VERSION 5.8 ;
BUSBITCHARS "[]" ;
DIVIDERCHAR "/" ;
UNITS
    DATABASE MICRONS 1000 ;
END UNITS

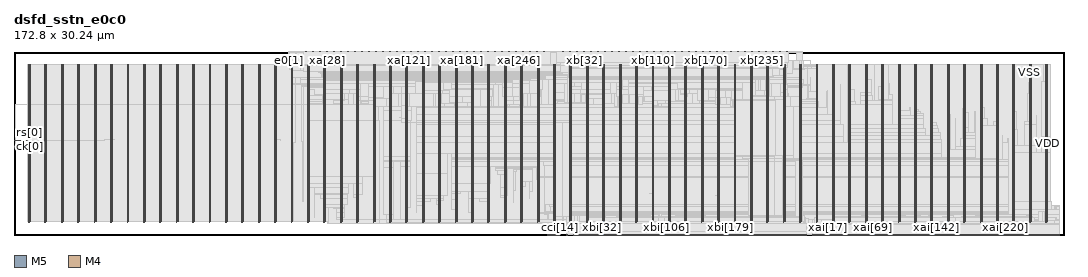
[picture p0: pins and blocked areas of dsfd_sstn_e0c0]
MACRO dsfd_sstn_e0c0
  FOREIGN dsfd_sstn_e0c0 0 0 ;
  CLASS BLOCK ;
  SIZE 172.8 BY 30.24 ;
  PIN c0[0]
    DIRECTION INPUT ;
    USE SIGNAL ;
    PORT
      LAYER M5 ;
        RECT  46.368 30.156 46.392 30.24 ;
    END
  END c0[0]
  PIN c0[1]
    DIRECTION INPUT ;
    USE SIGNAL ;
    PORT
      LAYER M5 ;
        RECT  46.512 30.156 46.536 30.24 ;
    END
  END c0[1]
  PIN cci[0]
    DIRECTION INPUT ;
    USE SIGNAL ;
    PORT
      LAYER M5 ;
        RECT  87.792 0 87.816 0.084 ;
    END
  END cci[0]
  PIN cci[10]
    DIRECTION INPUT ;
    USE SIGNAL ;
    PORT
      LAYER M5 ;
        RECT  89.232 0 89.256 0.084 ;
    END
  END cci[10]
  PIN cci[11]
    DIRECTION INPUT ;
    USE SIGNAL ;
    PORT
      LAYER M5 ;
        RECT  89.376 0 89.4 0.084 ;
    END
  END cci[11]
  PIN cci[12]
    DIRECTION INPUT ;
    USE SIGNAL ;
    PORT
      LAYER M5 ;
        RECT  89.52 0 89.544 0.084 ;
    END
  END cci[12]
  PIN cci[13]
    DIRECTION INPUT ;
    USE SIGNAL ;
    PORT
      LAYER M5 ;
        RECT  89.664 0 89.688 0.084 ;
    END
  END cci[13]
  PIN cci[14]
    DIRECTION INPUT ;
    USE SIGNAL ;
    PORT
      LAYER M5 ;
        RECT  89.808 0 89.832 0.084 ;
    END
  END cci[14]
  PIN cci[1]
    DIRECTION INPUT ;
    USE SIGNAL ;
    PORT
      LAYER M5 ;
        RECT  87.936 0 87.96 0.084 ;
    END
  END cci[1]
  PIN cci[2]
    DIRECTION INPUT ;
    USE SIGNAL ;
    PORT
      LAYER M5 ;
        RECT  88.08 0 88.104 0.084 ;
    END
  END cci[2]
  PIN cci[3]
    DIRECTION INPUT ;
    USE SIGNAL ;
    PORT
      LAYER M5 ;
        RECT  88.224 0 88.248 0.084 ;
    END
  END cci[3]
  PIN cci[4]
    DIRECTION INPUT ;
    USE SIGNAL ;
    PORT
      LAYER M5 ;
        RECT  88.368 0 88.392 0.084 ;
    END
  END cci[4]
  PIN cci[5]
    DIRECTION INPUT ;
    USE SIGNAL ;
    PORT
      LAYER M5 ;
        RECT  88.512 0 88.536 0.084 ;
    END
  END cci[5]
  PIN cci[6]
    DIRECTION INPUT ;
    USE SIGNAL ;
    PORT
      LAYER M5 ;
        RECT  88.656 0 88.68 0.084 ;
    END
  END cci[6]
  PIN cci[7]
    DIRECTION INPUT ;
    USE SIGNAL ;
    PORT
      LAYER M5 ;
        RECT  88.8 0 88.824 0.084 ;
    END
  END cci[7]
  PIN cci[8]
    DIRECTION INPUT ;
    USE SIGNAL ;
    PORT
      LAYER M5 ;
        RECT  88.944 0 88.968 0.084 ;
    END
  END cci[8]
  PIN cci[9]
    DIRECTION INPUT ;
    USE SIGNAL ;
    PORT
      LAYER M5 ;
        RECT  89.088 0 89.112 0.084 ;
    END
  END cci[9]
  PIN ck[0]
    DIRECTION INPUT ;
    USE SIGNAL ;
    PORT
      LAYER M4 ;
        RECT  0 14.592 0.084 14.616 ;
    END
    PORT
      LAYER M4 ;
        RECT  0.06 14.592 0.227 14.616 ;
    END
  END ck[0]
  PIN e0[0]
    DIRECTION INPUT ;
    USE SIGNAL ;
    PORT
      LAYER M5 ;
        RECT  45.12 30.156 45.144 30.24 ;
    END
  END e0[0]
  PIN e0[1]
    DIRECTION INPUT ;
    USE SIGNAL ;
    PORT
      LAYER M5 ;
        RECT  45.264 30.156 45.288 30.24 ;
    END
  END e0[1]
  PIN rs[0]
    DIRECTION INPUT ;
    USE SIGNAL ;
    PORT
      LAYER M4 ;
        RECT  0 15.6 0.084 15.624 ;
    END
    PORT
      LAYER M4 ;
        RECT  0.06 15.6 2.408 15.624 ;
    END
  END rs[0]
  PIN so[0]
    DIRECTION OUTPUT ;
    USE SIGNAL ;
    PORT
      LAYER M5 ;
        RECT  90.912 0 90.936 0.084 ;
    END
  END so[0]
  PIN so[1]
    DIRECTION OUTPUT ;
    USE SIGNAL ;
    PORT
      LAYER M5 ;
        RECT  91.056 0 91.08 0.084 ;
    END
  END so[1]
  PIN xa[0]
    DIRECTION OUTPUT ;
    USE SIGNAL ;
    PORT
      LAYER M5 ;
        RECT  47.616 30.156 47.64 30.24 ;
    END
  END xa[0]
  PIN xa[100]
    DIRECTION OUTPUT ;
    USE SIGNAL ;
    PORT
      LAYER M5 ;
        RECT  62.016 30.156 62.04 30.24 ;
    END
  END xa[100]
  PIN xa[101]
    DIRECTION OUTPUT ;
    USE SIGNAL ;
    PORT
      LAYER M5 ;
        RECT  62.16 30.156 62.184 30.24 ;
    END
  END xa[101]
  PIN xa[102]
    DIRECTION OUTPUT ;
    USE SIGNAL ;
    PORT
      LAYER M5 ;
        RECT  62.304 30.156 62.328 30.24 ;
    END
  END xa[102]
  PIN xa[103]
    DIRECTION OUTPUT ;
    USE SIGNAL ;
    PORT
      LAYER M5 ;
        RECT  62.448 30.156 62.472 30.24 ;
    END
  END xa[103]
  PIN xa[104]
    DIRECTION OUTPUT ;
    USE SIGNAL ;
    PORT
      LAYER M5 ;
        RECT  62.592 30.156 62.616 30.24 ;
    END
  END xa[104]
  PIN xa[105]
    DIRECTION OUTPUT ;
    USE SIGNAL ;
    PORT
      LAYER M5 ;
        RECT  62.736 30.156 62.76 30.24 ;
    END
  END xa[105]
  PIN xa[106]
    DIRECTION OUTPUT ;
    USE SIGNAL ;
    PORT
      LAYER M5 ;
        RECT  62.88 30.156 62.904 30.24 ;
    END
  END xa[106]
  PIN xa[107]
    DIRECTION OUTPUT ;
    USE SIGNAL ;
    PORT
      LAYER M5 ;
        RECT  63.024 30.156 63.048 30.24 ;
    END
  END xa[107]
  PIN xa[108]
    DIRECTION OUTPUT ;
    USE SIGNAL ;
    PORT
      LAYER M5 ;
        RECT  63.168 30.156 63.192 30.24 ;
    END
  END xa[108]
  PIN xa[109]
    DIRECTION OUTPUT ;
    USE SIGNAL ;
    PORT
      LAYER M5 ;
        RECT  63.312 30.156 63.336 30.24 ;
    END
  END xa[109]
  PIN xa[10]
    DIRECTION OUTPUT ;
    USE SIGNAL ;
    PORT
      LAYER M5 ;
        RECT  49.056 30.156 49.08 30.24 ;
    END
  END xa[10]
  PIN xa[110]
    DIRECTION OUTPUT ;
    USE SIGNAL ;
    PORT
      LAYER M5 ;
        RECT  63.456 30.156 63.48 30.24 ;
    END
  END xa[110]
  PIN xa[111]
    DIRECTION OUTPUT ;
    USE SIGNAL ;
    PORT
      LAYER M5 ;
        RECT  63.6 30.156 63.624 30.24 ;
    END
  END xa[111]
  PIN xa[112]
    DIRECTION OUTPUT ;
    USE SIGNAL ;
    PORT
      LAYER M5 ;
        RECT  63.744 30.156 63.768 30.24 ;
    END
  END xa[112]
  PIN xa[113]
    DIRECTION OUTPUT ;
    USE SIGNAL ;
    PORT
      LAYER M5 ;
        RECT  63.888 30.156 63.912 30.24 ;
    END
  END xa[113]
  PIN xa[114]
    DIRECTION OUTPUT ;
    USE SIGNAL ;
    PORT
      LAYER M5 ;
        RECT  64.032 30.156 64.056 30.24 ;
    END
  END xa[114]
  PIN xa[115]
    DIRECTION OUTPUT ;
    USE SIGNAL ;
    PORT
      LAYER M5 ;
        RECT  64.176 30.156 64.2 30.24 ;
    END
  END xa[115]
  PIN xa[116]
    DIRECTION OUTPUT ;
    USE SIGNAL ;
    PORT
      LAYER M5 ;
        RECT  64.32 30.156 64.344 30.24 ;
    END
  END xa[116]
  PIN xa[117]
    DIRECTION OUTPUT ;
    USE SIGNAL ;
    PORT
      LAYER M5 ;
        RECT  64.464 30.156 64.488 30.24 ;
    END
  END xa[117]
  PIN xa[118]
    DIRECTION OUTPUT ;
    USE SIGNAL ;
    PORT
      LAYER M5 ;
        RECT  64.608 30.156 64.632 30.24 ;
    END
  END xa[118]
  PIN xa[119]
    DIRECTION OUTPUT ;
    USE SIGNAL ;
    PORT
      LAYER M5 ;
        RECT  64.752 30.156 64.776 30.24 ;
    END
  END xa[119]
  PIN xa[11]
    DIRECTION OUTPUT ;
    USE SIGNAL ;
    PORT
      LAYER M5 ;
        RECT  49.2 30.156 49.224 30.24 ;
    END
  END xa[11]
  PIN xa[120]
    DIRECTION OUTPUT ;
    USE SIGNAL ;
    PORT
      LAYER M5 ;
        RECT  64.896 30.156 64.92 30.24 ;
    END
  END xa[120]
  PIN xa[121]
    DIRECTION OUTPUT ;
    USE SIGNAL ;
    PORT
      LAYER M5 ;
        RECT  65.04 30.156 65.064 30.24 ;
    END
  END xa[121]
  PIN xa[122]
    DIRECTION OUTPUT ;
    USE SIGNAL ;
    PORT
      LAYER M5 ;
        RECT  65.184 30.156 65.208 30.24 ;
    END
  END xa[122]
  PIN xa[123]
    DIRECTION OUTPUT ;
    USE SIGNAL ;
    PORT
      LAYER M5 ;
        RECT  65.328 30.156 65.352 30.24 ;
    END
  END xa[123]
  PIN xa[124]
    DIRECTION OUTPUT ;
    USE SIGNAL ;
    PORT
      LAYER M5 ;
        RECT  65.472 30.156 65.496 30.24 ;
    END
  END xa[124]
  PIN xa[125]
    DIRECTION OUTPUT ;
    USE SIGNAL ;
    PORT
      LAYER M5 ;
        RECT  65.616 30.156 65.64 30.24 ;
    END
  END xa[125]
  PIN xa[126]
    DIRECTION OUTPUT ;
    USE SIGNAL ;
    PORT
      LAYER M5 ;
        RECT  65.76 30.156 65.784 30.24 ;
    END
  END xa[126]
  PIN xa[127]
    DIRECTION OUTPUT ;
    USE SIGNAL ;
    PORT
      LAYER M5 ;
        RECT  65.904 30.156 65.928 30.24 ;
    END
  END xa[127]
  PIN xa[128]
    DIRECTION OUTPUT ;
    USE SIGNAL ;
    PORT
      LAYER M5 ;
        RECT  66.048 30.156 66.072 30.24 ;
    END
  END xa[128]
  PIN xa[129]
    DIRECTION OUTPUT ;
    USE SIGNAL ;
    PORT
      LAYER M5 ;
        RECT  66.192 30.156 66.216 30.24 ;
    END
  END xa[129]
  PIN xa[12]
    DIRECTION OUTPUT ;
    USE SIGNAL ;
    PORT
      LAYER M5 ;
        RECT  49.344 30.156 49.368 30.24 ;
    END
  END xa[12]
  PIN xa[130]
    DIRECTION OUTPUT ;
    USE SIGNAL ;
    PORT
      LAYER M5 ;
        RECT  66.336 30.156 66.36 30.24 ;
    END
  END xa[130]
  PIN xa[131]
    DIRECTION OUTPUT ;
    USE SIGNAL ;
    PORT
      LAYER M5 ;
        RECT  66.48 30.156 66.504 30.24 ;
    END
  END xa[131]
  PIN xa[132]
    DIRECTION OUTPUT ;
    USE SIGNAL ;
    PORT
      LAYER M5 ;
        RECT  66.624 30.156 66.648 30.24 ;
    END
  END xa[132]
  PIN xa[133]
    DIRECTION OUTPUT ;
    USE SIGNAL ;
    PORT
      LAYER M5 ;
        RECT  66.768 30.156 66.792 30.24 ;
    END
  END xa[133]
  PIN xa[134]
    DIRECTION OUTPUT ;
    USE SIGNAL ;
    PORT
      LAYER M5 ;
        RECT  66.912 30.156 66.936 30.24 ;
    END
  END xa[134]
  PIN xa[135]
    DIRECTION OUTPUT ;
    USE SIGNAL ;
    PORT
      LAYER M5 ;
        RECT  67.056 30.156 67.08 30.24 ;
    END
  END xa[135]
  PIN xa[136]
    DIRECTION OUTPUT ;
    USE SIGNAL ;
    PORT
      LAYER M5 ;
        RECT  67.2 30.156 67.224 30.24 ;
    END
  END xa[136]
  PIN xa[137]
    DIRECTION OUTPUT ;
    USE SIGNAL ;
    PORT
      LAYER M5 ;
        RECT  67.344 30.156 67.368 30.24 ;
    END
  END xa[137]
  PIN xa[138]
    DIRECTION OUTPUT ;
    USE SIGNAL ;
    PORT
      LAYER M5 ;
        RECT  67.488 30.156 67.512 30.24 ;
    END
  END xa[138]
  PIN xa[139]
    DIRECTION OUTPUT ;
    USE SIGNAL ;
    PORT
      LAYER M5 ;
        RECT  67.632 30.156 67.656 30.24 ;
    END
  END xa[139]
  PIN xa[13]
    DIRECTION OUTPUT ;
    USE SIGNAL ;
    PORT
      LAYER M5 ;
        RECT  49.488 30.156 49.512 30.24 ;
    END
  END xa[13]
  PIN xa[140]
    DIRECTION OUTPUT ;
    USE SIGNAL ;
    PORT
      LAYER M5 ;
        RECT  67.776 30.156 67.8 30.24 ;
    END
  END xa[140]
  PIN xa[141]
    DIRECTION OUTPUT ;
    USE SIGNAL ;
    PORT
      LAYER M5 ;
        RECT  67.92 30.156 67.944 30.24 ;
    END
  END xa[141]
  PIN xa[142]
    DIRECTION OUTPUT ;
    USE SIGNAL ;
    PORT
      LAYER M5 ;
        RECT  68.064 30.156 68.088 30.24 ;
    END
  END xa[142]
  PIN xa[143]
    DIRECTION OUTPUT ;
    USE SIGNAL ;
    PORT
      LAYER M5 ;
        RECT  68.208 30.156 68.232 30.24 ;
    END
  END xa[143]
  PIN xa[144]
    DIRECTION OUTPUT ;
    USE SIGNAL ;
    PORT
      LAYER M5 ;
        RECT  68.352 30.156 68.376 30.24 ;
    END
  END xa[144]
  PIN xa[145]
    DIRECTION OUTPUT ;
    USE SIGNAL ;
    PORT
      LAYER M5 ;
        RECT  68.496 30.156 68.52 30.24 ;
    END
  END xa[145]
  PIN xa[146]
    DIRECTION OUTPUT ;
    USE SIGNAL ;
    PORT
      LAYER M5 ;
        RECT  68.64 30.156 68.664 30.24 ;
    END
  END xa[146]
  PIN xa[147]
    DIRECTION OUTPUT ;
    USE SIGNAL ;
    PORT
      LAYER M5 ;
        RECT  68.784 30.156 68.808 30.24 ;
    END
  END xa[147]
  PIN xa[148]
    DIRECTION OUTPUT ;
    USE SIGNAL ;
    PORT
      LAYER M5 ;
        RECT  68.928 30.156 68.952 30.24 ;
    END
  END xa[148]
  PIN xa[149]
    DIRECTION OUTPUT ;
    USE SIGNAL ;
    PORT
      LAYER M5 ;
        RECT  69.072 30.156 69.096 30.24 ;
    END
  END xa[149]
  PIN xa[14]
    DIRECTION OUTPUT ;
    USE SIGNAL ;
    PORT
      LAYER M5 ;
        RECT  49.632 30.156 49.656 30.24 ;
    END
  END xa[14]
  PIN xa[150]
    DIRECTION OUTPUT ;
    USE SIGNAL ;
    PORT
      LAYER M5 ;
        RECT  69.216 30.156 69.24 30.24 ;
    END
  END xa[150]
  PIN xa[151]
    DIRECTION OUTPUT ;
    USE SIGNAL ;
    PORT
      LAYER M5 ;
        RECT  69.36 30.156 69.384 30.24 ;
    END
  END xa[151]
  PIN xa[152]
    DIRECTION OUTPUT ;
    USE SIGNAL ;
    PORT
      LAYER M5 ;
        RECT  69.504 30.156 69.528 30.24 ;
    END
  END xa[152]
  PIN xa[153]
    DIRECTION OUTPUT ;
    USE SIGNAL ;
    PORT
      LAYER M5 ;
        RECT  69.648 30.156 69.672 30.24 ;
    END
  END xa[153]
  PIN xa[154]
    DIRECTION OUTPUT ;
    USE SIGNAL ;
    PORT
      LAYER M5 ;
        RECT  69.792 30.156 69.816 30.24 ;
    END
  END xa[154]
  PIN xa[155]
    DIRECTION OUTPUT ;
    USE SIGNAL ;
    PORT
      LAYER M5 ;
        RECT  69.936 30.156 69.96 30.24 ;
    END
  END xa[155]
  PIN xa[156]
    DIRECTION OUTPUT ;
    USE SIGNAL ;
    PORT
      LAYER M5 ;
        RECT  70.08 30.156 70.104 30.24 ;
    END
  END xa[156]
  PIN xa[157]
    DIRECTION OUTPUT ;
    USE SIGNAL ;
    PORT
      LAYER M5 ;
        RECT  70.224 30.156 70.248 30.24 ;
    END
  END xa[157]
  PIN xa[158]
    DIRECTION OUTPUT ;
    USE SIGNAL ;
    PORT
      LAYER M5 ;
        RECT  70.368 30.156 70.392 30.24 ;
    END
  END xa[158]
  PIN xa[159]
    DIRECTION OUTPUT ;
    USE SIGNAL ;
    PORT
      LAYER M5 ;
        RECT  70.512 30.156 70.536 30.24 ;
    END
  END xa[159]
  PIN xa[15]
    DIRECTION OUTPUT ;
    USE SIGNAL ;
    PORT
      LAYER M5 ;
        RECT  49.776 30.156 49.8 30.24 ;
    END
  END xa[15]
  PIN xa[160]
    DIRECTION OUTPUT ;
    USE SIGNAL ;
    PORT
      LAYER M5 ;
        RECT  70.656 30.156 70.68 30.24 ;
    END
  END xa[160]
  PIN xa[161]
    DIRECTION OUTPUT ;
    USE SIGNAL ;
    PORT
      LAYER M5 ;
        RECT  70.8 30.156 70.824 30.24 ;
    END
  END xa[161]
  PIN xa[162]
    DIRECTION OUTPUT ;
    USE SIGNAL ;
    PORT
      LAYER M5 ;
        RECT  70.944 30.156 70.968 30.24 ;
    END
  END xa[162]
  PIN xa[163]
    DIRECTION OUTPUT ;
    USE SIGNAL ;
    PORT
      LAYER M5 ;
        RECT  71.088 30.156 71.112 30.24 ;
    END
  END xa[163]
  PIN xa[164]
    DIRECTION OUTPUT ;
    USE SIGNAL ;
    PORT
      LAYER M5 ;
        RECT  71.232 30.156 71.256 30.24 ;
    END
  END xa[164]
  PIN xa[165]
    DIRECTION OUTPUT ;
    USE SIGNAL ;
    PORT
      LAYER M5 ;
        RECT  71.376 30.156 71.4 30.24 ;
    END
  END xa[165]
  PIN xa[166]
    DIRECTION OUTPUT ;
    USE SIGNAL ;
    PORT
      LAYER M5 ;
        RECT  71.52 30.156 71.544 30.24 ;
    END
  END xa[166]
  PIN xa[167]
    DIRECTION OUTPUT ;
    USE SIGNAL ;
    PORT
      LAYER M5 ;
        RECT  71.664 30.156 71.688 30.24 ;
    END
  END xa[167]
  PIN xa[168]
    DIRECTION OUTPUT ;
    USE SIGNAL ;
    PORT
      LAYER M5 ;
        RECT  71.808 30.156 71.832 30.24 ;
    END
  END xa[168]
  PIN xa[169]
    DIRECTION OUTPUT ;
    USE SIGNAL ;
    PORT
      LAYER M5 ;
        RECT  71.952 30.156 71.976 30.24 ;
    END
  END xa[169]
  PIN xa[16]
    DIRECTION OUTPUT ;
    USE SIGNAL ;
    PORT
      LAYER M5 ;
        RECT  49.92 30.156 49.944 30.24 ;
    END
  END xa[16]
  PIN xa[170]
    DIRECTION OUTPUT ;
    USE SIGNAL ;
    PORT
      LAYER M5 ;
        RECT  72.096 30.156 72.12 30.24 ;
    END
  END xa[170]
  PIN xa[171]
    DIRECTION OUTPUT ;
    USE SIGNAL ;
    PORT
      LAYER M5 ;
        RECT  72.24 30.156 72.264 30.24 ;
    END
  END xa[171]
  PIN xa[172]
    DIRECTION OUTPUT ;
    USE SIGNAL ;
    PORT
      LAYER M5 ;
        RECT  72.384 30.156 72.408 30.24 ;
    END
  END xa[172]
  PIN xa[173]
    DIRECTION OUTPUT ;
    USE SIGNAL ;
    PORT
      LAYER M5 ;
        RECT  72.528 30.156 72.552 30.24 ;
    END
  END xa[173]
  PIN xa[174]
    DIRECTION OUTPUT ;
    USE SIGNAL ;
    PORT
      LAYER M5 ;
        RECT  72.672 30.156 72.696 30.24 ;
    END
  END xa[174]
  PIN xa[175]
    DIRECTION OUTPUT ;
    USE SIGNAL ;
    PORT
      LAYER M5 ;
        RECT  72.816 30.156 72.84 30.24 ;
    END
  END xa[175]
  PIN xa[176]
    DIRECTION OUTPUT ;
    USE SIGNAL ;
    PORT
      LAYER M5 ;
        RECT  72.96 30.156 72.984 30.24 ;
    END
  END xa[176]
  PIN xa[177]
    DIRECTION OUTPUT ;
    USE SIGNAL ;
    PORT
      LAYER M5 ;
        RECT  73.104 30.156 73.128 30.24 ;
    END
  END xa[177]
  PIN xa[178]
    DIRECTION OUTPUT ;
    USE SIGNAL ;
    PORT
      LAYER M5 ;
        RECT  73.248 30.156 73.272 30.24 ;
    END
  END xa[178]
  PIN xa[179]
    DIRECTION OUTPUT ;
    USE SIGNAL ;
    PORT
      LAYER M5 ;
        RECT  73.392 30.156 73.416 30.24 ;
    END
  END xa[179]
  PIN xa[17]
    DIRECTION OUTPUT ;
    USE SIGNAL ;
    PORT
      LAYER M5 ;
        RECT  50.064 30.156 50.088 30.24 ;
    END
  END xa[17]
  PIN xa[180]
    DIRECTION OUTPUT ;
    USE SIGNAL ;
    PORT
      LAYER M5 ;
        RECT  73.536 30.156 73.56 30.24 ;
    END
  END xa[180]
  PIN xa[181]
    DIRECTION OUTPUT ;
    USE SIGNAL ;
    PORT
      LAYER M5 ;
        RECT  73.68 30.156 73.704 30.24 ;
    END
  END xa[181]
  PIN xa[182]
    DIRECTION OUTPUT ;
    USE SIGNAL ;
    PORT
      LAYER M5 ;
        RECT  73.824 30.156 73.848 30.24 ;
    END
  END xa[182]
  PIN xa[183]
    DIRECTION OUTPUT ;
    USE SIGNAL ;
    PORT
      LAYER M5 ;
        RECT  73.968 30.156 73.992 30.24 ;
    END
  END xa[183]
  PIN xa[184]
    DIRECTION OUTPUT ;
    USE SIGNAL ;
    PORT
      LAYER M5 ;
        RECT  74.112 30.156 74.136 30.24 ;
    END
  END xa[184]
  PIN xa[185]
    DIRECTION OUTPUT ;
    USE SIGNAL ;
    PORT
      LAYER M5 ;
        RECT  74.256 30.156 74.28 30.24 ;
    END
  END xa[185]
  PIN xa[186]
    DIRECTION OUTPUT ;
    USE SIGNAL ;
    PORT
      LAYER M5 ;
        RECT  74.4 30.156 74.424 30.24 ;
    END
  END xa[186]
  PIN xa[187]
    DIRECTION OUTPUT ;
    USE SIGNAL ;
    PORT
      LAYER M5 ;
        RECT  74.544 30.156 74.568 30.24 ;
    END
  END xa[187]
  PIN xa[188]
    DIRECTION OUTPUT ;
    USE SIGNAL ;
    PORT
      LAYER M5 ;
        RECT  74.688 30.156 74.712 30.24 ;
    END
  END xa[188]
  PIN xa[189]
    DIRECTION OUTPUT ;
    USE SIGNAL ;
    PORT
      LAYER M5 ;
        RECT  74.832 30.156 74.856 30.24 ;
    END
  END xa[189]
  PIN xa[18]
    DIRECTION OUTPUT ;
    USE SIGNAL ;
    PORT
      LAYER M5 ;
        RECT  50.208 30.156 50.232 30.24 ;
    END
  END xa[18]
  PIN xa[190]
    DIRECTION OUTPUT ;
    USE SIGNAL ;
    PORT
      LAYER M5 ;
        RECT  74.976 30.156 75 30.24 ;
    END
  END xa[190]
  PIN xa[191]
    DIRECTION OUTPUT ;
    USE SIGNAL ;
    PORT
      LAYER M5 ;
        RECT  75.12 30.156 75.144 30.24 ;
    END
  END xa[191]
  PIN xa[192]
    DIRECTION OUTPUT ;
    USE SIGNAL ;
    PORT
      LAYER M5 ;
        RECT  75.264 30.156 75.288 30.24 ;
    END
  END xa[192]
  PIN xa[193]
    DIRECTION OUTPUT ;
    USE SIGNAL ;
    PORT
      LAYER M5 ;
        RECT  75.408 30.156 75.432 30.24 ;
    END
  END xa[193]
  PIN xa[194]
    DIRECTION OUTPUT ;
    USE SIGNAL ;
    PORT
      LAYER M5 ;
        RECT  75.552 30.156 75.576 30.24 ;
    END
  END xa[194]
  PIN xa[195]
    DIRECTION OUTPUT ;
    USE SIGNAL ;
    PORT
      LAYER M5 ;
        RECT  75.696 30.156 75.72 30.24 ;
    END
  END xa[195]
  PIN xa[196]
    DIRECTION OUTPUT ;
    USE SIGNAL ;
    PORT
      LAYER M5 ;
        RECT  75.84 30.156 75.864 30.24 ;
    END
  END xa[196]
  PIN xa[197]
    DIRECTION OUTPUT ;
    USE SIGNAL ;
    PORT
      LAYER M5 ;
        RECT  75.984 30.156 76.008 30.24 ;
    END
  END xa[197]
  PIN xa[198]
    DIRECTION OUTPUT ;
    USE SIGNAL ;
    PORT
      LAYER M5 ;
        RECT  76.128 30.156 76.152 30.24 ;
    END
  END xa[198]
  PIN xa[199]
    DIRECTION OUTPUT ;
    USE SIGNAL ;
    PORT
      LAYER M5 ;
        RECT  76.272 30.156 76.296 30.24 ;
    END
  END xa[199]
  PIN xa[19]
    DIRECTION OUTPUT ;
    USE SIGNAL ;
    PORT
      LAYER M5 ;
        RECT  50.352 30.156 50.376 30.24 ;
    END
  END xa[19]
  PIN xa[1]
    DIRECTION OUTPUT ;
    USE SIGNAL ;
    PORT
      LAYER M5 ;
        RECT  47.76 30.156 47.784 30.24 ;
    END
  END xa[1]
  PIN xa[200]
    DIRECTION OUTPUT ;
    USE SIGNAL ;
    PORT
      LAYER M5 ;
        RECT  76.416 30.156 76.44 30.24 ;
    END
  END xa[200]
  PIN xa[201]
    DIRECTION OUTPUT ;
    USE SIGNAL ;
    PORT
      LAYER M5 ;
        RECT  76.56 30.156 76.584 30.24 ;
    END
  END xa[201]
  PIN xa[202]
    DIRECTION OUTPUT ;
    USE SIGNAL ;
    PORT
      LAYER M5 ;
        RECT  76.704 30.156 76.728 30.24 ;
    END
  END xa[202]
  PIN xa[203]
    DIRECTION OUTPUT ;
    USE SIGNAL ;
    PORT
      LAYER M5 ;
        RECT  76.848 30.156 76.872 30.24 ;
    END
  END xa[203]
  PIN xa[204]
    DIRECTION OUTPUT ;
    USE SIGNAL ;
    PORT
      LAYER M5 ;
        RECT  76.992 30.156 77.016 30.24 ;
    END
  END xa[204]
  PIN xa[205]
    DIRECTION OUTPUT ;
    USE SIGNAL ;
    PORT
      LAYER M5 ;
        RECT  77.136 30.156 77.16 30.24 ;
    END
  END xa[205]
  PIN xa[206]
    DIRECTION OUTPUT ;
    USE SIGNAL ;
    PORT
      LAYER M5 ;
        RECT  77.28 30.156 77.304 30.24 ;
    END
  END xa[206]
  PIN xa[207]
    DIRECTION OUTPUT ;
    USE SIGNAL ;
    PORT
      LAYER M5 ;
        RECT  77.424 30.156 77.448 30.24 ;
    END
  END xa[207]
  PIN xa[208]
    DIRECTION OUTPUT ;
    USE SIGNAL ;
    PORT
      LAYER M5 ;
        RECT  77.568 30.156 77.592 30.24 ;
    END
  END xa[208]
  PIN xa[209]
    DIRECTION OUTPUT ;
    USE SIGNAL ;
    PORT
      LAYER M5 ;
        RECT  77.712 30.156 77.736 30.24 ;
    END
  END xa[209]
  PIN xa[20]
    DIRECTION OUTPUT ;
    USE SIGNAL ;
    PORT
      LAYER M5 ;
        RECT  50.496 30.156 50.52 30.24 ;
    END
  END xa[20]
  PIN xa[210]
    DIRECTION OUTPUT ;
    USE SIGNAL ;
    PORT
      LAYER M5 ;
        RECT  77.856 30.156 77.88 30.24 ;
    END
  END xa[210]
  PIN xa[211]
    DIRECTION OUTPUT ;
    USE SIGNAL ;
    PORT
      LAYER M5 ;
        RECT  78 30.156 78.024 30.24 ;
    END
  END xa[211]
  PIN xa[212]
    DIRECTION OUTPUT ;
    USE SIGNAL ;
    PORT
      LAYER M5 ;
        RECT  78.144 30.156 78.168 30.24 ;
    END
  END xa[212]
  PIN xa[213]
    DIRECTION OUTPUT ;
    USE SIGNAL ;
    PORT
      LAYER M5 ;
        RECT  78.288 30.156 78.312 30.24 ;
    END
  END xa[213]
  PIN xa[214]
    DIRECTION OUTPUT ;
    USE SIGNAL ;
    PORT
      LAYER M5 ;
        RECT  78.432 30.156 78.456 30.24 ;
    END
  END xa[214]
  PIN xa[215]
    DIRECTION OUTPUT ;
    USE SIGNAL ;
    PORT
      LAYER M5 ;
        RECT  78.576 30.156 78.6 30.24 ;
    END
  END xa[215]
  PIN xa[216]
    DIRECTION OUTPUT ;
    USE SIGNAL ;
    PORT
      LAYER M5 ;
        RECT  78.72 30.156 78.744 30.24 ;
    END
  END xa[216]
  PIN xa[217]
    DIRECTION OUTPUT ;
    USE SIGNAL ;
    PORT
      LAYER M5 ;
        RECT  78.864 30.156 78.888 30.24 ;
    END
  END xa[217]
  PIN xa[218]
    DIRECTION OUTPUT ;
    USE SIGNAL ;
    PORT
      LAYER M5 ;
        RECT  79.008 30.156 79.032 30.24 ;
    END
  END xa[218]
  PIN xa[219]
    DIRECTION OUTPUT ;
    USE SIGNAL ;
    PORT
      LAYER M5 ;
        RECT  79.152 30.156 79.176 30.24 ;
    END
  END xa[219]
  PIN xa[21]
    DIRECTION OUTPUT ;
    USE SIGNAL ;
    PORT
      LAYER M5 ;
        RECT  50.64 30.156 50.664 30.24 ;
    END
  END xa[21]
  PIN xa[220]
    DIRECTION OUTPUT ;
    USE SIGNAL ;
    PORT
      LAYER M5 ;
        RECT  79.296 30.156 79.32 30.24 ;
    END
  END xa[220]
  PIN xa[221]
    DIRECTION OUTPUT ;
    USE SIGNAL ;
    PORT
      LAYER M5 ;
        RECT  79.44 30.156 79.464 30.24 ;
    END
  END xa[221]
  PIN xa[222]
    DIRECTION OUTPUT ;
    USE SIGNAL ;
    PORT
      LAYER M5 ;
        RECT  79.584 30.156 79.608 30.24 ;
    END
  END xa[222]
  PIN xa[223]
    DIRECTION OUTPUT ;
    USE SIGNAL ;
    PORT
      LAYER M5 ;
        RECT  79.728 30.156 79.752 30.24 ;
    END
  END xa[223]
  PIN xa[224]
    DIRECTION OUTPUT ;
    USE SIGNAL ;
    PORT
      LAYER M5 ;
        RECT  79.872 30.156 79.896 30.24 ;
    END
  END xa[224]
  PIN xa[225]
    DIRECTION OUTPUT ;
    USE SIGNAL ;
    PORT
      LAYER M5 ;
        RECT  80.016 30.156 80.04 30.24 ;
    END
  END xa[225]
  PIN xa[226]
    DIRECTION OUTPUT ;
    USE SIGNAL ;
    PORT
      LAYER M5 ;
        RECT  80.16 30.156 80.184 30.24 ;
    END
  END xa[226]
  PIN xa[227]
    DIRECTION OUTPUT ;
    USE SIGNAL ;
    PORT
      LAYER M5 ;
        RECT  80.304 30.156 80.328 30.24 ;
    END
  END xa[227]
  PIN xa[228]
    DIRECTION OUTPUT ;
    USE SIGNAL ;
    PORT
      LAYER M5 ;
        RECT  80.448 30.156 80.472 30.24 ;
    END
  END xa[228]
  PIN xa[229]
    DIRECTION OUTPUT ;
    USE SIGNAL ;
    PORT
      LAYER M5 ;
        RECT  80.592 30.156 80.616 30.24 ;
    END
  END xa[229]
  PIN xa[22]
    DIRECTION OUTPUT ;
    USE SIGNAL ;
    PORT
      LAYER M5 ;
        RECT  50.784 30.156 50.808 30.24 ;
    END
  END xa[22]
  PIN xa[230]
    DIRECTION OUTPUT ;
    USE SIGNAL ;
    PORT
      LAYER M5 ;
        RECT  80.736 30.156 80.76 30.24 ;
    END
  END xa[230]
  PIN xa[231]
    DIRECTION OUTPUT ;
    USE SIGNAL ;
    PORT
      LAYER M5 ;
        RECT  80.88 30.156 80.904 30.24 ;
    END
  END xa[231]
  PIN xa[232]
    DIRECTION OUTPUT ;
    USE SIGNAL ;
    PORT
      LAYER M5 ;
        RECT  81.024 30.156 81.048 30.24 ;
    END
  END xa[232]
  PIN xa[233]
    DIRECTION OUTPUT ;
    USE SIGNAL ;
    PORT
      LAYER M5 ;
        RECT  81.168 30.156 81.192 30.24 ;
    END
  END xa[233]
  PIN xa[234]
    DIRECTION OUTPUT ;
    USE SIGNAL ;
    PORT
      LAYER M5 ;
        RECT  81.312 30.156 81.336 30.24 ;
    END
  END xa[234]
  PIN xa[235]
    DIRECTION OUTPUT ;
    USE SIGNAL ;
    PORT
      LAYER M5 ;
        RECT  81.456 30.156 81.48 30.24 ;
    END
  END xa[235]
  PIN xa[236]
    DIRECTION OUTPUT ;
    USE SIGNAL ;
    PORT
      LAYER M5 ;
        RECT  81.6 30.156 81.624 30.24 ;
    END
  END xa[236]
  PIN xa[237]
    DIRECTION OUTPUT ;
    USE SIGNAL ;
    PORT
      LAYER M5 ;
        RECT  81.744 30.156 81.768 30.24 ;
    END
  END xa[237]
  PIN xa[238]
    DIRECTION OUTPUT ;
    USE SIGNAL ;
    PORT
      LAYER M5 ;
        RECT  81.888 30.156 81.912 30.24 ;
    END
  END xa[238]
  PIN xa[239]
    DIRECTION OUTPUT ;
    USE SIGNAL ;
    PORT
      LAYER M5 ;
        RECT  82.032 30.156 82.056 30.24 ;
    END
  END xa[239]
  PIN xa[23]
    DIRECTION OUTPUT ;
    USE SIGNAL ;
    PORT
      LAYER M5 ;
        RECT  50.928 30.156 50.952 30.24 ;
    END
  END xa[23]
  PIN xa[240]
    DIRECTION OUTPUT ;
    USE SIGNAL ;
    PORT
      LAYER M5 ;
        RECT  82.176 30.156 82.2 30.24 ;
    END
  END xa[240]
  PIN xa[241]
    DIRECTION OUTPUT ;
    USE SIGNAL ;
    PORT
      LAYER M5 ;
        RECT  82.32 30.156 82.344 30.24 ;
    END
  END xa[241]
  PIN xa[242]
    DIRECTION OUTPUT ;
    USE SIGNAL ;
    PORT
      LAYER M5 ;
        RECT  82.464 30.156 82.488 30.24 ;
    END
  END xa[242]
  PIN xa[243]
    DIRECTION OUTPUT ;
    USE SIGNAL ;
    PORT
      LAYER M5 ;
        RECT  82.608 30.156 82.632 30.24 ;
    END
  END xa[243]
  PIN xa[244]
    DIRECTION OUTPUT ;
    USE SIGNAL ;
    PORT
      LAYER M5 ;
        RECT  82.752 30.156 82.776 30.24 ;
    END
  END xa[244]
  PIN xa[245]
    DIRECTION OUTPUT ;
    USE SIGNAL ;
    PORT
      LAYER M5 ;
        RECT  82.896 30.156 82.92 30.24 ;
    END
  END xa[245]
  PIN xa[246]
    DIRECTION OUTPUT ;
    USE SIGNAL ;
    PORT
      LAYER M5 ;
        RECT  83.04 30.156 83.064 30.24 ;
    END
  END xa[246]
  PIN xa[247]
    DIRECTION OUTPUT ;
    USE SIGNAL ;
    PORT
      LAYER M5 ;
        RECT  83.184 30.156 83.208 30.24 ;
    END
  END xa[247]
  PIN xa[248]
    DIRECTION OUTPUT ;
    USE SIGNAL ;
    PORT
      LAYER M5 ;
        RECT  83.328 30.156 83.352 30.24 ;
    END
  END xa[248]
  PIN xa[249]
    DIRECTION OUTPUT ;
    USE SIGNAL ;
    PORT
      LAYER M5 ;
        RECT  83.472 30.156 83.496 30.24 ;
    END
  END xa[249]
  PIN xa[24]
    DIRECTION OUTPUT ;
    USE SIGNAL ;
    PORT
      LAYER M5 ;
        RECT  51.072 30.156 51.096 30.24 ;
    END
  END xa[24]
  PIN xa[250]
    DIRECTION OUTPUT ;
    USE SIGNAL ;
    PORT
      LAYER M5 ;
        RECT  83.616 30.156 83.64 30.24 ;
    END
  END xa[250]
  PIN xa[251]
    DIRECTION OUTPUT ;
    USE SIGNAL ;
    PORT
      LAYER M5 ;
        RECT  83.76 30.156 83.784 30.24 ;
    END
  END xa[251]
  PIN xa[252]
    DIRECTION OUTPUT ;
    USE SIGNAL ;
    PORT
      LAYER M5 ;
        RECT  83.904 30.156 83.928 30.24 ;
    END
  END xa[252]
  PIN xa[253]
    DIRECTION OUTPUT ;
    USE SIGNAL ;
    PORT
      LAYER M5 ;
        RECT  84.048 30.156 84.072 30.24 ;
    END
  END xa[253]
  PIN xa[254]
    DIRECTION OUTPUT ;
    USE SIGNAL ;
    PORT
      LAYER M5 ;
        RECT  84.192 30.156 84.216 30.24 ;
    END
  END xa[254]
  PIN xa[255]
    DIRECTION OUTPUT ;
    USE SIGNAL ;
    PORT
      LAYER M5 ;
        RECT  84.336 30.156 84.36 30.24 ;
    END
  END xa[255]
  PIN xa[256]
    DIRECTION OUTPUT ;
    USE SIGNAL ;
    PORT
      LAYER M5 ;
        RECT  84.48 30.156 84.504 30.24 ;
    END
  END xa[256]
  PIN xa[257]
    DIRECTION OUTPUT ;
    USE SIGNAL ;
    PORT
      LAYER M5 ;
        RECT  84.624 30.156 84.648 30.24 ;
    END
  END xa[257]
  PIN xa[258]
    DIRECTION OUTPUT ;
    USE SIGNAL ;
    PORT
      LAYER M5 ;
        RECT  84.768 30.156 84.792 30.24 ;
    END
  END xa[258]
  PIN xa[259]
    DIRECTION OUTPUT ;
    USE SIGNAL ;
    PORT
      LAYER M5 ;
        RECT  84.912 30.156 84.936 30.24 ;
    END
  END xa[259]
  PIN xa[25]
    DIRECTION OUTPUT ;
    USE SIGNAL ;
    PORT
      LAYER M5 ;
        RECT  51.216 30.156 51.24 30.24 ;
    END
  END xa[25]
  PIN xa[260]
    DIRECTION OUTPUT ;
    USE SIGNAL ;
    PORT
      LAYER M5 ;
        RECT  85.056 30.156 85.08 30.24 ;
    END
  END xa[260]
  PIN xa[261]
    DIRECTION OUTPUT ;
    USE SIGNAL ;
    PORT
      LAYER M5 ;
        RECT  85.2 30.156 85.224 30.24 ;
    END
  END xa[261]
  PIN xa[262]
    DIRECTION OUTPUT ;
    USE SIGNAL ;
    PORT
      LAYER M5 ;
        RECT  85.344 30.156 85.368 30.24 ;
    END
  END xa[262]
  PIN xa[263]
    DIRECTION OUTPUT ;
    USE SIGNAL ;
    PORT
      LAYER M5 ;
        RECT  85.488 30.156 85.512 30.24 ;
    END
  END xa[263]
  PIN xa[264]
    DIRECTION OUTPUT ;
    USE SIGNAL ;
    PORT
      LAYER M5 ;
        RECT  85.632 30.156 85.656 30.24 ;
    END
  END xa[264]
  PIN xa[265]
    DIRECTION OUTPUT ;
    USE SIGNAL ;
    PORT
      LAYER M5 ;
        RECT  85.776 30.156 85.8 30.24 ;
    END
  END xa[265]
  PIN xa[266]
    DIRECTION OUTPUT ;
    USE SIGNAL ;
    PORT
      LAYER M5 ;
        RECT  85.92 30.156 85.944 30.24 ;
    END
  END xa[266]
  PIN xa[267]
    DIRECTION OUTPUT ;
    USE SIGNAL ;
    PORT
      LAYER M5 ;
        RECT  86.064 30.156 86.088 30.24 ;
    END
  END xa[267]
  PIN xa[268]
    DIRECTION OUTPUT ;
    USE SIGNAL ;
    PORT
      LAYER M5 ;
        RECT  86.208 30.156 86.232 30.24 ;
    END
  END xa[268]
  PIN xa[269]
    DIRECTION OUTPUT ;
    USE SIGNAL ;
    PORT
      LAYER M5 ;
        RECT  86.352 30.156 86.376 30.24 ;
    END
  END xa[269]
  PIN xa[26]
    DIRECTION OUTPUT ;
    USE SIGNAL ;
    PORT
      LAYER M5 ;
        RECT  51.36 30.156 51.384 30.24 ;
    END
  END xa[26]
  PIN xa[270]
    DIRECTION OUTPUT ;
    USE SIGNAL ;
    PORT
      LAYER M5 ;
        RECT  86.496 30.156 86.52 30.24 ;
    END
  END xa[270]
  PIN xa[271]
    DIRECTION OUTPUT ;
    USE SIGNAL ;
    PORT
      LAYER M5 ;
        RECT  86.64 30.156 86.664 30.24 ;
    END
  END xa[271]
  PIN xa[272]
    DIRECTION OUTPUT ;
    USE SIGNAL ;
    PORT
      LAYER M5 ;
        RECT  86.784 30.156 86.808 30.24 ;
    END
  END xa[272]
  PIN xa[273]
    DIRECTION OUTPUT ;
    USE SIGNAL ;
    PORT
      LAYER M5 ;
        RECT  86.928 30.156 86.952 30.24 ;
    END
  END xa[273]
  PIN xa[274]
    DIRECTION OUTPUT ;
    USE SIGNAL ;
    PORT
      LAYER M5 ;
        RECT  87.072 30.156 87.096 30.24 ;
    END
  END xa[274]
  PIN xa[275]
    DIRECTION OUTPUT ;
    USE SIGNAL ;
    PORT
      LAYER M5 ;
        RECT  87.216 30.156 87.24 30.24 ;
    END
  END xa[275]
  PIN xa[276]
    DIRECTION OUTPUT ;
    USE SIGNAL ;
    PORT
      LAYER M5 ;
        RECT  87.36 30.156 87.384 30.24 ;
    END
  END xa[276]
  PIN xa[277]
    DIRECTION OUTPUT ;
    USE SIGNAL ;
    PORT
      LAYER M5 ;
        RECT  87.504 30.156 87.528 30.24 ;
    END
  END xa[277]
  PIN xa[278]
    DIRECTION OUTPUT ;
    USE SIGNAL ;
    PORT
      LAYER M5 ;
        RECT  87.648 30.156 87.672 30.24 ;
    END
  END xa[278]
  PIN xa[279]
    DIRECTION OUTPUT ;
    USE SIGNAL ;
    PORT
      LAYER M5 ;
        RECT  87.792 30.156 87.816 30.24 ;
    END
  END xa[279]
  PIN xa[27]
    DIRECTION OUTPUT ;
    USE SIGNAL ;
    PORT
      LAYER M5 ;
        RECT  51.504 30.156 51.528 30.24 ;
    END
  END xa[27]
  PIN xa[280]
    DIRECTION OUTPUT ;
    USE SIGNAL ;
    PORT
      LAYER M5 ;
        RECT  87.936 30.156 87.96 30.24 ;
    END
  END xa[280]
  PIN xa[281]
    DIRECTION OUTPUT ;
    USE SIGNAL ;
    PORT
      LAYER M5 ;
        RECT  88.08 30.156 88.104 30.24 ;
    END
  END xa[281]
  PIN xa[282]
    DIRECTION OUTPUT ;
    USE SIGNAL ;
    PORT
      LAYER M5 ;
        RECT  88.224 30.156 88.248 30.24 ;
    END
  END xa[282]
  PIN xa[28]
    DIRECTION OUTPUT ;
    USE SIGNAL ;
    PORT
      LAYER M5 ;
        RECT  51.648 30.156 51.672 30.24 ;
    END
  END xa[28]
  PIN xa[29]
    DIRECTION OUTPUT ;
    USE SIGNAL ;
    PORT
      LAYER M5 ;
        RECT  51.792 30.156 51.816 30.24 ;
    END
  END xa[29]
  PIN xa[2]
    DIRECTION OUTPUT ;
    USE SIGNAL ;
    PORT
      LAYER M5 ;
        RECT  47.904 30.156 47.928 30.24 ;
    END
  END xa[2]
  PIN xa[30]
    DIRECTION OUTPUT ;
    USE SIGNAL ;
    PORT
      LAYER M5 ;
        RECT  51.936 30.156 51.96 30.24 ;
    END
  END xa[30]
  PIN xa[31]
    DIRECTION OUTPUT ;
    USE SIGNAL ;
    PORT
      LAYER M5 ;
        RECT  52.08 30.156 52.104 30.24 ;
    END
  END xa[31]
  PIN xa[32]
    DIRECTION OUTPUT ;
    USE SIGNAL ;
    PORT
      LAYER M5 ;
        RECT  52.224 30.156 52.248 30.24 ;
    END
  END xa[32]
  PIN xa[33]
    DIRECTION OUTPUT ;
    USE SIGNAL ;
    PORT
      LAYER M5 ;
        RECT  52.368 30.156 52.392 30.24 ;
    END
  END xa[33]
  PIN xa[34]
    DIRECTION OUTPUT ;
    USE SIGNAL ;
    PORT
      LAYER M5 ;
        RECT  52.512 30.156 52.536 30.24 ;
    END
  END xa[34]
  PIN xa[35]
    DIRECTION OUTPUT ;
    USE SIGNAL ;
    PORT
      LAYER M5 ;
        RECT  52.656 30.156 52.68 30.24 ;
    END
  END xa[35]
  PIN xa[36]
    DIRECTION OUTPUT ;
    USE SIGNAL ;
    PORT
      LAYER M5 ;
        RECT  52.8 30.156 52.824 30.24 ;
    END
  END xa[36]
  PIN xa[37]
    DIRECTION OUTPUT ;
    USE SIGNAL ;
    PORT
      LAYER M5 ;
        RECT  52.944 30.156 52.968 30.24 ;
    END
  END xa[37]
  PIN xa[38]
    DIRECTION OUTPUT ;
    USE SIGNAL ;
    PORT
      LAYER M5 ;
        RECT  53.088 30.156 53.112 30.24 ;
    END
  END xa[38]
  PIN xa[39]
    DIRECTION OUTPUT ;
    USE SIGNAL ;
    PORT
      LAYER M5 ;
        RECT  53.232 30.156 53.256 30.24 ;
    END
  END xa[39]
  PIN xa[3]
    DIRECTION OUTPUT ;
    USE SIGNAL ;
    PORT
      LAYER M5 ;
        RECT  48.048 30.156 48.072 30.24 ;
    END
  END xa[3]
  PIN xa[40]
    DIRECTION OUTPUT ;
    USE SIGNAL ;
    PORT
      LAYER M5 ;
        RECT  53.376 30.156 53.4 30.24 ;
    END
  END xa[40]
  PIN xa[41]
    DIRECTION OUTPUT ;
    USE SIGNAL ;
    PORT
      LAYER M5 ;
        RECT  53.52 30.156 53.544 30.24 ;
    END
  END xa[41]
  PIN xa[42]
    DIRECTION OUTPUT ;
    USE SIGNAL ;
    PORT
      LAYER M5 ;
        RECT  53.664 30.156 53.688 30.24 ;
    END
  END xa[42]
  PIN xa[43]
    DIRECTION OUTPUT ;
    USE SIGNAL ;
    PORT
      LAYER M5 ;
        RECT  53.808 30.156 53.832 30.24 ;
    END
  END xa[43]
  PIN xa[44]
    DIRECTION OUTPUT ;
    USE SIGNAL ;
    PORT
      LAYER M5 ;
        RECT  53.952 30.156 53.976 30.24 ;
    END
  END xa[44]
  PIN xa[45]
    DIRECTION OUTPUT ;
    USE SIGNAL ;
    PORT
      LAYER M5 ;
        RECT  54.096 30.156 54.12 30.24 ;
    END
  END xa[45]
  PIN xa[46]
    DIRECTION OUTPUT ;
    USE SIGNAL ;
    PORT
      LAYER M5 ;
        RECT  54.24 30.156 54.264 30.24 ;
    END
  END xa[46]
  PIN xa[47]
    DIRECTION OUTPUT ;
    USE SIGNAL ;
    PORT
      LAYER M5 ;
        RECT  54.384 30.156 54.408 30.24 ;
    END
  END xa[47]
  PIN xa[48]
    DIRECTION OUTPUT ;
    USE SIGNAL ;
    PORT
      LAYER M5 ;
        RECT  54.528 30.156 54.552 30.24 ;
    END
  END xa[48]
  PIN xa[49]
    DIRECTION OUTPUT ;
    USE SIGNAL ;
    PORT
      LAYER M5 ;
        RECT  54.672 30.156 54.696 30.24 ;
    END
  END xa[49]
  PIN xa[4]
    DIRECTION OUTPUT ;
    USE SIGNAL ;
    PORT
      LAYER M5 ;
        RECT  48.192 30.156 48.216 30.24 ;
    END
  END xa[4]
  PIN xa[50]
    DIRECTION OUTPUT ;
    USE SIGNAL ;
    PORT
      LAYER M5 ;
        RECT  54.816 30.156 54.84 30.24 ;
    END
  END xa[50]
  PIN xa[51]
    DIRECTION OUTPUT ;
    USE SIGNAL ;
    PORT
      LAYER M5 ;
        RECT  54.96 30.156 54.984 30.24 ;
    END
  END xa[51]
  PIN xa[52]
    DIRECTION OUTPUT ;
    USE SIGNAL ;
    PORT
      LAYER M5 ;
        RECT  55.104 30.156 55.128 30.24 ;
    END
  END xa[52]
  PIN xa[53]
    DIRECTION OUTPUT ;
    USE SIGNAL ;
    PORT
      LAYER M5 ;
        RECT  55.248 30.156 55.272 30.24 ;
    END
  END xa[53]
  PIN xa[54]
    DIRECTION OUTPUT ;
    USE SIGNAL ;
    PORT
      LAYER M5 ;
        RECT  55.392 30.156 55.416 30.24 ;
    END
  END xa[54]
  PIN xa[55]
    DIRECTION OUTPUT ;
    USE SIGNAL ;
    PORT
      LAYER M5 ;
        RECT  55.536 30.156 55.56 30.24 ;
    END
  END xa[55]
  PIN xa[56]
    DIRECTION OUTPUT ;
    USE SIGNAL ;
    PORT
      LAYER M5 ;
        RECT  55.68 30.156 55.704 30.24 ;
    END
  END xa[56]
  PIN xa[57]
    DIRECTION OUTPUT ;
    USE SIGNAL ;
    PORT
      LAYER M5 ;
        RECT  55.824 30.156 55.848 30.24 ;
    END
  END xa[57]
  PIN xa[58]
    DIRECTION OUTPUT ;
    USE SIGNAL ;
    PORT
      LAYER M5 ;
        RECT  55.968 30.156 55.992 30.24 ;
    END
  END xa[58]
  PIN xa[59]
    DIRECTION OUTPUT ;
    USE SIGNAL ;
    PORT
      LAYER M5 ;
        RECT  56.112 30.156 56.136 30.24 ;
    END
  END xa[59]
  PIN xa[5]
    DIRECTION OUTPUT ;
    USE SIGNAL ;
    PORT
      LAYER M5 ;
        RECT  48.336 30.156 48.36 30.24 ;
    END
  END xa[5]
  PIN xa[60]
    DIRECTION OUTPUT ;
    USE SIGNAL ;
    PORT
      LAYER M5 ;
        RECT  56.256 30.156 56.28 30.24 ;
    END
  END xa[60]
  PIN xa[61]
    DIRECTION OUTPUT ;
    USE SIGNAL ;
    PORT
      LAYER M5 ;
        RECT  56.4 30.156 56.424 30.24 ;
    END
  END xa[61]
  PIN xa[62]
    DIRECTION OUTPUT ;
    USE SIGNAL ;
    PORT
      LAYER M5 ;
        RECT  56.544 30.156 56.568 30.24 ;
    END
  END xa[62]
  PIN xa[63]
    DIRECTION OUTPUT ;
    USE SIGNAL ;
    PORT
      LAYER M5 ;
        RECT  56.688 30.156 56.712 30.24 ;
    END
  END xa[63]
  PIN xa[64]
    DIRECTION OUTPUT ;
    USE SIGNAL ;
    PORT
      LAYER M5 ;
        RECT  56.832 30.156 56.856 30.24 ;
    END
  END xa[64]
  PIN xa[65]
    DIRECTION OUTPUT ;
    USE SIGNAL ;
    PORT
      LAYER M5 ;
        RECT  56.976 30.156 57 30.24 ;
    END
  END xa[65]
  PIN xa[66]
    DIRECTION OUTPUT ;
    USE SIGNAL ;
    PORT
      LAYER M5 ;
        RECT  57.12 30.156 57.144 30.24 ;
    END
  END xa[66]
  PIN xa[67]
    DIRECTION OUTPUT ;
    USE SIGNAL ;
    PORT
      LAYER M5 ;
        RECT  57.264 30.156 57.288 30.24 ;
    END
  END xa[67]
  PIN xa[68]
    DIRECTION OUTPUT ;
    USE SIGNAL ;
    PORT
      LAYER M5 ;
        RECT  57.408 30.156 57.432 30.24 ;
    END
  END xa[68]
  PIN xa[69]
    DIRECTION OUTPUT ;
    USE SIGNAL ;
    PORT
      LAYER M5 ;
        RECT  57.552 30.156 57.576 30.24 ;
    END
  END xa[69]
  PIN xa[6]
    DIRECTION OUTPUT ;
    USE SIGNAL ;
    PORT
      LAYER M5 ;
        RECT  48.48 30.156 48.504 30.24 ;
    END
  END xa[6]
  PIN xa[70]
    DIRECTION OUTPUT ;
    USE SIGNAL ;
    PORT
      LAYER M5 ;
        RECT  57.696 30.156 57.72 30.24 ;
    END
  END xa[70]
  PIN xa[71]
    DIRECTION OUTPUT ;
    USE SIGNAL ;
    PORT
      LAYER M5 ;
        RECT  57.84 30.156 57.864 30.24 ;
    END
  END xa[71]
  PIN xa[72]
    DIRECTION OUTPUT ;
    USE SIGNAL ;
    PORT
      LAYER M5 ;
        RECT  57.984 30.156 58.008 30.24 ;
    END
  END xa[72]
  PIN xa[73]
    DIRECTION OUTPUT ;
    USE SIGNAL ;
    PORT
      LAYER M5 ;
        RECT  58.128 30.156 58.152 30.24 ;
    END
  END xa[73]
  PIN xa[74]
    DIRECTION OUTPUT ;
    USE SIGNAL ;
    PORT
      LAYER M5 ;
        RECT  58.272 30.156 58.296 30.24 ;
    END
  END xa[74]
  PIN xa[75]
    DIRECTION OUTPUT ;
    USE SIGNAL ;
    PORT
      LAYER M5 ;
        RECT  58.416 30.156 58.44 30.24 ;
    END
  END xa[75]
  PIN xa[76]
    DIRECTION OUTPUT ;
    USE SIGNAL ;
    PORT
      LAYER M5 ;
        RECT  58.56 30.156 58.584 30.24 ;
    END
  END xa[76]
  PIN xa[77]
    DIRECTION OUTPUT ;
    USE SIGNAL ;
    PORT
      LAYER M5 ;
        RECT  58.704 30.156 58.728 30.24 ;
    END
  END xa[77]
  PIN xa[78]
    DIRECTION OUTPUT ;
    USE SIGNAL ;
    PORT
      LAYER M5 ;
        RECT  58.848 30.156 58.872 30.24 ;
    END
  END xa[78]
  PIN xa[79]
    DIRECTION OUTPUT ;
    USE SIGNAL ;
    PORT
      LAYER M5 ;
        RECT  58.992 30.156 59.016 30.24 ;
    END
  END xa[79]
  PIN xa[7]
    DIRECTION OUTPUT ;
    USE SIGNAL ;
    PORT
      LAYER M5 ;
        RECT  48.624 30.156 48.648 30.24 ;
    END
  END xa[7]
  PIN xa[80]
    DIRECTION OUTPUT ;
    USE SIGNAL ;
    PORT
      LAYER M5 ;
        RECT  59.136 30.156 59.16 30.24 ;
    END
  END xa[80]
  PIN xa[81]
    DIRECTION OUTPUT ;
    USE SIGNAL ;
    PORT
      LAYER M5 ;
        RECT  59.28 30.156 59.304 30.24 ;
    END
  END xa[81]
  PIN xa[82]
    DIRECTION OUTPUT ;
    USE SIGNAL ;
    PORT
      LAYER M5 ;
        RECT  59.424 30.156 59.448 30.24 ;
    END
  END xa[82]
  PIN xa[83]
    DIRECTION OUTPUT ;
    USE SIGNAL ;
    PORT
      LAYER M5 ;
        RECT  59.568 30.156 59.592 30.24 ;
    END
  END xa[83]
  PIN xa[84]
    DIRECTION OUTPUT ;
    USE SIGNAL ;
    PORT
      LAYER M5 ;
        RECT  59.712 30.156 59.736 30.24 ;
    END
  END xa[84]
  PIN xa[85]
    DIRECTION OUTPUT ;
    USE SIGNAL ;
    PORT
      LAYER M5 ;
        RECT  59.856 30.156 59.88 30.24 ;
    END
  END xa[85]
  PIN xa[86]
    DIRECTION OUTPUT ;
    USE SIGNAL ;
    PORT
      LAYER M5 ;
        RECT  60 30.156 60.024 30.24 ;
    END
  END xa[86]
  PIN xa[87]
    DIRECTION OUTPUT ;
    USE SIGNAL ;
    PORT
      LAYER M5 ;
        RECT  60.144 30.156 60.168 30.24 ;
    END
  END xa[87]
  PIN xa[88]
    DIRECTION OUTPUT ;
    USE SIGNAL ;
    PORT
      LAYER M5 ;
        RECT  60.288 30.156 60.312 30.24 ;
    END
  END xa[88]
  PIN xa[89]
    DIRECTION OUTPUT ;
    USE SIGNAL ;
    PORT
      LAYER M5 ;
        RECT  60.432 30.156 60.456 30.24 ;
    END
  END xa[89]
  PIN xa[8]
    DIRECTION OUTPUT ;
    USE SIGNAL ;
    PORT
      LAYER M5 ;
        RECT  48.768 30.156 48.792 30.24 ;
    END
  END xa[8]
  PIN xa[90]
    DIRECTION OUTPUT ;
    USE SIGNAL ;
    PORT
      LAYER M5 ;
        RECT  60.576 30.156 60.6 30.24 ;
    END
  END xa[90]
  PIN xa[91]
    DIRECTION OUTPUT ;
    USE SIGNAL ;
    PORT
      LAYER M5 ;
        RECT  60.72 30.156 60.744 30.24 ;
    END
  END xa[91]
  PIN xa[92]
    DIRECTION OUTPUT ;
    USE SIGNAL ;
    PORT
      LAYER M5 ;
        RECT  60.864 30.156 60.888 30.24 ;
    END
  END xa[92]
  PIN xa[93]
    DIRECTION OUTPUT ;
    USE SIGNAL ;
    PORT
      LAYER M5 ;
        RECT  61.008 30.156 61.032 30.24 ;
    END
  END xa[93]
  PIN xa[94]
    DIRECTION OUTPUT ;
    USE SIGNAL ;
    PORT
      LAYER M5 ;
        RECT  61.152 30.156 61.176 30.24 ;
    END
  END xa[94]
  PIN xa[95]
    DIRECTION OUTPUT ;
    USE SIGNAL ;
    PORT
      LAYER M5 ;
        RECT  61.296 30.156 61.32 30.24 ;
    END
  END xa[95]
  PIN xa[96]
    DIRECTION OUTPUT ;
    USE SIGNAL ;
    PORT
      LAYER M5 ;
        RECT  61.44 30.156 61.464 30.24 ;
    END
  END xa[96]
  PIN xa[97]
    DIRECTION OUTPUT ;
    USE SIGNAL ;
    PORT
      LAYER M5 ;
        RECT  61.584 30.156 61.608 30.24 ;
    END
  END xa[97]
  PIN xa[98]
    DIRECTION OUTPUT ;
    USE SIGNAL ;
    PORT
      LAYER M5 ;
        RECT  61.728 30.156 61.752 30.24 ;
    END
  END xa[98]
  PIN xa[99]
    DIRECTION OUTPUT ;
    USE SIGNAL ;
    PORT
      LAYER M5 ;
        RECT  61.872 30.156 61.896 30.24 ;
    END
  END xa[99]
  PIN xa[9]
    DIRECTION OUTPUT ;
    USE SIGNAL ;
    PORT
      LAYER M5 ;
        RECT  48.912 30.156 48.936 30.24 ;
    END
  END xa[9]
  PIN xai[0]
    DIRECTION INPUT ;
    USE SIGNAL ;
    PORT
      LAYER M5 ;
        RECT  131.424 0 131.448 0.084 ;
    END
  END xai[0]
  PIN xai[100]
    DIRECTION INPUT ;
    USE SIGNAL ;
    PORT
      LAYER M5 ;
        RECT  145.824 0 145.848 0.084 ;
    END
  END xai[100]
  PIN xai[101]
    DIRECTION INPUT ;
    USE SIGNAL ;
    PORT
      LAYER M5 ;
        RECT  145.968 0 145.992 0.084 ;
    END
  END xai[101]
  PIN xai[102]
    DIRECTION INPUT ;
    USE SIGNAL ;
    PORT
      LAYER M5 ;
        RECT  146.112 0 146.136 0.084 ;
    END
  END xai[102]
  PIN xai[103]
    DIRECTION INPUT ;
    USE SIGNAL ;
    PORT
      LAYER M5 ;
        RECT  146.256 0 146.28 0.084 ;
    END
  END xai[103]
  PIN xai[104]
    DIRECTION INPUT ;
    USE SIGNAL ;
    PORT
      LAYER M5 ;
        RECT  146.4 0 146.424 0.084 ;
    END
  END xai[104]
  PIN xai[105]
    DIRECTION INPUT ;
    USE SIGNAL ;
    PORT
      LAYER M5 ;
        RECT  146.544 0 146.568 0.084 ;
    END
  END xai[105]
  PIN xai[106]
    DIRECTION INPUT ;
    USE SIGNAL ;
    PORT
      LAYER M5 ;
        RECT  146.688 0 146.712 0.084 ;
    END
  END xai[106]
  PIN xai[107]
    DIRECTION INPUT ;
    USE SIGNAL ;
    PORT
      LAYER M5 ;
        RECT  146.832 0 146.856 0.084 ;
    END
  END xai[107]
  PIN xai[108]
    DIRECTION INPUT ;
    USE SIGNAL ;
    PORT
      LAYER M5 ;
        RECT  146.976 0 147 0.084 ;
    END
  END xai[108]
  PIN xai[109]
    DIRECTION INPUT ;
    USE SIGNAL ;
    PORT
      LAYER M5 ;
        RECT  147.12 0 147.144 0.084 ;
    END
  END xai[109]
  PIN xai[10]
    DIRECTION INPUT ;
    USE SIGNAL ;
    PORT
      LAYER M5 ;
        RECT  132.864 0 132.888 0.084 ;
    END
  END xai[10]
  PIN xai[110]
    DIRECTION INPUT ;
    USE SIGNAL ;
    PORT
      LAYER M5 ;
        RECT  147.264 0 147.288 0.084 ;
    END
  END xai[110]
  PIN xai[111]
    DIRECTION INPUT ;
    USE SIGNAL ;
    PORT
      LAYER M5 ;
        RECT  147.408 0 147.432 0.084 ;
    END
  END xai[111]
  PIN xai[112]
    DIRECTION INPUT ;
    USE SIGNAL ;
    PORT
      LAYER M5 ;
        RECT  147.552 0 147.576 0.084 ;
    END
  END xai[112]
  PIN xai[113]
    DIRECTION INPUT ;
    USE SIGNAL ;
    PORT
      LAYER M5 ;
        RECT  147.696 0 147.72 0.084 ;
    END
  END xai[113]
  PIN xai[114]
    DIRECTION INPUT ;
    USE SIGNAL ;
    PORT
      LAYER M5 ;
        RECT  147.84 0 147.864 0.084 ;
    END
  END xai[114]
  PIN xai[115]
    DIRECTION INPUT ;
    USE SIGNAL ;
    PORT
      LAYER M5 ;
        RECT  147.984 0 148.008 0.084 ;
    END
  END xai[115]
  PIN xai[116]
    DIRECTION INPUT ;
    USE SIGNAL ;
    PORT
      LAYER M5 ;
        RECT  148.128 0 148.152 0.084 ;
    END
  END xai[116]
  PIN xai[117]
    DIRECTION INPUT ;
    USE SIGNAL ;
    PORT
      LAYER M5 ;
        RECT  148.272 0 148.296 0.084 ;
    END
  END xai[117]
  PIN xai[118]
    DIRECTION INPUT ;
    USE SIGNAL ;
    PORT
      LAYER M5 ;
        RECT  148.416 0 148.44 0.084 ;
    END
  END xai[118]
  PIN xai[119]
    DIRECTION INPUT ;
    USE SIGNAL ;
    PORT
      LAYER M5 ;
        RECT  148.56 0 148.584 0.084 ;
    END
  END xai[119]
  PIN xai[11]
    DIRECTION INPUT ;
    USE SIGNAL ;
    PORT
      LAYER M5 ;
        RECT  133.008 0 133.032 0.084 ;
    END
  END xai[11]
  PIN xai[120]
    DIRECTION INPUT ;
    USE SIGNAL ;
    PORT
      LAYER M5 ;
        RECT  148.704 0 148.728 0.084 ;
    END
  END xai[120]
  PIN xai[121]
    DIRECTION INPUT ;
    USE SIGNAL ;
    PORT
      LAYER M5 ;
        RECT  148.848 0 148.872 0.084 ;
    END
  END xai[121]
  PIN xai[122]
    DIRECTION INPUT ;
    USE SIGNAL ;
    PORT
      LAYER M5 ;
        RECT  148.992 0 149.016 0.084 ;
    END
  END xai[122]
  PIN xai[123]
    DIRECTION INPUT ;
    USE SIGNAL ;
    PORT
      LAYER M5 ;
        RECT  149.136 0 149.16 0.084 ;
    END
  END xai[123]
  PIN xai[124]
    DIRECTION INPUT ;
    USE SIGNAL ;
    PORT
      LAYER M5 ;
        RECT  149.28 0 149.304 0.084 ;
    END
  END xai[124]
  PIN xai[125]
    DIRECTION INPUT ;
    USE SIGNAL ;
    PORT
      LAYER M5 ;
        RECT  149.424 0 149.448 0.084 ;
    END
  END xai[125]
  PIN xai[126]
    DIRECTION INPUT ;
    USE SIGNAL ;
    PORT
      LAYER M5 ;
        RECT  149.568 0 149.592 0.084 ;
    END
  END xai[126]
  PIN xai[127]
    DIRECTION INPUT ;
    USE SIGNAL ;
    PORT
      LAYER M5 ;
        RECT  149.712 0 149.736 0.084 ;
    END
  END xai[127]
  PIN xai[128]
    DIRECTION INPUT ;
    USE SIGNAL ;
    PORT
      LAYER M5 ;
        RECT  149.856 0 149.88 0.084 ;
    END
  END xai[128]
  PIN xai[129]
    DIRECTION INPUT ;
    USE SIGNAL ;
    PORT
      LAYER M5 ;
        RECT  150 0 150.024 0.084 ;
    END
  END xai[129]
  PIN xai[12]
    DIRECTION INPUT ;
    USE SIGNAL ;
    PORT
      LAYER M5 ;
        RECT  133.152 0 133.176 0.084 ;
    END
  END xai[12]
  PIN xai[130]
    DIRECTION INPUT ;
    USE SIGNAL ;
    PORT
      LAYER M5 ;
        RECT  150.144 0 150.168 0.084 ;
    END
  END xai[130]
  PIN xai[131]
    DIRECTION INPUT ;
    USE SIGNAL ;
    PORT
      LAYER M5 ;
        RECT  150.288 0 150.312 0.084 ;
    END
  END xai[131]
  PIN xai[132]
    DIRECTION INPUT ;
    USE SIGNAL ;
    PORT
      LAYER M5 ;
        RECT  150.432 0 150.456 0.084 ;
    END
  END xai[132]
  PIN xai[133]
    DIRECTION INPUT ;
    USE SIGNAL ;
    PORT
      LAYER M5 ;
        RECT  150.576 0 150.6 0.084 ;
    END
  END xai[133]
  PIN xai[134]
    DIRECTION INPUT ;
    USE SIGNAL ;
    PORT
      LAYER M5 ;
        RECT  150.72 0 150.744 0.084 ;
    END
  END xai[134]
  PIN xai[135]
    DIRECTION INPUT ;
    USE SIGNAL ;
    PORT
      LAYER M5 ;
        RECT  150.864 0 150.888 0.084 ;
    END
  END xai[135]
  PIN xai[136]
    DIRECTION INPUT ;
    USE SIGNAL ;
    PORT
      LAYER M5 ;
        RECT  151.008 0 151.032 0.084 ;
    END
  END xai[136]
  PIN xai[137]
    DIRECTION INPUT ;
    USE SIGNAL ;
    PORT
      LAYER M5 ;
        RECT  151.152 0 151.176 0.084 ;
    END
  END xai[137]
  PIN xai[138]
    DIRECTION INPUT ;
    USE SIGNAL ;
    PORT
      LAYER M5 ;
        RECT  151.296 0 151.32 0.084 ;
    END
  END xai[138]
  PIN xai[139]
    DIRECTION INPUT ;
    USE SIGNAL ;
    PORT
      LAYER M5 ;
        RECT  151.44 0 151.464 0.084 ;
    END
  END xai[139]
  PIN xai[13]
    DIRECTION INPUT ;
    USE SIGNAL ;
    PORT
      LAYER M5 ;
        RECT  133.296 0 133.32 0.084 ;
    END
  END xai[13]
  PIN xai[140]
    DIRECTION INPUT ;
    USE SIGNAL ;
    PORT
      LAYER M5 ;
        RECT  151.584 0 151.608 0.084 ;
    END
  END xai[140]
  PIN xai[141]
    DIRECTION INPUT ;
    USE SIGNAL ;
    PORT
      LAYER M5 ;
        RECT  151.728 0 151.752 0.084 ;
    END
  END xai[141]
  PIN xai[142]
    DIRECTION INPUT ;
    USE SIGNAL ;
    PORT
      LAYER M5 ;
        RECT  151.872 0 151.896 0.084 ;
    END
  END xai[142]
  PIN xai[143]
    DIRECTION INPUT ;
    USE SIGNAL ;
    PORT
      LAYER M5 ;
        RECT  152.016 0 152.04 0.084 ;
    END
  END xai[143]
  PIN xai[144]
    DIRECTION INPUT ;
    USE SIGNAL ;
    PORT
      LAYER M5 ;
        RECT  152.16 0 152.184 0.084 ;
    END
  END xai[144]
  PIN xai[145]
    DIRECTION INPUT ;
    USE SIGNAL ;
    PORT
      LAYER M5 ;
        RECT  152.304 0 152.328 0.084 ;
    END
  END xai[145]
  PIN xai[146]
    DIRECTION INPUT ;
    USE SIGNAL ;
    PORT
      LAYER M5 ;
        RECT  152.448 0 152.472 0.084 ;
    END
  END xai[146]
  PIN xai[147]
    DIRECTION INPUT ;
    USE SIGNAL ;
    PORT
      LAYER M5 ;
        RECT  152.592 0 152.616 0.084 ;
    END
  END xai[147]
  PIN xai[148]
    DIRECTION INPUT ;
    USE SIGNAL ;
    PORT
      LAYER M5 ;
        RECT  152.736 0 152.76 0.084 ;
    END
  END xai[148]
  PIN xai[149]
    DIRECTION INPUT ;
    USE SIGNAL ;
    PORT
      LAYER M5 ;
        RECT  152.88 0 152.904 0.084 ;
    END
  END xai[149]
  PIN xai[14]
    DIRECTION INPUT ;
    USE SIGNAL ;
    PORT
      LAYER M5 ;
        RECT  133.44 0 133.464 0.084 ;
    END
  END xai[14]
  PIN xai[150]
    DIRECTION INPUT ;
    USE SIGNAL ;
    PORT
      LAYER M5 ;
        RECT  153.024 0 153.048 0.084 ;
    END
  END xai[150]
  PIN xai[151]
    DIRECTION INPUT ;
    USE SIGNAL ;
    PORT
      LAYER M5 ;
        RECT  153.168 0 153.192 0.084 ;
    END
  END xai[151]
  PIN xai[152]
    DIRECTION INPUT ;
    USE SIGNAL ;
    PORT
      LAYER M5 ;
        RECT  153.312 0 153.336 0.084 ;
    END
  END xai[152]
  PIN xai[153]
    DIRECTION INPUT ;
    USE SIGNAL ;
    PORT
      LAYER M5 ;
        RECT  153.456 0 153.48 0.084 ;
    END
  END xai[153]
  PIN xai[154]
    DIRECTION INPUT ;
    USE SIGNAL ;
    PORT
      LAYER M5 ;
        RECT  153.6 0 153.624 0.084 ;
    END
  END xai[154]
  PIN xai[155]
    DIRECTION INPUT ;
    USE SIGNAL ;
    PORT
      LAYER M5 ;
        RECT  153.744 0 153.768 0.084 ;
    END
  END xai[155]
  PIN xai[156]
    DIRECTION INPUT ;
    USE SIGNAL ;
    PORT
      LAYER M5 ;
        RECT  153.888 0 153.912 0.084 ;
    END
  END xai[156]
  PIN xai[157]
    DIRECTION INPUT ;
    USE SIGNAL ;
    PORT
      LAYER M5 ;
        RECT  154.032 0 154.056 0.084 ;
    END
  END xai[157]
  PIN xai[158]
    DIRECTION INPUT ;
    USE SIGNAL ;
    PORT
      LAYER M5 ;
        RECT  154.176 0 154.2 0.084 ;
    END
  END xai[158]
  PIN xai[159]
    DIRECTION INPUT ;
    USE SIGNAL ;
    PORT
      LAYER M5 ;
        RECT  154.32 0 154.344 0.084 ;
    END
  END xai[159]
  PIN xai[15]
    DIRECTION INPUT ;
    USE SIGNAL ;
    PORT
      LAYER M5 ;
        RECT  133.584 0 133.608 0.084 ;
    END
  END xai[15]
  PIN xai[160]
    DIRECTION INPUT ;
    USE SIGNAL ;
    PORT
      LAYER M5 ;
        RECT  154.464 0 154.488 0.084 ;
    END
  END xai[160]
  PIN xai[161]
    DIRECTION INPUT ;
    USE SIGNAL ;
    PORT
      LAYER M5 ;
        RECT  154.608 0 154.632 0.084 ;
    END
  END xai[161]
  PIN xai[162]
    DIRECTION INPUT ;
    USE SIGNAL ;
    PORT
      LAYER M5 ;
        RECT  154.752 0 154.776 0.084 ;
    END
  END xai[162]
  PIN xai[163]
    DIRECTION INPUT ;
    USE SIGNAL ;
    PORT
      LAYER M5 ;
        RECT  154.896 0 154.92 0.084 ;
    END
  END xai[163]
  PIN xai[164]
    DIRECTION INPUT ;
    USE SIGNAL ;
    PORT
      LAYER M5 ;
        RECT  155.04 0 155.064 0.084 ;
    END
  END xai[164]
  PIN xai[165]
    DIRECTION INPUT ;
    USE SIGNAL ;
    PORT
      LAYER M5 ;
        RECT  155.184 0 155.208 0.084 ;
    END
  END xai[165]
  PIN xai[166]
    DIRECTION INPUT ;
    USE SIGNAL ;
    PORT
      LAYER M5 ;
        RECT  155.328 0 155.352 0.084 ;
    END
  END xai[166]
  PIN xai[167]
    DIRECTION INPUT ;
    USE SIGNAL ;
    PORT
      LAYER M5 ;
        RECT  155.472 0 155.496 0.084 ;
    END
  END xai[167]
  PIN xai[168]
    DIRECTION INPUT ;
    USE SIGNAL ;
    PORT
      LAYER M5 ;
        RECT  155.616 0 155.64 0.084 ;
    END
  END xai[168]
  PIN xai[169]
    DIRECTION INPUT ;
    USE SIGNAL ;
    PORT
      LAYER M5 ;
        RECT  155.76 0 155.784 0.084 ;
    END
  END xai[169]
  PIN xai[16]
    DIRECTION INPUT ;
    USE SIGNAL ;
    PORT
      LAYER M5 ;
        RECT  133.728 0 133.752 0.084 ;
    END
  END xai[16]
  PIN xai[170]
    DIRECTION INPUT ;
    USE SIGNAL ;
    PORT
      LAYER M5 ;
        RECT  155.904 0 155.928 0.084 ;
    END
  END xai[170]
  PIN xai[171]
    DIRECTION INPUT ;
    USE SIGNAL ;
    PORT
      LAYER M5 ;
        RECT  156.048 0 156.072 0.084 ;
    END
  END xai[171]
  PIN xai[172]
    DIRECTION INPUT ;
    USE SIGNAL ;
    PORT
      LAYER M5 ;
        RECT  156.192 0 156.216 0.084 ;
    END
  END xai[172]
  PIN xai[173]
    DIRECTION INPUT ;
    USE SIGNAL ;
    PORT
      LAYER M5 ;
        RECT  156.336 0 156.36 0.084 ;
    END
  END xai[173]
  PIN xai[174]
    DIRECTION INPUT ;
    USE SIGNAL ;
    PORT
      LAYER M5 ;
        RECT  156.48 0 156.504 0.084 ;
    END
  END xai[174]
  PIN xai[175]
    DIRECTION INPUT ;
    USE SIGNAL ;
    PORT
      LAYER M5 ;
        RECT  156.624 0 156.648 0.084 ;
    END
  END xai[175]
  PIN xai[176]
    DIRECTION INPUT ;
    USE SIGNAL ;
    PORT
      LAYER M5 ;
        RECT  156.768 0 156.792 0.084 ;
    END
  END xai[176]
  PIN xai[177]
    DIRECTION INPUT ;
    USE SIGNAL ;
    PORT
      LAYER M5 ;
        RECT  156.912 0 156.936 0.084 ;
    END
  END xai[177]
  PIN xai[178]
    DIRECTION INPUT ;
    USE SIGNAL ;
    PORT
      LAYER M5 ;
        RECT  157.056 0 157.08 0.084 ;
    END
  END xai[178]
  PIN xai[179]
    DIRECTION INPUT ;
    USE SIGNAL ;
    PORT
      LAYER M5 ;
        RECT  157.2 0 157.224 0.084 ;
    END
  END xai[179]
  PIN xai[17]
    DIRECTION INPUT ;
    USE SIGNAL ;
    PORT
      LAYER M5 ;
        RECT  133.872 0 133.896 0.084 ;
    END
  END xai[17]
  PIN xai[180]
    DIRECTION INPUT ;
    USE SIGNAL ;
    PORT
      LAYER M5 ;
        RECT  157.344 0 157.368 0.084 ;
    END
  END xai[180]
  PIN xai[181]
    DIRECTION INPUT ;
    USE SIGNAL ;
    PORT
      LAYER M5 ;
        RECT  157.488 0 157.512 0.084 ;
    END
  END xai[181]
  PIN xai[182]
    DIRECTION INPUT ;
    USE SIGNAL ;
    PORT
      LAYER M5 ;
        RECT  157.632 0 157.656 0.084 ;
    END
  END xai[182]
  PIN xai[183]
    DIRECTION INPUT ;
    USE SIGNAL ;
    PORT
      LAYER M5 ;
        RECT  157.776 0 157.8 0.084 ;
    END
  END xai[183]
  PIN xai[184]
    DIRECTION INPUT ;
    USE SIGNAL ;
    PORT
      LAYER M5 ;
        RECT  157.92 0 157.944 0.084 ;
    END
  END xai[184]
  PIN xai[185]
    DIRECTION INPUT ;
    USE SIGNAL ;
    PORT
      LAYER M5 ;
        RECT  158.064 0 158.088 0.084 ;
    END
  END xai[185]
  PIN xai[186]
    DIRECTION INPUT ;
    USE SIGNAL ;
    PORT
      LAYER M5 ;
        RECT  158.208 0 158.232 0.084 ;
    END
  END xai[186]
  PIN xai[187]
    DIRECTION INPUT ;
    USE SIGNAL ;
    PORT
      LAYER M5 ;
        RECT  158.352 0 158.376 0.084 ;
    END
  END xai[187]
  PIN xai[188]
    DIRECTION INPUT ;
    USE SIGNAL ;
    PORT
      LAYER M5 ;
        RECT  158.496 0 158.52 0.084 ;
    END
  END xai[188]
  PIN xai[189]
    DIRECTION INPUT ;
    USE SIGNAL ;
    PORT
      LAYER M5 ;
        RECT  158.64 0 158.664 0.084 ;
    END
  END xai[189]
  PIN xai[18]
    DIRECTION INPUT ;
    USE SIGNAL ;
    PORT
      LAYER M5 ;
        RECT  134.016 0 134.04 0.084 ;
    END
  END xai[18]
  PIN xai[190]
    DIRECTION INPUT ;
    USE SIGNAL ;
    PORT
      LAYER M5 ;
        RECT  158.784 0 158.808 0.084 ;
    END
  END xai[190]
  PIN xai[191]
    DIRECTION INPUT ;
    USE SIGNAL ;
    PORT
      LAYER M5 ;
        RECT  158.928 0 158.952 0.084 ;
    END
  END xai[191]
  PIN xai[192]
    DIRECTION INPUT ;
    USE SIGNAL ;
    PORT
      LAYER M5 ;
        RECT  159.072 0 159.096 0.084 ;
    END
  END xai[192]
  PIN xai[193]
    DIRECTION INPUT ;
    USE SIGNAL ;
    PORT
      LAYER M5 ;
        RECT  159.216 0 159.24 0.084 ;
    END
  END xai[193]
  PIN xai[194]
    DIRECTION INPUT ;
    USE SIGNAL ;
    PORT
      LAYER M5 ;
        RECT  159.36 0 159.384 0.084 ;
    END
  END xai[194]
  PIN xai[195]
    DIRECTION INPUT ;
    USE SIGNAL ;
    PORT
      LAYER M5 ;
        RECT  159.504 0 159.528 0.084 ;
    END
  END xai[195]
  PIN xai[196]
    DIRECTION INPUT ;
    USE SIGNAL ;
    PORT
      LAYER M5 ;
        RECT  159.648 0 159.672 0.084 ;
    END
  END xai[196]
  PIN xai[197]
    DIRECTION INPUT ;
    USE SIGNAL ;
    PORT
      LAYER M5 ;
        RECT  159.792 0 159.816 0.084 ;
    END
  END xai[197]
  PIN xai[198]
    DIRECTION INPUT ;
    USE SIGNAL ;
    PORT
      LAYER M5 ;
        RECT  159.936 0 159.96 0.084 ;
    END
  END xai[198]
  PIN xai[199]
    DIRECTION INPUT ;
    USE SIGNAL ;
    PORT
      LAYER M5 ;
        RECT  160.08 0 160.104 0.084 ;
    END
  END xai[199]
  PIN xai[19]
    DIRECTION INPUT ;
    USE SIGNAL ;
    PORT
      LAYER M5 ;
        RECT  134.16 0 134.184 0.084 ;
    END
  END xai[19]
  PIN xai[1]
    DIRECTION INPUT ;
    USE SIGNAL ;
    PORT
      LAYER M5 ;
        RECT  131.568 0 131.592 0.084 ;
    END
  END xai[1]
  PIN xai[200]
    DIRECTION INPUT ;
    USE SIGNAL ;
    PORT
      LAYER M5 ;
        RECT  160.224 0 160.248 0.084 ;
    END
  END xai[200]
  PIN xai[201]
    DIRECTION INPUT ;
    USE SIGNAL ;
    PORT
      LAYER M5 ;
        RECT  160.368 0 160.392 0.084 ;
    END
  END xai[201]
  PIN xai[202]
    DIRECTION INPUT ;
    USE SIGNAL ;
    PORT
      LAYER M5 ;
        RECT  160.512 0 160.536 0.084 ;
    END
  END xai[202]
  PIN xai[203]
    DIRECTION INPUT ;
    USE SIGNAL ;
    PORT
      LAYER M5 ;
        RECT  160.656 0 160.68 0.084 ;
    END
  END xai[203]
  PIN xai[204]
    DIRECTION INPUT ;
    USE SIGNAL ;
    PORT
      LAYER M5 ;
        RECT  160.8 0 160.824 0.084 ;
    END
  END xai[204]
  PIN xai[205]
    DIRECTION INPUT ;
    USE SIGNAL ;
    PORT
      LAYER M5 ;
        RECT  160.944 0 160.968 0.084 ;
    END
  END xai[205]
  PIN xai[206]
    DIRECTION INPUT ;
    USE SIGNAL ;
    PORT
      LAYER M5 ;
        RECT  161.088 0 161.112 0.084 ;
    END
  END xai[206]
  PIN xai[207]
    DIRECTION INPUT ;
    USE SIGNAL ;
    PORT
      LAYER M5 ;
        RECT  161.232 0 161.256 0.084 ;
    END
  END xai[207]
  PIN xai[208]
    DIRECTION INPUT ;
    USE SIGNAL ;
    PORT
      LAYER M5 ;
        RECT  161.376 0 161.4 0.084 ;
    END
  END xai[208]
  PIN xai[209]
    DIRECTION INPUT ;
    USE SIGNAL ;
    PORT
      LAYER M5 ;
        RECT  161.52 0 161.544 0.084 ;
    END
  END xai[209]
  PIN xai[20]
    DIRECTION INPUT ;
    USE SIGNAL ;
    PORT
      LAYER M5 ;
        RECT  134.304 0 134.328 0.084 ;
    END
  END xai[20]
  PIN xai[210]
    DIRECTION INPUT ;
    USE SIGNAL ;
    PORT
      LAYER M5 ;
        RECT  161.664 0 161.688 0.084 ;
    END
  END xai[210]
  PIN xai[211]
    DIRECTION INPUT ;
    USE SIGNAL ;
    PORT
      LAYER M5 ;
        RECT  161.808 0 161.832 0.084 ;
    END
  END xai[211]
  PIN xai[212]
    DIRECTION INPUT ;
    USE SIGNAL ;
    PORT
      LAYER M5 ;
        RECT  161.952 0 161.976 0.084 ;
    END
  END xai[212]
  PIN xai[213]
    DIRECTION INPUT ;
    USE SIGNAL ;
    PORT
      LAYER M5 ;
        RECT  162.096 0 162.12 0.084 ;
    END
  END xai[213]
  PIN xai[214]
    DIRECTION INPUT ;
    USE SIGNAL ;
    PORT
      LAYER M5 ;
        RECT  162.24 0 162.264 0.084 ;
    END
  END xai[214]
  PIN xai[215]
    DIRECTION INPUT ;
    USE SIGNAL ;
    PORT
      LAYER M5 ;
        RECT  162.384 0 162.408 0.084 ;
    END
  END xai[215]
  PIN xai[216]
    DIRECTION INPUT ;
    USE SIGNAL ;
    PORT
      LAYER M5 ;
        RECT  162.528 0 162.552 0.084 ;
    END
  END xai[216]
  PIN xai[217]
    DIRECTION INPUT ;
    USE SIGNAL ;
    PORT
      LAYER M5 ;
        RECT  162.672 0 162.696 0.084 ;
    END
  END xai[217]
  PIN xai[218]
    DIRECTION INPUT ;
    USE SIGNAL ;
    PORT
      LAYER M5 ;
        RECT  162.816 0 162.84 0.084 ;
    END
  END xai[218]
  PIN xai[219]
    DIRECTION INPUT ;
    USE SIGNAL ;
    PORT
      LAYER M5 ;
        RECT  162.96 0 162.984 0.084 ;
    END
  END xai[219]
  PIN xai[21]
    DIRECTION INPUT ;
    USE SIGNAL ;
    PORT
      LAYER M5 ;
        RECT  134.448 0 134.472 0.084 ;
    END
  END xai[21]
  PIN xai[220]
    DIRECTION INPUT ;
    USE SIGNAL ;
    PORT
      LAYER M5 ;
        RECT  163.104 0 163.128 0.084 ;
    END
  END xai[220]
  PIN xai[221]
    DIRECTION INPUT ;
    USE SIGNAL ;
    PORT
      LAYER M5 ;
        RECT  163.248 0 163.272 0.084 ;
    END
  END xai[221]
  PIN xai[222]
    DIRECTION INPUT ;
    USE SIGNAL ;
    PORT
      LAYER M5 ;
        RECT  163.392 0 163.416 0.084 ;
    END
  END xai[222]
  PIN xai[223]
    DIRECTION INPUT ;
    USE SIGNAL ;
    PORT
      LAYER M5 ;
        RECT  163.536 0 163.56 0.084 ;
    END
  END xai[223]
  PIN xai[224]
    DIRECTION INPUT ;
    USE SIGNAL ;
    PORT
      LAYER M5 ;
        RECT  163.68 0 163.704 0.084 ;
    END
  END xai[224]
  PIN xai[225]
    DIRECTION INPUT ;
    USE SIGNAL ;
    PORT
      LAYER M5 ;
        RECT  163.824 0 163.848 0.084 ;
    END
  END xai[225]
  PIN xai[226]
    DIRECTION INPUT ;
    USE SIGNAL ;
    PORT
      LAYER M5 ;
        RECT  163.968 0 163.992 0.084 ;
    END
  END xai[226]
  PIN xai[227]
    DIRECTION INPUT ;
    USE SIGNAL ;
    PORT
      LAYER M5 ;
        RECT  164.112 0 164.136 0.084 ;
    END
  END xai[227]
  PIN xai[228]
    DIRECTION INPUT ;
    USE SIGNAL ;
    PORT
      LAYER M5 ;
        RECT  164.256 0 164.28 0.084 ;
    END
  END xai[228]
  PIN xai[229]
    DIRECTION INPUT ;
    USE SIGNAL ;
    PORT
      LAYER M5 ;
        RECT  164.4 0 164.424 0.084 ;
    END
  END xai[229]
  PIN xai[22]
    DIRECTION INPUT ;
    USE SIGNAL ;
    PORT
      LAYER M5 ;
        RECT  134.592 0 134.616 0.084 ;
    END
  END xai[22]
  PIN xai[230]
    DIRECTION INPUT ;
    USE SIGNAL ;
    PORT
      LAYER M5 ;
        RECT  164.544 0 164.568 0.084 ;
    END
  END xai[230]
  PIN xai[231]
    DIRECTION INPUT ;
    USE SIGNAL ;
    PORT
      LAYER M5 ;
        RECT  164.688 0 164.712 0.084 ;
    END
  END xai[231]
  PIN xai[232]
    DIRECTION INPUT ;
    USE SIGNAL ;
    PORT
      LAYER M5 ;
        RECT  164.832 0 164.856 0.084 ;
    END
  END xai[232]
  PIN xai[233]
    DIRECTION INPUT ;
    USE SIGNAL ;
    PORT
      LAYER M5 ;
        RECT  164.976 0 165 0.084 ;
    END
  END xai[233]
  PIN xai[234]
    DIRECTION INPUT ;
    USE SIGNAL ;
    PORT
      LAYER M5 ;
        RECT  165.12 0 165.144 0.084 ;
    END
  END xai[234]
  PIN xai[235]
    DIRECTION INPUT ;
    USE SIGNAL ;
    PORT
      LAYER M5 ;
        RECT  165.264 0 165.288 0.084 ;
    END
  END xai[235]
  PIN xai[236]
    DIRECTION INPUT ;
    USE SIGNAL ;
    PORT
      LAYER M5 ;
        RECT  165.408 0 165.432 0.084 ;
    END
  END xai[236]
  PIN xai[237]
    DIRECTION INPUT ;
    USE SIGNAL ;
    PORT
      LAYER M5 ;
        RECT  165.552 0 165.576 0.084 ;
    END
  END xai[237]
  PIN xai[238]
    DIRECTION INPUT ;
    USE SIGNAL ;
    PORT
      LAYER M5 ;
        RECT  165.696 0 165.72 0.084 ;
    END
  END xai[238]
  PIN xai[239]
    DIRECTION INPUT ;
    USE SIGNAL ;
    PORT
      LAYER M5 ;
        RECT  165.84 0 165.864 0.084 ;
    END
  END xai[239]
  PIN xai[23]
    DIRECTION INPUT ;
    USE SIGNAL ;
    PORT
      LAYER M5 ;
        RECT  134.736 0 134.76 0.084 ;
    END
  END xai[23]
  PIN xai[240]
    DIRECTION INPUT ;
    USE SIGNAL ;
    PORT
      LAYER M5 ;
        RECT  165.984 0 166.008 0.084 ;
    END
  END xai[240]
  PIN xai[241]
    DIRECTION INPUT ;
    USE SIGNAL ;
    PORT
      LAYER M5 ;
        RECT  166.128 0 166.152 0.084 ;
    END
  END xai[241]
  PIN xai[242]
    DIRECTION INPUT ;
    USE SIGNAL ;
    PORT
      LAYER M5 ;
        RECT  166.272 0 166.296 0.084 ;
    END
  END xai[242]
  PIN xai[243]
    DIRECTION INPUT ;
    USE SIGNAL ;
    PORT
      LAYER M5 ;
        RECT  166.416 0 166.44 0.084 ;
    END
  END xai[243]
  PIN xai[244]
    DIRECTION INPUT ;
    USE SIGNAL ;
    PORT
      LAYER M5 ;
        RECT  166.56 0 166.584 0.084 ;
    END
  END xai[244]
  PIN xai[245]
    DIRECTION INPUT ;
    USE SIGNAL ;
    PORT
      LAYER M5 ;
        RECT  166.704 0 166.728 0.084 ;
    END
  END xai[245]
  PIN xai[246]
    DIRECTION INPUT ;
    USE SIGNAL ;
    PORT
      LAYER M5 ;
        RECT  166.848 0 166.872 0.084 ;
    END
  END xai[246]
  PIN xai[247]
    DIRECTION INPUT ;
    USE SIGNAL ;
    PORT
      LAYER M5 ;
        RECT  166.992 0 167.016 0.084 ;
    END
  END xai[247]
  PIN xai[248]
    DIRECTION INPUT ;
    USE SIGNAL ;
    PORT
      LAYER M5 ;
        RECT  167.136 0 167.16 0.084 ;
    END
  END xai[248]
  PIN xai[249]
    DIRECTION INPUT ;
    USE SIGNAL ;
    PORT
      LAYER M5 ;
        RECT  167.28 0 167.304 0.084 ;
    END
  END xai[249]
  PIN xai[24]
    DIRECTION INPUT ;
    USE SIGNAL ;
    PORT
      LAYER M5 ;
        RECT  134.88 0 134.904 0.084 ;
    END
  END xai[24]
  PIN xai[250]
    DIRECTION INPUT ;
    USE SIGNAL ;
    PORT
      LAYER M5 ;
        RECT  167.424 0 167.448 0.084 ;
    END
  END xai[250]
  PIN xai[251]
    DIRECTION INPUT ;
    USE SIGNAL ;
    PORT
      LAYER M5 ;
        RECT  167.568 0 167.592 0.084 ;
    END
  END xai[251]
  PIN xai[252]
    DIRECTION INPUT ;
    USE SIGNAL ;
    PORT
      LAYER M5 ;
        RECT  167.712 0 167.736 0.084 ;
    END
  END xai[252]
  PIN xai[253]
    DIRECTION INPUT ;
    USE SIGNAL ;
    PORT
      LAYER M5 ;
        RECT  167.856 0 167.88 0.084 ;
    END
  END xai[253]
  PIN xai[254]
    DIRECTION INPUT ;
    USE SIGNAL ;
    PORT
      LAYER M5 ;
        RECT  168 0 168.024 0.084 ;
    END
  END xai[254]
  PIN xai[255]
    DIRECTION INPUT ;
    USE SIGNAL ;
    PORT
      LAYER M5 ;
        RECT  168.144 0 168.168 0.084 ;
    END
  END xai[255]
  PIN xai[256]
    DIRECTION INPUT ;
    USE SIGNAL ;
    PORT
      LAYER M5 ;
        RECT  168.288 0 168.312 0.084 ;
    END
  END xai[256]
  PIN xai[257]
    DIRECTION INPUT ;
    USE SIGNAL ;
    PORT
      LAYER M5 ;
        RECT  168.432 0 168.456 0.084 ;
    END
  END xai[257]
  PIN xai[258]
    DIRECTION INPUT ;
    USE SIGNAL ;
    PORT
      LAYER M5 ;
        RECT  168.576 0 168.6 0.084 ;
    END
  END xai[258]
  PIN xai[259]
    DIRECTION INPUT ;
    USE SIGNAL ;
    PORT
      LAYER M5 ;
        RECT  168.72 0 168.744 0.084 ;
    END
  END xai[259]
  PIN xai[25]
    DIRECTION INPUT ;
    USE SIGNAL ;
    PORT
      LAYER M5 ;
        RECT  135.024 0 135.048 0.084 ;
    END
  END xai[25]
  PIN xai[260]
    DIRECTION INPUT ;
    USE SIGNAL ;
    PORT
      LAYER M5 ;
        RECT  168.864 0 168.888 0.084 ;
    END
  END xai[260]
  PIN xai[261]
    DIRECTION INPUT ;
    USE SIGNAL ;
    PORT
      LAYER M5 ;
        RECT  169.008 0 169.032 0.084 ;
    END
  END xai[261]
  PIN xai[262]
    DIRECTION INPUT ;
    USE SIGNAL ;
    PORT
      LAYER M5 ;
        RECT  169.152 0 169.176 0.084 ;
    END
  END xai[262]
  PIN xai[263]
    DIRECTION INPUT ;
    USE SIGNAL ;
    PORT
      LAYER M5 ;
        RECT  169.296 0 169.32 0.084 ;
    END
  END xai[263]
  PIN xai[264]
    DIRECTION INPUT ;
    USE SIGNAL ;
    PORT
      LAYER M5 ;
        RECT  169.44 0 169.464 0.084 ;
    END
  END xai[264]
  PIN xai[265]
    DIRECTION INPUT ;
    USE SIGNAL ;
    PORT
      LAYER M5 ;
        RECT  169.584 0 169.608 0.084 ;
    END
  END xai[265]
  PIN xai[266]
    DIRECTION INPUT ;
    USE SIGNAL ;
    PORT
      LAYER M5 ;
        RECT  169.728 0 169.752 0.084 ;
    END
  END xai[266]
  PIN xai[267]
    DIRECTION INPUT ;
    USE SIGNAL ;
    PORT
      LAYER M5 ;
        RECT  169.872 0 169.896 0.084 ;
    END
  END xai[267]
  PIN xai[268]
    DIRECTION INPUT ;
    USE SIGNAL ;
    PORT
      LAYER M5 ;
        RECT  170.016 0 170.04 0.084 ;
    END
  END xai[268]
  PIN xai[269]
    DIRECTION INPUT ;
    USE SIGNAL ;
    PORT
      LAYER M5 ;
        RECT  170.16 0 170.184 0.084 ;
    END
  END xai[269]
  PIN xai[26]
    DIRECTION INPUT ;
    USE SIGNAL ;
    PORT
      LAYER M5 ;
        RECT  135.168 0 135.192 0.084 ;
    END
  END xai[26]
  PIN xai[270]
    DIRECTION INPUT ;
    USE SIGNAL ;
    PORT
      LAYER M5 ;
        RECT  170.304 0 170.328 0.084 ;
    END
  END xai[270]
  PIN xai[271]
    DIRECTION INPUT ;
    USE SIGNAL ;
    PORT
      LAYER M5 ;
        RECT  170.448 0 170.472 0.084 ;
    END
  END xai[271]
  PIN xai[272]
    DIRECTION INPUT ;
    USE SIGNAL ;
    PORT
      LAYER M5 ;
        RECT  170.592 0 170.616 0.084 ;
    END
  END xai[272]
  PIN xai[273]
    DIRECTION INPUT ;
    USE SIGNAL ;
    PORT
      LAYER M5 ;
        RECT  170.736 0 170.76 0.084 ;
    END
  END xai[273]
  PIN xai[274]
    DIRECTION INPUT ;
    USE SIGNAL ;
    PORT
      LAYER M5 ;
        RECT  170.88 0 170.904 0.084 ;
    END
  END xai[274]
  PIN xai[275]
    DIRECTION INPUT ;
    USE SIGNAL ;
    PORT
      LAYER M5 ;
        RECT  171.024 0 171.048 0.084 ;
    END
  END xai[275]
  PIN xai[276]
    DIRECTION INPUT ;
    USE SIGNAL ;
    PORT
      LAYER M5 ;
        RECT  171.168 0 171.192 0.084 ;
    END
  END xai[276]
  PIN xai[277]
    DIRECTION INPUT ;
    USE SIGNAL ;
    PORT
      LAYER M5 ;
        RECT  171.312 0 171.336 0.084 ;
    END
  END xai[277]
  PIN xai[278]
    DIRECTION INPUT ;
    USE SIGNAL ;
    PORT
      LAYER M5 ;
        RECT  171.456 0 171.48 0.084 ;
    END
  END xai[278]
  PIN xai[279]
    DIRECTION INPUT ;
    USE SIGNAL ;
    PORT
      LAYER M5 ;
        RECT  171.6 0 171.624 0.084 ;
    END
  END xai[279]
  PIN xai[27]
    DIRECTION INPUT ;
    USE SIGNAL ;
    PORT
      LAYER M5 ;
        RECT  135.312 0 135.336 0.084 ;
    END
  END xai[27]
  PIN xai[280]
    DIRECTION INPUT ;
    USE SIGNAL ;
    PORT
      LAYER M5 ;
        RECT  171.744 0 171.768 0.084 ;
    END
  END xai[280]
  PIN xai[281]
    DIRECTION INPUT ;
    USE SIGNAL ;
    PORT
      LAYER M5 ;
        RECT  171.888 0 171.912 0.084 ;
    END
  END xai[281]
  PIN xai[282]
    DIRECTION INPUT ;
    USE SIGNAL ;
    PORT
      LAYER M5 ;
        RECT  172.032 0 172.056 0.084 ;
    END
  END xai[282]
  PIN xai[28]
    DIRECTION INPUT ;
    USE SIGNAL ;
    PORT
      LAYER M5 ;
        RECT  135.456 0 135.48 0.084 ;
    END
  END xai[28]
  PIN xai[29]
    DIRECTION INPUT ;
    USE SIGNAL ;
    PORT
      LAYER M5 ;
        RECT  135.6 0 135.624 0.084 ;
    END
  END xai[29]
  PIN xai[2]
    DIRECTION INPUT ;
    USE SIGNAL ;
    PORT
      LAYER M5 ;
        RECT  131.712 0 131.736 0.084 ;
    END
  END xai[2]
  PIN xai[30]
    DIRECTION INPUT ;
    USE SIGNAL ;
    PORT
      LAYER M5 ;
        RECT  135.744 0 135.768 0.084 ;
    END
  END xai[30]
  PIN xai[31]
    DIRECTION INPUT ;
    USE SIGNAL ;
    PORT
      LAYER M5 ;
        RECT  135.888 0 135.912 0.084 ;
    END
  END xai[31]
  PIN xai[32]
    DIRECTION INPUT ;
    USE SIGNAL ;
    PORT
      LAYER M5 ;
        RECT  136.032 0 136.056 0.084 ;
    END
  END xai[32]
  PIN xai[33]
    DIRECTION INPUT ;
    USE SIGNAL ;
    PORT
      LAYER M5 ;
        RECT  136.176 0 136.2 0.084 ;
    END
  END xai[33]
  PIN xai[34]
    DIRECTION INPUT ;
    USE SIGNAL ;
    PORT
      LAYER M5 ;
        RECT  136.32 0 136.344 0.084 ;
    END
  END xai[34]
  PIN xai[35]
    DIRECTION INPUT ;
    USE SIGNAL ;
    PORT
      LAYER M5 ;
        RECT  136.464 0 136.488 0.084 ;
    END
  END xai[35]
  PIN xai[36]
    DIRECTION INPUT ;
    USE SIGNAL ;
    PORT
      LAYER M5 ;
        RECT  136.608 0 136.632 0.084 ;
    END
  END xai[36]
  PIN xai[37]
    DIRECTION INPUT ;
    USE SIGNAL ;
    PORT
      LAYER M5 ;
        RECT  136.752 0 136.776 0.084 ;
    END
  END xai[37]
  PIN xai[38]
    DIRECTION INPUT ;
    USE SIGNAL ;
    PORT
      LAYER M5 ;
        RECT  136.896 0 136.92 0.084 ;
    END
  END xai[38]
  PIN xai[39]
    DIRECTION INPUT ;
    USE SIGNAL ;
    PORT
      LAYER M5 ;
        RECT  137.04 0 137.064 0.084 ;
    END
  END xai[39]
  PIN xai[3]
    DIRECTION INPUT ;
    USE SIGNAL ;
    PORT
      LAYER M5 ;
        RECT  131.856 0 131.88 0.084 ;
    END
  END xai[3]
  PIN xai[40]
    DIRECTION INPUT ;
    USE SIGNAL ;
    PORT
      LAYER M5 ;
        RECT  137.184 0 137.208 0.084 ;
    END
  END xai[40]
  PIN xai[41]
    DIRECTION INPUT ;
    USE SIGNAL ;
    PORT
      LAYER M5 ;
        RECT  137.328 0 137.352 0.084 ;
    END
  END xai[41]
  PIN xai[42]
    DIRECTION INPUT ;
    USE SIGNAL ;
    PORT
      LAYER M5 ;
        RECT  137.472 0 137.496 0.084 ;
    END
  END xai[42]
  PIN xai[43]
    DIRECTION INPUT ;
    USE SIGNAL ;
    PORT
      LAYER M5 ;
        RECT  137.616 0 137.64 0.084 ;
    END
  END xai[43]
  PIN xai[44]
    DIRECTION INPUT ;
    USE SIGNAL ;
    PORT
      LAYER M5 ;
        RECT  137.76 0 137.784 0.084 ;
    END
  END xai[44]
  PIN xai[45]
    DIRECTION INPUT ;
    USE SIGNAL ;
    PORT
      LAYER M5 ;
        RECT  137.904 0 137.928 0.084 ;
    END
  END xai[45]
  PIN xai[46]
    DIRECTION INPUT ;
    USE SIGNAL ;
    PORT
      LAYER M5 ;
        RECT  138.048 0 138.072 0.084 ;
    END
  END xai[46]
  PIN xai[47]
    DIRECTION INPUT ;
    USE SIGNAL ;
    PORT
      LAYER M5 ;
        RECT  138.192 0 138.216 0.084 ;
    END
  END xai[47]
  PIN xai[48]
    DIRECTION INPUT ;
    USE SIGNAL ;
    PORT
      LAYER M5 ;
        RECT  138.336 0 138.36 0.084 ;
    END
  END xai[48]
  PIN xai[49]
    DIRECTION INPUT ;
    USE SIGNAL ;
    PORT
      LAYER M5 ;
        RECT  138.48 0 138.504 0.084 ;
    END
  END xai[49]
  PIN xai[4]
    DIRECTION INPUT ;
    USE SIGNAL ;
    PORT
      LAYER M5 ;
        RECT  132 0 132.024 0.084 ;
    END
  END xai[4]
  PIN xai[50]
    DIRECTION INPUT ;
    USE SIGNAL ;
    PORT
      LAYER M5 ;
        RECT  138.624 0 138.648 0.084 ;
    END
  END xai[50]
  PIN xai[51]
    DIRECTION INPUT ;
    USE SIGNAL ;
    PORT
      LAYER M5 ;
        RECT  138.768 0 138.792 0.084 ;
    END
  END xai[51]
  PIN xai[52]
    DIRECTION INPUT ;
    USE SIGNAL ;
    PORT
      LAYER M5 ;
        RECT  138.912 0 138.936 0.084 ;
    END
  END xai[52]
  PIN xai[53]
    DIRECTION INPUT ;
    USE SIGNAL ;
    PORT
      LAYER M5 ;
        RECT  139.056 0 139.08 0.084 ;
    END
  END xai[53]
  PIN xai[54]
    DIRECTION INPUT ;
    USE SIGNAL ;
    PORT
      LAYER M5 ;
        RECT  139.2 0 139.224 0.084 ;
    END
  END xai[54]
  PIN xai[55]
    DIRECTION INPUT ;
    USE SIGNAL ;
    PORT
      LAYER M5 ;
        RECT  139.344 0 139.368 0.084 ;
    END
  END xai[55]
  PIN xai[56]
    DIRECTION INPUT ;
    USE SIGNAL ;
    PORT
      LAYER M5 ;
        RECT  139.488 0 139.512 0.084 ;
    END
  END xai[56]
  PIN xai[57]
    DIRECTION INPUT ;
    USE SIGNAL ;
    PORT
      LAYER M5 ;
        RECT  139.632 0 139.656 0.084 ;
    END
  END xai[57]
  PIN xai[58]
    DIRECTION INPUT ;
    USE SIGNAL ;
    PORT
      LAYER M5 ;
        RECT  139.776 0 139.8 0.084 ;
    END
  END xai[58]
  PIN xai[59]
    DIRECTION INPUT ;
    USE SIGNAL ;
    PORT
      LAYER M5 ;
        RECT  139.92 0 139.944 0.084 ;
    END
  END xai[59]
  PIN xai[5]
    DIRECTION INPUT ;
    USE SIGNAL ;
    PORT
      LAYER M5 ;
        RECT  132.144 0 132.168 0.084 ;
    END
  END xai[5]
  PIN xai[60]
    DIRECTION INPUT ;
    USE SIGNAL ;
    PORT
      LAYER M5 ;
        RECT  140.064 0 140.088 0.084 ;
    END
  END xai[60]
  PIN xai[61]
    DIRECTION INPUT ;
    USE SIGNAL ;
    PORT
      LAYER M5 ;
        RECT  140.208 0 140.232 0.084 ;
    END
  END xai[61]
  PIN xai[62]
    DIRECTION INPUT ;
    USE SIGNAL ;
    PORT
      LAYER M5 ;
        RECT  140.352 0 140.376 0.084 ;
    END
  END xai[62]
  PIN xai[63]
    DIRECTION INPUT ;
    USE SIGNAL ;
    PORT
      LAYER M5 ;
        RECT  140.496 0 140.52 0.084 ;
    END
  END xai[63]
  PIN xai[64]
    DIRECTION INPUT ;
    USE SIGNAL ;
    PORT
      LAYER M5 ;
        RECT  140.64 0 140.664 0.084 ;
    END
  END xai[64]
  PIN xai[65]
    DIRECTION INPUT ;
    USE SIGNAL ;
    PORT
      LAYER M5 ;
        RECT  140.784 0 140.808 0.084 ;
    END
  END xai[65]
  PIN xai[66]
    DIRECTION INPUT ;
    USE SIGNAL ;
    PORT
      LAYER M5 ;
        RECT  140.928 0 140.952 0.084 ;
    END
  END xai[66]
  PIN xai[67]
    DIRECTION INPUT ;
    USE SIGNAL ;
    PORT
      LAYER M5 ;
        RECT  141.072 0 141.096 0.084 ;
    END
  END xai[67]
  PIN xai[68]
    DIRECTION INPUT ;
    USE SIGNAL ;
    PORT
      LAYER M5 ;
        RECT  141.216 0 141.24 0.084 ;
    END
  END xai[68]
  PIN xai[69]
    DIRECTION INPUT ;
    USE SIGNAL ;
    PORT
      LAYER M5 ;
        RECT  141.36 0 141.384 0.084 ;
    END
  END xai[69]
  PIN xai[6]
    DIRECTION INPUT ;
    USE SIGNAL ;
    PORT
      LAYER M5 ;
        RECT  132.288 0 132.312 0.084 ;
    END
  END xai[6]
  PIN xai[70]
    DIRECTION INPUT ;
    USE SIGNAL ;
    PORT
      LAYER M5 ;
        RECT  141.504 0 141.528 0.084 ;
    END
  END xai[70]
  PIN xai[71]
    DIRECTION INPUT ;
    USE SIGNAL ;
    PORT
      LAYER M5 ;
        RECT  141.648 0 141.672 0.084 ;
    END
  END xai[71]
  PIN xai[72]
    DIRECTION INPUT ;
    USE SIGNAL ;
    PORT
      LAYER M5 ;
        RECT  141.792 0 141.816 0.084 ;
    END
  END xai[72]
  PIN xai[73]
    DIRECTION INPUT ;
    USE SIGNAL ;
    PORT
      LAYER M5 ;
        RECT  141.936 0 141.96 0.084 ;
    END
  END xai[73]
  PIN xai[74]
    DIRECTION INPUT ;
    USE SIGNAL ;
    PORT
      LAYER M5 ;
        RECT  142.08 0 142.104 0.084 ;
    END
  END xai[74]
  PIN xai[75]
    DIRECTION INPUT ;
    USE SIGNAL ;
    PORT
      LAYER M5 ;
        RECT  142.224 0 142.248 0.084 ;
    END
  END xai[75]
  PIN xai[76]
    DIRECTION INPUT ;
    USE SIGNAL ;
    PORT
      LAYER M5 ;
        RECT  142.368 0 142.392 0.084 ;
    END
  END xai[76]
  PIN xai[77]
    DIRECTION INPUT ;
    USE SIGNAL ;
    PORT
      LAYER M5 ;
        RECT  142.512 0 142.536 0.084 ;
    END
  END xai[77]
  PIN xai[78]
    DIRECTION INPUT ;
    USE SIGNAL ;
    PORT
      LAYER M5 ;
        RECT  142.656 0 142.68 0.084 ;
    END
  END xai[78]
  PIN xai[79]
    DIRECTION INPUT ;
    USE SIGNAL ;
    PORT
      LAYER M5 ;
        RECT  142.8 0 142.824 0.084 ;
    END
  END xai[79]
  PIN xai[7]
    DIRECTION INPUT ;
    USE SIGNAL ;
    PORT
      LAYER M5 ;
        RECT  132.432 0 132.456 0.084 ;
    END
  END xai[7]
  PIN xai[80]
    DIRECTION INPUT ;
    USE SIGNAL ;
    PORT
      LAYER M5 ;
        RECT  142.944 0 142.968 0.084 ;
    END
  END xai[80]
  PIN xai[81]
    DIRECTION INPUT ;
    USE SIGNAL ;
    PORT
      LAYER M5 ;
        RECT  143.088 0 143.112 0.084 ;
    END
  END xai[81]
  PIN xai[82]
    DIRECTION INPUT ;
    USE SIGNAL ;
    PORT
      LAYER M5 ;
        RECT  143.232 0 143.256 0.084 ;
    END
  END xai[82]
  PIN xai[83]
    DIRECTION INPUT ;
    USE SIGNAL ;
    PORT
      LAYER M5 ;
        RECT  143.376 0 143.4 0.084 ;
    END
  END xai[83]
  PIN xai[84]
    DIRECTION INPUT ;
    USE SIGNAL ;
    PORT
      LAYER M5 ;
        RECT  143.52 0 143.544 0.084 ;
    END
  END xai[84]
  PIN xai[85]
    DIRECTION INPUT ;
    USE SIGNAL ;
    PORT
      LAYER M5 ;
        RECT  143.664 0 143.688 0.084 ;
    END
  END xai[85]
  PIN xai[86]
    DIRECTION INPUT ;
    USE SIGNAL ;
    PORT
      LAYER M5 ;
        RECT  143.808 0 143.832 0.084 ;
    END
  END xai[86]
  PIN xai[87]
    DIRECTION INPUT ;
    USE SIGNAL ;
    PORT
      LAYER M5 ;
        RECT  143.952 0 143.976 0.084 ;
    END
  END xai[87]
  PIN xai[88]
    DIRECTION INPUT ;
    USE SIGNAL ;
    PORT
      LAYER M5 ;
        RECT  144.096 0 144.12 0.084 ;
    END
  END xai[88]
  PIN xai[89]
    DIRECTION INPUT ;
    USE SIGNAL ;
    PORT
      LAYER M5 ;
        RECT  144.24 0 144.264 0.084 ;
    END
  END xai[89]
  PIN xai[8]
    DIRECTION INPUT ;
    USE SIGNAL ;
    PORT
      LAYER M5 ;
        RECT  132.576 0 132.6 0.084 ;
    END
  END xai[8]
  PIN xai[90]
    DIRECTION INPUT ;
    USE SIGNAL ;
    PORT
      LAYER M5 ;
        RECT  144.384 0 144.408 0.084 ;
    END
  END xai[90]
  PIN xai[91]
    DIRECTION INPUT ;
    USE SIGNAL ;
    PORT
      LAYER M5 ;
        RECT  144.528 0 144.552 0.084 ;
    END
  END xai[91]
  PIN xai[92]
    DIRECTION INPUT ;
    USE SIGNAL ;
    PORT
      LAYER M5 ;
        RECT  144.672 0 144.696 0.084 ;
    END
  END xai[92]
  PIN xai[93]
    DIRECTION INPUT ;
    USE SIGNAL ;
    PORT
      LAYER M5 ;
        RECT  144.816 0 144.84 0.084 ;
    END
  END xai[93]
  PIN xai[94]
    DIRECTION INPUT ;
    USE SIGNAL ;
    PORT
      LAYER M5 ;
        RECT  144.96 0 144.984 0.084 ;
    END
  END xai[94]
  PIN xai[95]
    DIRECTION INPUT ;
    USE SIGNAL ;
    PORT
      LAYER M5 ;
        RECT  145.104 0 145.128 0.084 ;
    END
  END xai[95]
  PIN xai[96]
    DIRECTION INPUT ;
    USE SIGNAL ;
    PORT
      LAYER M5 ;
        RECT  145.248 0 145.272 0.084 ;
    END
  END xai[96]
  PIN xai[97]
    DIRECTION INPUT ;
    USE SIGNAL ;
    PORT
      LAYER M5 ;
        RECT  145.392 0 145.416 0.084 ;
    END
  END xai[97]
  PIN xai[98]
    DIRECTION INPUT ;
    USE SIGNAL ;
    PORT
      LAYER M5 ;
        RECT  145.536 0 145.56 0.084 ;
    END
  END xai[98]
  PIN xai[99]
    DIRECTION INPUT ;
    USE SIGNAL ;
    PORT
      LAYER M5 ;
        RECT  145.68 0 145.704 0.084 ;
    END
  END xai[99]
  PIN xai[9]
    DIRECTION INPUT ;
    USE SIGNAL ;
    PORT
      LAYER M5 ;
        RECT  132.72 0 132.744 0.084 ;
    END
  END xai[9]
  PIN xb[0]
    DIRECTION OUTPUT ;
    USE SIGNAL ;
    PORT
      LAYER M5 ;
        RECT  89.328 30.156 89.352 30.24 ;
    END
  END xb[0]
  PIN xb[100]
    DIRECTION OUTPUT ;
    USE SIGNAL ;
    PORT
      LAYER M5 ;
        RECT  103.728 30.156 103.752 30.24 ;
    END
  END xb[100]
  PIN xb[101]
    DIRECTION OUTPUT ;
    USE SIGNAL ;
    PORT
      LAYER M5 ;
        RECT  103.872 30.156 103.896 30.24 ;
    END
  END xb[101]
  PIN xb[102]
    DIRECTION OUTPUT ;
    USE SIGNAL ;
    PORT
      LAYER M5 ;
        RECT  104.016 30.156 104.04 30.24 ;
    END
  END xb[102]
  PIN xb[103]
    DIRECTION OUTPUT ;
    USE SIGNAL ;
    PORT
      LAYER M5 ;
        RECT  104.16 30.156 104.184 30.24 ;
    END
  END xb[103]
  PIN xb[104]
    DIRECTION OUTPUT ;
    USE SIGNAL ;
    PORT
      LAYER M5 ;
        RECT  104.304 30.156 104.328 30.24 ;
    END
  END xb[104]
  PIN xb[105]
    DIRECTION OUTPUT ;
    USE SIGNAL ;
    PORT
      LAYER M5 ;
        RECT  104.448 30.156 104.472 30.24 ;
    END
  END xb[105]
  PIN xb[106]
    DIRECTION OUTPUT ;
    USE SIGNAL ;
    PORT
      LAYER M5 ;
        RECT  104.592 30.156 104.616 30.24 ;
    END
  END xb[106]
  PIN xb[107]
    DIRECTION OUTPUT ;
    USE SIGNAL ;
    PORT
      LAYER M5 ;
        RECT  104.736 30.156 104.76 30.24 ;
    END
  END xb[107]
  PIN xb[108]
    DIRECTION OUTPUT ;
    USE SIGNAL ;
    PORT
      LAYER M5 ;
        RECT  104.88 30.156 104.904 30.24 ;
    END
  END xb[108]
  PIN xb[109]
    DIRECTION OUTPUT ;
    USE SIGNAL ;
    PORT
      LAYER M5 ;
        RECT  105.024 30.156 105.048 30.24 ;
    END
  END xb[109]
  PIN xb[10]
    DIRECTION OUTPUT ;
    USE SIGNAL ;
    PORT
      LAYER M5 ;
        RECT  90.768 30.156 90.792 30.24 ;
    END
  END xb[10]
  PIN xb[110]
    DIRECTION OUTPUT ;
    USE SIGNAL ;
    PORT
      LAYER M5 ;
        RECT  105.168 30.156 105.192 30.24 ;
    END
  END xb[110]
  PIN xb[111]
    DIRECTION OUTPUT ;
    USE SIGNAL ;
    PORT
      LAYER M5 ;
        RECT  105.312 30.156 105.336 30.24 ;
    END
  END xb[111]
  PIN xb[112]
    DIRECTION OUTPUT ;
    USE SIGNAL ;
    PORT
      LAYER M5 ;
        RECT  105.456 30.156 105.48 30.24 ;
    END
  END xb[112]
  PIN xb[113]
    DIRECTION OUTPUT ;
    USE SIGNAL ;
    PORT
      LAYER M5 ;
        RECT  105.6 30.156 105.624 30.24 ;
    END
  END xb[113]
  PIN xb[114]
    DIRECTION OUTPUT ;
    USE SIGNAL ;
    PORT
      LAYER M5 ;
        RECT  105.744 30.156 105.768 30.24 ;
    END
  END xb[114]
  PIN xb[115]
    DIRECTION OUTPUT ;
    USE SIGNAL ;
    PORT
      LAYER M5 ;
        RECT  105.888 30.156 105.912 30.24 ;
    END
  END xb[115]
  PIN xb[116]
    DIRECTION OUTPUT ;
    USE SIGNAL ;
    PORT
      LAYER M5 ;
        RECT  106.032 30.156 106.056 30.24 ;
    END
  END xb[116]
  PIN xb[117]
    DIRECTION OUTPUT ;
    USE SIGNAL ;
    PORT
      LAYER M5 ;
        RECT  106.176 30.156 106.2 30.24 ;
    END
  END xb[117]
  PIN xb[118]
    DIRECTION OUTPUT ;
    USE SIGNAL ;
    PORT
      LAYER M5 ;
        RECT  106.32 30.156 106.344 30.24 ;
    END
  END xb[118]
  PIN xb[119]
    DIRECTION OUTPUT ;
    USE SIGNAL ;
    PORT
      LAYER M5 ;
        RECT  106.464 30.156 106.488 30.24 ;
    END
  END xb[119]
  PIN xb[11]
    DIRECTION OUTPUT ;
    USE SIGNAL ;
    PORT
      LAYER M5 ;
        RECT  90.912 30.156 90.936 30.24 ;
    END
  END xb[11]
  PIN xb[120]
    DIRECTION OUTPUT ;
    USE SIGNAL ;
    PORT
      LAYER M5 ;
        RECT  106.608 30.156 106.632 30.24 ;
    END
  END xb[120]
  PIN xb[121]
    DIRECTION OUTPUT ;
    USE SIGNAL ;
    PORT
      LAYER M5 ;
        RECT  106.752 30.156 106.776 30.24 ;
    END
  END xb[121]
  PIN xb[122]
    DIRECTION OUTPUT ;
    USE SIGNAL ;
    PORT
      LAYER M5 ;
        RECT  106.896 30.156 106.92 30.24 ;
    END
  END xb[122]
  PIN xb[123]
    DIRECTION OUTPUT ;
    USE SIGNAL ;
    PORT
      LAYER M5 ;
        RECT  107.04 30.156 107.064 30.24 ;
    END
  END xb[123]
  PIN xb[124]
    DIRECTION OUTPUT ;
    USE SIGNAL ;
    PORT
      LAYER M5 ;
        RECT  107.184 30.156 107.208 30.24 ;
    END
  END xb[124]
  PIN xb[125]
    DIRECTION OUTPUT ;
    USE SIGNAL ;
    PORT
      LAYER M5 ;
        RECT  107.328 30.156 107.352 30.24 ;
    END
  END xb[125]
  PIN xb[126]
    DIRECTION OUTPUT ;
    USE SIGNAL ;
    PORT
      LAYER M5 ;
        RECT  107.472 30.156 107.496 30.24 ;
    END
  END xb[126]
  PIN xb[127]
    DIRECTION OUTPUT ;
    USE SIGNAL ;
    PORT
      LAYER M5 ;
        RECT  107.616 30.156 107.64 30.24 ;
    END
  END xb[127]
  PIN xb[128]
    DIRECTION OUTPUT ;
    USE SIGNAL ;
    PORT
      LAYER M5 ;
        RECT  107.76 30.156 107.784 30.24 ;
    END
  END xb[128]
  PIN xb[129]
    DIRECTION OUTPUT ;
    USE SIGNAL ;
    PORT
      LAYER M5 ;
        RECT  107.904 30.156 107.928 30.24 ;
    END
  END xb[129]
  PIN xb[12]
    DIRECTION OUTPUT ;
    USE SIGNAL ;
    PORT
      LAYER M5 ;
        RECT  91.056 30.156 91.08 30.24 ;
    END
  END xb[12]
  PIN xb[130]
    DIRECTION OUTPUT ;
    USE SIGNAL ;
    PORT
      LAYER M5 ;
        RECT  108.048 30.156 108.072 30.24 ;
    END
  END xb[130]
  PIN xb[131]
    DIRECTION OUTPUT ;
    USE SIGNAL ;
    PORT
      LAYER M5 ;
        RECT  108.192 30.156 108.216 30.24 ;
    END
  END xb[131]
  PIN xb[132]
    DIRECTION OUTPUT ;
    USE SIGNAL ;
    PORT
      LAYER M5 ;
        RECT  108.336 30.156 108.36 30.24 ;
    END
  END xb[132]
  PIN xb[133]
    DIRECTION OUTPUT ;
    USE SIGNAL ;
    PORT
      LAYER M5 ;
        RECT  108.48 30.156 108.504 30.24 ;
    END
  END xb[133]
  PIN xb[134]
    DIRECTION OUTPUT ;
    USE SIGNAL ;
    PORT
      LAYER M5 ;
        RECT  108.624 30.156 108.648 30.24 ;
    END
  END xb[134]
  PIN xb[135]
    DIRECTION OUTPUT ;
    USE SIGNAL ;
    PORT
      LAYER M5 ;
        RECT  108.768 30.156 108.792 30.24 ;
    END
  END xb[135]
  PIN xb[136]
    DIRECTION OUTPUT ;
    USE SIGNAL ;
    PORT
      LAYER M5 ;
        RECT  108.912 30.156 108.936 30.24 ;
    END
  END xb[136]
  PIN xb[137]
    DIRECTION OUTPUT ;
    USE SIGNAL ;
    PORT
      LAYER M5 ;
        RECT  109.056 30.156 109.08 30.24 ;
    END
  END xb[137]
  PIN xb[138]
    DIRECTION OUTPUT ;
    USE SIGNAL ;
    PORT
      LAYER M5 ;
        RECT  109.2 30.156 109.224 30.24 ;
    END
  END xb[138]
  PIN xb[139]
    DIRECTION OUTPUT ;
    USE SIGNAL ;
    PORT
      LAYER M5 ;
        RECT  109.344 30.156 109.368 30.24 ;
    END
  END xb[139]
  PIN xb[13]
    DIRECTION OUTPUT ;
    USE SIGNAL ;
    PORT
      LAYER M5 ;
        RECT  91.2 30.156 91.224 30.24 ;
    END
  END xb[13]
  PIN xb[140]
    DIRECTION OUTPUT ;
    USE SIGNAL ;
    PORT
      LAYER M5 ;
        RECT  109.488 30.156 109.512 30.24 ;
    END
  END xb[140]
  PIN xb[141]
    DIRECTION OUTPUT ;
    USE SIGNAL ;
    PORT
      LAYER M5 ;
        RECT  109.632 30.156 109.656 30.24 ;
    END
  END xb[141]
  PIN xb[142]
    DIRECTION OUTPUT ;
    USE SIGNAL ;
    PORT
      LAYER M5 ;
        RECT  109.776 30.156 109.8 30.24 ;
    END
  END xb[142]
  PIN xb[143]
    DIRECTION OUTPUT ;
    USE SIGNAL ;
    PORT
      LAYER M5 ;
        RECT  109.92 30.156 109.944 30.24 ;
    END
  END xb[143]
  PIN xb[144]
    DIRECTION OUTPUT ;
    USE SIGNAL ;
    PORT
      LAYER M5 ;
        RECT  110.064 30.156 110.088 30.24 ;
    END
  END xb[144]
  PIN xb[145]
    DIRECTION OUTPUT ;
    USE SIGNAL ;
    PORT
      LAYER M5 ;
        RECT  110.208 30.156 110.232 30.24 ;
    END
  END xb[145]
  PIN xb[146]
    DIRECTION OUTPUT ;
    USE SIGNAL ;
    PORT
      LAYER M5 ;
        RECT  110.352 30.156 110.376 30.24 ;
    END
  END xb[146]
  PIN xb[147]
    DIRECTION OUTPUT ;
    USE SIGNAL ;
    PORT
      LAYER M5 ;
        RECT  110.496 30.156 110.52 30.24 ;
    END
  END xb[147]
  PIN xb[148]
    DIRECTION OUTPUT ;
    USE SIGNAL ;
    PORT
      LAYER M5 ;
        RECT  110.64 30.156 110.664 30.24 ;
    END
  END xb[148]
  PIN xb[149]
    DIRECTION OUTPUT ;
    USE SIGNAL ;
    PORT
      LAYER M5 ;
        RECT  110.784 30.156 110.808 30.24 ;
    END
  END xb[149]
  PIN xb[14]
    DIRECTION OUTPUT ;
    USE SIGNAL ;
    PORT
      LAYER M5 ;
        RECT  91.344 30.156 91.368 30.24 ;
    END
  END xb[14]
  PIN xb[150]
    DIRECTION OUTPUT ;
    USE SIGNAL ;
    PORT
      LAYER M5 ;
        RECT  110.928 30.156 110.952 30.24 ;
    END
  END xb[150]
  PIN xb[151]
    DIRECTION OUTPUT ;
    USE SIGNAL ;
    PORT
      LAYER M5 ;
        RECT  111.072 30.156 111.096 30.24 ;
    END
  END xb[151]
  PIN xb[152]
    DIRECTION OUTPUT ;
    USE SIGNAL ;
    PORT
      LAYER M5 ;
        RECT  111.216 30.156 111.24 30.24 ;
    END
  END xb[152]
  PIN xb[153]
    DIRECTION OUTPUT ;
    USE SIGNAL ;
    PORT
      LAYER M5 ;
        RECT  111.36 30.156 111.384 30.24 ;
    END
  END xb[153]
  PIN xb[154]
    DIRECTION OUTPUT ;
    USE SIGNAL ;
    PORT
      LAYER M5 ;
        RECT  111.504 30.156 111.528 30.24 ;
    END
  END xb[154]
  PIN xb[155]
    DIRECTION OUTPUT ;
    USE SIGNAL ;
    PORT
      LAYER M5 ;
        RECT  111.648 30.156 111.672 30.24 ;
    END
  END xb[155]
  PIN xb[156]
    DIRECTION OUTPUT ;
    USE SIGNAL ;
    PORT
      LAYER M5 ;
        RECT  111.792 30.156 111.816 30.24 ;
    END
  END xb[156]
  PIN xb[157]
    DIRECTION OUTPUT ;
    USE SIGNAL ;
    PORT
      LAYER M5 ;
        RECT  111.936 30.156 111.96 30.24 ;
    END
  END xb[157]
  PIN xb[158]
    DIRECTION OUTPUT ;
    USE SIGNAL ;
    PORT
      LAYER M5 ;
        RECT  112.08 30.156 112.104 30.24 ;
    END
  END xb[158]
  PIN xb[159]
    DIRECTION OUTPUT ;
    USE SIGNAL ;
    PORT
      LAYER M5 ;
        RECT  112.224 30.156 112.248 30.24 ;
    END
  END xb[159]
  PIN xb[15]
    DIRECTION OUTPUT ;
    USE SIGNAL ;
    PORT
      LAYER M5 ;
        RECT  91.488 30.156 91.512 30.24 ;
    END
  END xb[15]
  PIN xb[160]
    DIRECTION OUTPUT ;
    USE SIGNAL ;
    PORT
      LAYER M5 ;
        RECT  112.368 30.156 112.392 30.24 ;
    END
  END xb[160]
  PIN xb[161]
    DIRECTION OUTPUT ;
    USE SIGNAL ;
    PORT
      LAYER M5 ;
        RECT  112.512 30.156 112.536 30.24 ;
    END
  END xb[161]
  PIN xb[162]
    DIRECTION OUTPUT ;
    USE SIGNAL ;
    PORT
      LAYER M5 ;
        RECT  112.656 30.156 112.68 30.24 ;
    END
  END xb[162]
  PIN xb[163]
    DIRECTION OUTPUT ;
    USE SIGNAL ;
    PORT
      LAYER M5 ;
        RECT  112.8 30.156 112.824 30.24 ;
    END
  END xb[163]
  PIN xb[164]
    DIRECTION OUTPUT ;
    USE SIGNAL ;
    PORT
      LAYER M5 ;
        RECT  112.944 30.156 112.968 30.24 ;
    END
  END xb[164]
  PIN xb[165]
    DIRECTION OUTPUT ;
    USE SIGNAL ;
    PORT
      LAYER M5 ;
        RECT  113.088 30.156 113.112 30.24 ;
    END
  END xb[165]
  PIN xb[166]
    DIRECTION OUTPUT ;
    USE SIGNAL ;
    PORT
      LAYER M5 ;
        RECT  113.232 30.156 113.256 30.24 ;
    END
  END xb[166]
  PIN xb[167]
    DIRECTION OUTPUT ;
    USE SIGNAL ;
    PORT
      LAYER M5 ;
        RECT  113.376 30.156 113.4 30.24 ;
    END
  END xb[167]
  PIN xb[168]
    DIRECTION OUTPUT ;
    USE SIGNAL ;
    PORT
      LAYER M5 ;
        RECT  113.52 30.156 113.544 30.24 ;
    END
  END xb[168]
  PIN xb[169]
    DIRECTION OUTPUT ;
    USE SIGNAL ;
    PORT
      LAYER M5 ;
        RECT  113.664 30.156 113.688 30.24 ;
    END
  END xb[169]
  PIN xb[16]
    DIRECTION OUTPUT ;
    USE SIGNAL ;
    PORT
      LAYER M5 ;
        RECT  91.632 30.156 91.656 30.24 ;
    END
  END xb[16]
  PIN xb[170]
    DIRECTION OUTPUT ;
    USE SIGNAL ;
    PORT
      LAYER M5 ;
        RECT  113.808 30.156 113.832 30.24 ;
    END
  END xb[170]
  PIN xb[171]
    DIRECTION OUTPUT ;
    USE SIGNAL ;
    PORT
      LAYER M5 ;
        RECT  113.952 30.156 113.976 30.24 ;
    END
  END xb[171]
  PIN xb[172]
    DIRECTION OUTPUT ;
    USE SIGNAL ;
    PORT
      LAYER M5 ;
        RECT  114.096 30.156 114.12 30.24 ;
    END
  END xb[172]
  PIN xb[173]
    DIRECTION OUTPUT ;
    USE SIGNAL ;
    PORT
      LAYER M5 ;
        RECT  114.24 30.156 114.264 30.24 ;
    END
  END xb[173]
  PIN xb[174]
    DIRECTION OUTPUT ;
    USE SIGNAL ;
    PORT
      LAYER M5 ;
        RECT  114.384 30.156 114.408 30.24 ;
    END
  END xb[174]
  PIN xb[175]
    DIRECTION OUTPUT ;
    USE SIGNAL ;
    PORT
      LAYER M5 ;
        RECT  114.528 30.156 114.552 30.24 ;
    END
  END xb[175]
  PIN xb[176]
    DIRECTION OUTPUT ;
    USE SIGNAL ;
    PORT
      LAYER M5 ;
        RECT  114.672 30.156 114.696 30.24 ;
    END
  END xb[176]
  PIN xb[177]
    DIRECTION OUTPUT ;
    USE SIGNAL ;
    PORT
      LAYER M5 ;
        RECT  114.816 30.156 114.84 30.24 ;
    END
  END xb[177]
  PIN xb[178]
    DIRECTION OUTPUT ;
    USE SIGNAL ;
    PORT
      LAYER M5 ;
        RECT  114.96 30.156 114.984 30.24 ;
    END
  END xb[178]
  PIN xb[179]
    DIRECTION OUTPUT ;
    USE SIGNAL ;
    PORT
      LAYER M5 ;
        RECT  115.104 30.156 115.128 30.24 ;
    END
  END xb[179]
  PIN xb[17]
    DIRECTION OUTPUT ;
    USE SIGNAL ;
    PORT
      LAYER M5 ;
        RECT  91.776 30.156 91.8 30.24 ;
    END
  END xb[17]
  PIN xb[180]
    DIRECTION OUTPUT ;
    USE SIGNAL ;
    PORT
      LAYER M5 ;
        RECT  115.248 30.156 115.272 30.24 ;
    END
  END xb[180]
  PIN xb[181]
    DIRECTION OUTPUT ;
    USE SIGNAL ;
    PORT
      LAYER M5 ;
        RECT  115.392 30.156 115.416 30.24 ;
    END
  END xb[181]
  PIN xb[182]
    DIRECTION OUTPUT ;
    USE SIGNAL ;
    PORT
      LAYER M5 ;
        RECT  115.536 30.156 115.56 30.24 ;
    END
  END xb[182]
  PIN xb[183]
    DIRECTION OUTPUT ;
    USE SIGNAL ;
    PORT
      LAYER M5 ;
        RECT  115.68 30.156 115.704 30.24 ;
    END
  END xb[183]
  PIN xb[184]
    DIRECTION OUTPUT ;
    USE SIGNAL ;
    PORT
      LAYER M5 ;
        RECT  115.824 30.156 115.848 30.24 ;
    END
  END xb[184]
  PIN xb[185]
    DIRECTION OUTPUT ;
    USE SIGNAL ;
    PORT
      LAYER M5 ;
        RECT  115.968 30.156 115.992 30.24 ;
    END
  END xb[185]
  PIN xb[186]
    DIRECTION OUTPUT ;
    USE SIGNAL ;
    PORT
      LAYER M5 ;
        RECT  116.112 30.156 116.136 30.24 ;
    END
  END xb[186]
  PIN xb[187]
    DIRECTION OUTPUT ;
    USE SIGNAL ;
    PORT
      LAYER M5 ;
        RECT  116.256 30.156 116.28 30.24 ;
    END
  END xb[187]
  PIN xb[188]
    DIRECTION OUTPUT ;
    USE SIGNAL ;
    PORT
      LAYER M5 ;
        RECT  116.4 30.156 116.424 30.24 ;
    END
  END xb[188]
  PIN xb[189]
    DIRECTION OUTPUT ;
    USE SIGNAL ;
    PORT
      LAYER M5 ;
        RECT  116.544 30.156 116.568 30.24 ;
    END
  END xb[189]
  PIN xb[18]
    DIRECTION OUTPUT ;
    USE SIGNAL ;
    PORT
      LAYER M5 ;
        RECT  91.92 30.156 91.944 30.24 ;
    END
  END xb[18]
  PIN xb[190]
    DIRECTION OUTPUT ;
    USE SIGNAL ;
    PORT
      LAYER M5 ;
        RECT  116.688 30.156 116.712 30.24 ;
    END
  END xb[190]
  PIN xb[191]
    DIRECTION OUTPUT ;
    USE SIGNAL ;
    PORT
      LAYER M5 ;
        RECT  116.832 30.156 116.856 30.24 ;
    END
  END xb[191]
  PIN xb[192]
    DIRECTION OUTPUT ;
    USE SIGNAL ;
    PORT
      LAYER M5 ;
        RECT  116.976 30.156 117 30.24 ;
    END
  END xb[192]
  PIN xb[193]
    DIRECTION OUTPUT ;
    USE SIGNAL ;
    PORT
      LAYER M5 ;
        RECT  117.12 30.156 117.144 30.24 ;
    END
  END xb[193]
  PIN xb[194]
    DIRECTION OUTPUT ;
    USE SIGNAL ;
    PORT
      LAYER M5 ;
        RECT  117.264 30.156 117.288 30.24 ;
    END
  END xb[194]
  PIN xb[195]
    DIRECTION OUTPUT ;
    USE SIGNAL ;
    PORT
      LAYER M5 ;
        RECT  117.408 30.156 117.432 30.24 ;
    END
  END xb[195]
  PIN xb[196]
    DIRECTION OUTPUT ;
    USE SIGNAL ;
    PORT
      LAYER M5 ;
        RECT  117.552 30.156 117.576 30.24 ;
    END
  END xb[196]
  PIN xb[197]
    DIRECTION OUTPUT ;
    USE SIGNAL ;
    PORT
      LAYER M5 ;
        RECT  117.696 30.156 117.72 30.24 ;
    END
  END xb[197]
  PIN xb[198]
    DIRECTION OUTPUT ;
    USE SIGNAL ;
    PORT
      LAYER M5 ;
        RECT  117.84 30.156 117.864 30.24 ;
    END
  END xb[198]
  PIN xb[199]
    DIRECTION OUTPUT ;
    USE SIGNAL ;
    PORT
      LAYER M5 ;
        RECT  117.984 30.156 118.008 30.24 ;
    END
  END xb[199]
  PIN xb[19]
    DIRECTION OUTPUT ;
    USE SIGNAL ;
    PORT
      LAYER M5 ;
        RECT  92.064 30.156 92.088 30.24 ;
    END
  END xb[19]
  PIN xb[1]
    DIRECTION OUTPUT ;
    USE SIGNAL ;
    PORT
      LAYER M5 ;
        RECT  89.472 30.156 89.496 30.24 ;
    END
  END xb[1]
  PIN xb[200]
    DIRECTION OUTPUT ;
    USE SIGNAL ;
    PORT
      LAYER M5 ;
        RECT  118.128 30.156 118.152 30.24 ;
    END
  END xb[200]
  PIN xb[201]
    DIRECTION OUTPUT ;
    USE SIGNAL ;
    PORT
      LAYER M5 ;
        RECT  118.272 30.156 118.296 30.24 ;
    END
  END xb[201]
  PIN xb[202]
    DIRECTION OUTPUT ;
    USE SIGNAL ;
    PORT
      LAYER M5 ;
        RECT  118.416 30.156 118.44 30.24 ;
    END
  END xb[202]
  PIN xb[203]
    DIRECTION OUTPUT ;
    USE SIGNAL ;
    PORT
      LAYER M5 ;
        RECT  118.56 30.156 118.584 30.24 ;
    END
  END xb[203]
  PIN xb[204]
    DIRECTION OUTPUT ;
    USE SIGNAL ;
    PORT
      LAYER M5 ;
        RECT  118.704 30.156 118.728 30.24 ;
    END
  END xb[204]
  PIN xb[205]
    DIRECTION OUTPUT ;
    USE SIGNAL ;
    PORT
      LAYER M5 ;
        RECT  118.848 30.156 118.872 30.24 ;
    END
  END xb[205]
  PIN xb[206]
    DIRECTION OUTPUT ;
    USE SIGNAL ;
    PORT
      LAYER M5 ;
        RECT  118.992 30.156 119.016 30.24 ;
    END
  END xb[206]
  PIN xb[207]
    DIRECTION OUTPUT ;
    USE SIGNAL ;
    PORT
      LAYER M5 ;
        RECT  119.136 30.156 119.16 30.24 ;
    END
  END xb[207]
  PIN xb[208]
    DIRECTION OUTPUT ;
    USE SIGNAL ;
    PORT
      LAYER M5 ;
        RECT  119.28 30.156 119.304 30.24 ;
    END
  END xb[208]
  PIN xb[209]
    DIRECTION OUTPUT ;
    USE SIGNAL ;
    PORT
      LAYER M5 ;
        RECT  119.424 30.156 119.448 30.24 ;
    END
  END xb[209]
  PIN xb[20]
    DIRECTION OUTPUT ;
    USE SIGNAL ;
    PORT
      LAYER M5 ;
        RECT  92.208 30.156 92.232 30.24 ;
    END
  END xb[20]
  PIN xb[210]
    DIRECTION OUTPUT ;
    USE SIGNAL ;
    PORT
      LAYER M5 ;
        RECT  119.568 30.156 119.592 30.24 ;
    END
  END xb[210]
  PIN xb[211]
    DIRECTION OUTPUT ;
    USE SIGNAL ;
    PORT
      LAYER M5 ;
        RECT  119.712 30.156 119.736 30.24 ;
    END
  END xb[211]
  PIN xb[212]
    DIRECTION OUTPUT ;
    USE SIGNAL ;
    PORT
      LAYER M5 ;
        RECT  119.856 30.156 119.88 30.24 ;
    END
  END xb[212]
  PIN xb[213]
    DIRECTION OUTPUT ;
    USE SIGNAL ;
    PORT
      LAYER M5 ;
        RECT  120 30.156 120.024 30.24 ;
    END
  END xb[213]
  PIN xb[214]
    DIRECTION OUTPUT ;
    USE SIGNAL ;
    PORT
      LAYER M5 ;
        RECT  120.144 30.156 120.168 30.24 ;
    END
  END xb[214]
  PIN xb[215]
    DIRECTION OUTPUT ;
    USE SIGNAL ;
    PORT
      LAYER M5 ;
        RECT  120.288 30.156 120.312 30.24 ;
    END
  END xb[215]
  PIN xb[216]
    DIRECTION OUTPUT ;
    USE SIGNAL ;
    PORT
      LAYER M5 ;
        RECT  120.432 30.156 120.456 30.24 ;
    END
  END xb[216]
  PIN xb[217]
    DIRECTION OUTPUT ;
    USE SIGNAL ;
    PORT
      LAYER M5 ;
        RECT  120.576 30.156 120.6 30.24 ;
    END
  END xb[217]
  PIN xb[218]
    DIRECTION OUTPUT ;
    USE SIGNAL ;
    PORT
      LAYER M5 ;
        RECT  120.72 30.156 120.744 30.24 ;
    END
  END xb[218]
  PIN xb[219]
    DIRECTION OUTPUT ;
    USE SIGNAL ;
    PORT
      LAYER M5 ;
        RECT  120.864 30.156 120.888 30.24 ;
    END
  END xb[219]
  PIN xb[21]
    DIRECTION OUTPUT ;
    USE SIGNAL ;
    PORT
      LAYER M5 ;
        RECT  92.352 30.156 92.376 30.24 ;
    END
  END xb[21]
  PIN xb[220]
    DIRECTION OUTPUT ;
    USE SIGNAL ;
    PORT
      LAYER M5 ;
        RECT  121.008 30.156 121.032 30.24 ;
    END
  END xb[220]
  PIN xb[221]
    DIRECTION OUTPUT ;
    USE SIGNAL ;
    PORT
      LAYER M5 ;
        RECT  121.152 30.156 121.176 30.24 ;
    END
  END xb[221]
  PIN xb[222]
    DIRECTION OUTPUT ;
    USE SIGNAL ;
    PORT
      LAYER M5 ;
        RECT  121.296 30.156 121.32 30.24 ;
    END
  END xb[222]
  PIN xb[223]
    DIRECTION OUTPUT ;
    USE SIGNAL ;
    PORT
      LAYER M5 ;
        RECT  121.44 30.156 121.464 30.24 ;
    END
  END xb[223]
  PIN xb[224]
    DIRECTION OUTPUT ;
    USE SIGNAL ;
    PORT
      LAYER M5 ;
        RECT  121.584 30.156 121.608 30.24 ;
    END
  END xb[224]
  PIN xb[225]
    DIRECTION OUTPUT ;
    USE SIGNAL ;
    PORT
      LAYER M5 ;
        RECT  121.728 30.156 121.752 30.24 ;
    END
  END xb[225]
  PIN xb[226]
    DIRECTION OUTPUT ;
    USE SIGNAL ;
    PORT
      LAYER M5 ;
        RECT  121.872 30.156 121.896 30.24 ;
    END
  END xb[226]
  PIN xb[227]
    DIRECTION OUTPUT ;
    USE SIGNAL ;
    PORT
      LAYER M5 ;
        RECT  122.016 30.156 122.04 30.24 ;
    END
  END xb[227]
  PIN xb[228]
    DIRECTION OUTPUT ;
    USE SIGNAL ;
    PORT
      LAYER M5 ;
        RECT  122.16 30.156 122.184 30.24 ;
    END
  END xb[228]
  PIN xb[229]
    DIRECTION OUTPUT ;
    USE SIGNAL ;
    PORT
      LAYER M5 ;
        RECT  122.304 30.156 122.328 30.24 ;
    END
  END xb[229]
  PIN xb[22]
    DIRECTION OUTPUT ;
    USE SIGNAL ;
    PORT
      LAYER M5 ;
        RECT  92.496 30.156 92.52 30.24 ;
    END
  END xb[22]
  PIN xb[230]
    DIRECTION OUTPUT ;
    USE SIGNAL ;
    PORT
      LAYER M5 ;
        RECT  122.448 30.156 122.472 30.24 ;
    END
  END xb[230]
  PIN xb[231]
    DIRECTION OUTPUT ;
    USE SIGNAL ;
    PORT
      LAYER M5 ;
        RECT  122.592 30.156 122.616 30.24 ;
    END
  END xb[231]
  PIN xb[232]
    DIRECTION OUTPUT ;
    USE SIGNAL ;
    PORT
      LAYER M5 ;
        RECT  122.736 30.156 122.76 30.24 ;
    END
  END xb[232]
  PIN xb[233]
    DIRECTION OUTPUT ;
    USE SIGNAL ;
    PORT
      LAYER M5 ;
        RECT  122.88 30.156 122.904 30.24 ;
    END
  END xb[233]
  PIN xb[234]
    DIRECTION OUTPUT ;
    USE SIGNAL ;
    PORT
      LAYER M5 ;
        RECT  123.024 30.156 123.048 30.24 ;
    END
  END xb[234]
  PIN xb[235]
    DIRECTION OUTPUT ;
    USE SIGNAL ;
    PORT
      LAYER M5 ;
        RECT  123.168 30.156 123.192 30.24 ;
    END
  END xb[235]
  PIN xb[236]
    DIRECTION OUTPUT ;
    USE SIGNAL ;
    PORT
      LAYER M5 ;
        RECT  123.312 30.156 123.336 30.24 ;
    END
  END xb[236]
  PIN xb[237]
    DIRECTION OUTPUT ;
    USE SIGNAL ;
    PORT
      LAYER M5 ;
        RECT  123.456 30.156 123.48 30.24 ;
    END
  END xb[237]
  PIN xb[238]
    DIRECTION OUTPUT ;
    USE SIGNAL ;
    PORT
      LAYER M5 ;
        RECT  123.6 30.156 123.624 30.24 ;
    END
  END xb[238]
  PIN xb[239]
    DIRECTION OUTPUT ;
    USE SIGNAL ;
    PORT
      LAYER M5 ;
        RECT  123.744 30.156 123.768 30.24 ;
    END
  END xb[239]
  PIN xb[23]
    DIRECTION OUTPUT ;
    USE SIGNAL ;
    PORT
      LAYER M5 ;
        RECT  92.64 30.156 92.664 30.24 ;
    END
  END xb[23]
  PIN xb[240]
    DIRECTION OUTPUT ;
    USE SIGNAL ;
    PORT
      LAYER M5 ;
        RECT  123.888 30.156 123.912 30.24 ;
    END
  END xb[240]
  PIN xb[241]
    DIRECTION OUTPUT ;
    USE SIGNAL ;
    PORT
      LAYER M5 ;
        RECT  124.032 30.156 124.056 30.24 ;
    END
  END xb[241]
  PIN xb[242]
    DIRECTION OUTPUT ;
    USE SIGNAL ;
    PORT
      LAYER M5 ;
        RECT  124.176 30.156 124.2 30.24 ;
    END
  END xb[242]
  PIN xb[243]
    DIRECTION OUTPUT ;
    USE SIGNAL ;
    PORT
      LAYER M5 ;
        RECT  124.32 30.156 124.344 30.24 ;
    END
  END xb[243]
  PIN xb[244]
    DIRECTION OUTPUT ;
    USE SIGNAL ;
    PORT
      LAYER M5 ;
        RECT  124.464 30.156 124.488 30.24 ;
    END
  END xb[244]
  PIN xb[245]
    DIRECTION OUTPUT ;
    USE SIGNAL ;
    PORT
      LAYER M5 ;
        RECT  124.608 30.156 124.632 30.24 ;
    END
  END xb[245]
  PIN xb[246]
    DIRECTION OUTPUT ;
    USE SIGNAL ;
    PORT
      LAYER M5 ;
        RECT  124.752 30.156 124.776 30.24 ;
    END
  END xb[246]
  PIN xb[247]
    DIRECTION OUTPUT ;
    USE SIGNAL ;
    PORT
      LAYER M5 ;
        RECT  124.896 30.156 124.92 30.24 ;
    END
  END xb[247]
  PIN xb[248]
    DIRECTION OUTPUT ;
    USE SIGNAL ;
    PORT
      LAYER M5 ;
        RECT  125.04 30.156 125.064 30.24 ;
    END
  END xb[248]
  PIN xb[249]
    DIRECTION OUTPUT ;
    USE SIGNAL ;
    PORT
      LAYER M5 ;
        RECT  125.184 30.156 125.208 30.24 ;
    END
  END xb[249]
  PIN xb[24]
    DIRECTION OUTPUT ;
    USE SIGNAL ;
    PORT
      LAYER M5 ;
        RECT  92.784 30.156 92.808 30.24 ;
    END
  END xb[24]
  PIN xb[250]
    DIRECTION OUTPUT ;
    USE SIGNAL ;
    PORT
      LAYER M5 ;
        RECT  125.328 30.156 125.352 30.24 ;
    END
  END xb[250]
  PIN xb[251]
    DIRECTION OUTPUT ;
    USE SIGNAL ;
    PORT
      LAYER M5 ;
        RECT  125.472 30.156 125.496 30.24 ;
    END
  END xb[251]
  PIN xb[252]
    DIRECTION OUTPUT ;
    USE SIGNAL ;
    PORT
      LAYER M5 ;
        RECT  125.616 30.156 125.64 30.24 ;
    END
  END xb[252]
  PIN xb[253]
    DIRECTION OUTPUT ;
    USE SIGNAL ;
    PORT
      LAYER M5 ;
        RECT  125.76 30.156 125.784 30.24 ;
    END
  END xb[253]
  PIN xb[254]
    DIRECTION OUTPUT ;
    USE SIGNAL ;
    PORT
      LAYER M5 ;
        RECT  125.904 30.156 125.928 30.24 ;
    END
  END xb[254]
  PIN xb[255]
    DIRECTION OUTPUT ;
    USE SIGNAL ;
    PORT
      LAYER M5 ;
        RECT  126.048 30.156 126.072 30.24 ;
    END
  END xb[255]
  PIN xb[256]
    DIRECTION OUTPUT ;
    USE SIGNAL ;
    PORT
      LAYER M5 ;
        RECT  126.192 30.156 126.216 30.24 ;
    END
  END xb[256]
  PIN xb[257]
    DIRECTION OUTPUT ;
    USE SIGNAL ;
    PORT
      LAYER M5 ;
        RECT  126.336 30.156 126.36 30.24 ;
    END
  END xb[257]
  PIN xb[258]
    DIRECTION OUTPUT ;
    USE SIGNAL ;
    PORT
      LAYER M5 ;
        RECT  126.48 30.156 126.504 30.24 ;
    END
  END xb[258]
  PIN xb[259]
    DIRECTION OUTPUT ;
    USE SIGNAL ;
    PORT
      LAYER M5 ;
        RECT  126.624 30.156 126.648 30.24 ;
    END
  END xb[259]
  PIN xb[25]
    DIRECTION OUTPUT ;
    USE SIGNAL ;
    PORT
      LAYER M5 ;
        RECT  92.928 30.156 92.952 30.24 ;
    END
  END xb[25]
  PIN xb[260]
    DIRECTION OUTPUT ;
    USE SIGNAL ;
    PORT
      LAYER M5 ;
        RECT  126.768 30.156 126.792 30.24 ;
    END
  END xb[260]
  PIN xb[261]
    DIRECTION OUTPUT ;
    USE SIGNAL ;
    PORT
      LAYER M5 ;
        RECT  126.912 30.156 126.936 30.24 ;
    END
  END xb[261]
  PIN xb[262]
    DIRECTION OUTPUT ;
    USE SIGNAL ;
    PORT
      LAYER M5 ;
        RECT  127.056 30.156 127.08 30.24 ;
    END
  END xb[262]
  PIN xb[263]
    DIRECTION OUTPUT ;
    USE SIGNAL ;
    PORT
      LAYER M5 ;
        RECT  127.2 30.156 127.224 30.24 ;
    END
  END xb[263]
  PIN xb[264]
    DIRECTION OUTPUT ;
    USE SIGNAL ;
    PORT
      LAYER M5 ;
        RECT  127.344 30.156 127.368 30.24 ;
    END
  END xb[264]
  PIN xb[265]
    DIRECTION OUTPUT ;
    USE SIGNAL ;
    PORT
      LAYER M5 ;
        RECT  127.488 30.156 127.512 30.24 ;
    END
  END xb[265]
  PIN xb[26]
    DIRECTION OUTPUT ;
    USE SIGNAL ;
    PORT
      LAYER M5 ;
        RECT  93.072 30.156 93.096 30.24 ;
    END
  END xb[26]
  PIN xb[27]
    DIRECTION OUTPUT ;
    USE SIGNAL ;
    PORT
      LAYER M5 ;
        RECT  93.216 30.156 93.24 30.24 ;
    END
  END xb[27]
  PIN xb[28]
    DIRECTION OUTPUT ;
    USE SIGNAL ;
    PORT
      LAYER M5 ;
        RECT  93.36 30.156 93.384 30.24 ;
    END
  END xb[28]
  PIN xb[29]
    DIRECTION OUTPUT ;
    USE SIGNAL ;
    PORT
      LAYER M5 ;
        RECT  93.504 30.156 93.528 30.24 ;
    END
  END xb[29]
  PIN xb[2]
    DIRECTION OUTPUT ;
    USE SIGNAL ;
    PORT
      LAYER M5 ;
        RECT  89.616 30.156 89.64 30.24 ;
    END
  END xb[2]
  PIN xb[30]
    DIRECTION OUTPUT ;
    USE SIGNAL ;
    PORT
      LAYER M5 ;
        RECT  93.648 30.156 93.672 30.24 ;
    END
  END xb[30]
  PIN xb[31]
    DIRECTION OUTPUT ;
    USE SIGNAL ;
    PORT
      LAYER M5 ;
        RECT  93.792 30.156 93.816 30.24 ;
    END
  END xb[31]
  PIN xb[32]
    DIRECTION OUTPUT ;
    USE SIGNAL ;
    PORT
      LAYER M5 ;
        RECT  93.936 30.156 93.96 30.24 ;
    END
  END xb[32]
  PIN xb[33]
    DIRECTION OUTPUT ;
    USE SIGNAL ;
    PORT
      LAYER M5 ;
        RECT  94.08 30.156 94.104 30.24 ;
    END
  END xb[33]
  PIN xb[34]
    DIRECTION OUTPUT ;
    USE SIGNAL ;
    PORT
      LAYER M5 ;
        RECT  94.224 30.156 94.248 30.24 ;
    END
  END xb[34]
  PIN xb[35]
    DIRECTION OUTPUT ;
    USE SIGNAL ;
    PORT
      LAYER M5 ;
        RECT  94.368 30.156 94.392 30.24 ;
    END
  END xb[35]
  PIN xb[36]
    DIRECTION OUTPUT ;
    USE SIGNAL ;
    PORT
      LAYER M5 ;
        RECT  94.512 30.156 94.536 30.24 ;
    END
  END xb[36]
  PIN xb[37]
    DIRECTION OUTPUT ;
    USE SIGNAL ;
    PORT
      LAYER M5 ;
        RECT  94.656 30.156 94.68 30.24 ;
    END
  END xb[37]
  PIN xb[38]
    DIRECTION OUTPUT ;
    USE SIGNAL ;
    PORT
      LAYER M5 ;
        RECT  94.8 30.156 94.824 30.24 ;
    END
  END xb[38]
  PIN xb[39]
    DIRECTION OUTPUT ;
    USE SIGNAL ;
    PORT
      LAYER M5 ;
        RECT  94.944 30.156 94.968 30.24 ;
    END
  END xb[39]
  PIN xb[3]
    DIRECTION OUTPUT ;
    USE SIGNAL ;
    PORT
      LAYER M5 ;
        RECT  89.76 30.156 89.784 30.24 ;
    END
  END xb[3]
  PIN xb[40]
    DIRECTION OUTPUT ;
    USE SIGNAL ;
    PORT
      LAYER M5 ;
        RECT  95.088 30.156 95.112 30.24 ;
    END
  END xb[40]
  PIN xb[41]
    DIRECTION OUTPUT ;
    USE SIGNAL ;
    PORT
      LAYER M5 ;
        RECT  95.232 30.156 95.256 30.24 ;
    END
  END xb[41]
  PIN xb[42]
    DIRECTION OUTPUT ;
    USE SIGNAL ;
    PORT
      LAYER M5 ;
        RECT  95.376 30.156 95.4 30.24 ;
    END
  END xb[42]
  PIN xb[43]
    DIRECTION OUTPUT ;
    USE SIGNAL ;
    PORT
      LAYER M5 ;
        RECT  95.52 30.156 95.544 30.24 ;
    END
  END xb[43]
  PIN xb[44]
    DIRECTION OUTPUT ;
    USE SIGNAL ;
    PORT
      LAYER M5 ;
        RECT  95.664 30.156 95.688 30.24 ;
    END
  END xb[44]
  PIN xb[45]
    DIRECTION OUTPUT ;
    USE SIGNAL ;
    PORT
      LAYER M5 ;
        RECT  95.808 30.156 95.832 30.24 ;
    END
  END xb[45]
  PIN xb[46]
    DIRECTION OUTPUT ;
    USE SIGNAL ;
    PORT
      LAYER M5 ;
        RECT  95.952 30.156 95.976 30.24 ;
    END
  END xb[46]
  PIN xb[47]
    DIRECTION OUTPUT ;
    USE SIGNAL ;
    PORT
      LAYER M5 ;
        RECT  96.096 30.156 96.12 30.24 ;
    END
  END xb[47]
  PIN xb[48]
    DIRECTION OUTPUT ;
    USE SIGNAL ;
    PORT
      LAYER M5 ;
        RECT  96.24 30.156 96.264 30.24 ;
    END
  END xb[48]
  PIN xb[49]
    DIRECTION OUTPUT ;
    USE SIGNAL ;
    PORT
      LAYER M5 ;
        RECT  96.384 30.156 96.408 30.24 ;
    END
  END xb[49]
  PIN xb[4]
    DIRECTION OUTPUT ;
    USE SIGNAL ;
    PORT
      LAYER M5 ;
        RECT  89.904 30.156 89.928 30.24 ;
    END
  END xb[4]
  PIN xb[50]
    DIRECTION OUTPUT ;
    USE SIGNAL ;
    PORT
      LAYER M5 ;
        RECT  96.528 30.156 96.552 30.24 ;
    END
  END xb[50]
  PIN xb[51]
    DIRECTION OUTPUT ;
    USE SIGNAL ;
    PORT
      LAYER M5 ;
        RECT  96.672 30.156 96.696 30.24 ;
    END
  END xb[51]
  PIN xb[52]
    DIRECTION OUTPUT ;
    USE SIGNAL ;
    PORT
      LAYER M5 ;
        RECT  96.816 30.156 96.84 30.24 ;
    END
  END xb[52]
  PIN xb[53]
    DIRECTION OUTPUT ;
    USE SIGNAL ;
    PORT
      LAYER M5 ;
        RECT  96.96 30.156 96.984 30.24 ;
    END
  END xb[53]
  PIN xb[54]
    DIRECTION OUTPUT ;
    USE SIGNAL ;
    PORT
      LAYER M5 ;
        RECT  97.104 30.156 97.128 30.24 ;
    END
  END xb[54]
  PIN xb[55]
    DIRECTION OUTPUT ;
    USE SIGNAL ;
    PORT
      LAYER M5 ;
        RECT  97.248 30.156 97.272 30.24 ;
    END
  END xb[55]
  PIN xb[56]
    DIRECTION OUTPUT ;
    USE SIGNAL ;
    PORT
      LAYER M5 ;
        RECT  97.392 30.156 97.416 30.24 ;
    END
  END xb[56]
  PIN xb[57]
    DIRECTION OUTPUT ;
    USE SIGNAL ;
    PORT
      LAYER M5 ;
        RECT  97.536 30.156 97.56 30.24 ;
    END
  END xb[57]
  PIN xb[58]
    DIRECTION OUTPUT ;
    USE SIGNAL ;
    PORT
      LAYER M5 ;
        RECT  97.68 30.156 97.704 30.24 ;
    END
  END xb[58]
  PIN xb[59]
    DIRECTION OUTPUT ;
    USE SIGNAL ;
    PORT
      LAYER M5 ;
        RECT  97.824 30.156 97.848 30.24 ;
    END
  END xb[59]
  PIN xb[5]
    DIRECTION OUTPUT ;
    USE SIGNAL ;
    PORT
      LAYER M5 ;
        RECT  90.048 30.156 90.072 30.24 ;
    END
  END xb[5]
  PIN xb[60]
    DIRECTION OUTPUT ;
    USE SIGNAL ;
    PORT
      LAYER M5 ;
        RECT  97.968 30.156 97.992 30.24 ;
    END
  END xb[60]
  PIN xb[61]
    DIRECTION OUTPUT ;
    USE SIGNAL ;
    PORT
      LAYER M5 ;
        RECT  98.112 30.156 98.136 30.24 ;
    END
  END xb[61]
  PIN xb[62]
    DIRECTION OUTPUT ;
    USE SIGNAL ;
    PORT
      LAYER M5 ;
        RECT  98.256 30.156 98.28 30.24 ;
    END
  END xb[62]
  PIN xb[63]
    DIRECTION OUTPUT ;
    USE SIGNAL ;
    PORT
      LAYER M5 ;
        RECT  98.4 30.156 98.424 30.24 ;
    END
  END xb[63]
  PIN xb[64]
    DIRECTION OUTPUT ;
    USE SIGNAL ;
    PORT
      LAYER M5 ;
        RECT  98.544 30.156 98.568 30.24 ;
    END
  END xb[64]
  PIN xb[65]
    DIRECTION OUTPUT ;
    USE SIGNAL ;
    PORT
      LAYER M5 ;
        RECT  98.688 30.156 98.712 30.24 ;
    END
  END xb[65]
  PIN xb[66]
    DIRECTION OUTPUT ;
    USE SIGNAL ;
    PORT
      LAYER M5 ;
        RECT  98.832 30.156 98.856 30.24 ;
    END
  END xb[66]
  PIN xb[67]
    DIRECTION OUTPUT ;
    USE SIGNAL ;
    PORT
      LAYER M5 ;
        RECT  98.976 30.156 99 30.24 ;
    END
  END xb[67]
  PIN xb[68]
    DIRECTION OUTPUT ;
    USE SIGNAL ;
    PORT
      LAYER M5 ;
        RECT  99.12 30.156 99.144 30.24 ;
    END
  END xb[68]
  PIN xb[69]
    DIRECTION OUTPUT ;
    USE SIGNAL ;
    PORT
      LAYER M5 ;
        RECT  99.264 30.156 99.288 30.24 ;
    END
  END xb[69]
  PIN xb[6]
    DIRECTION OUTPUT ;
    USE SIGNAL ;
    PORT
      LAYER M5 ;
        RECT  90.192 30.156 90.216 30.24 ;
    END
  END xb[6]
  PIN xb[70]
    DIRECTION OUTPUT ;
    USE SIGNAL ;
    PORT
      LAYER M5 ;
        RECT  99.408 30.156 99.432 30.24 ;
    END
  END xb[70]
  PIN xb[71]
    DIRECTION OUTPUT ;
    USE SIGNAL ;
    PORT
      LAYER M5 ;
        RECT  99.552 30.156 99.576 30.24 ;
    END
  END xb[71]
  PIN xb[72]
    DIRECTION OUTPUT ;
    USE SIGNAL ;
    PORT
      LAYER M5 ;
        RECT  99.696 30.156 99.72 30.24 ;
    END
  END xb[72]
  PIN xb[73]
    DIRECTION OUTPUT ;
    USE SIGNAL ;
    PORT
      LAYER M5 ;
        RECT  99.84 30.156 99.864 30.24 ;
    END
  END xb[73]
  PIN xb[74]
    DIRECTION OUTPUT ;
    USE SIGNAL ;
    PORT
      LAYER M5 ;
        RECT  99.984 30.156 100.008 30.24 ;
    END
  END xb[74]
  PIN xb[75]
    DIRECTION OUTPUT ;
    USE SIGNAL ;
    PORT
      LAYER M5 ;
        RECT  100.128 30.156 100.152 30.24 ;
    END
  END xb[75]
  PIN xb[76]
    DIRECTION OUTPUT ;
    USE SIGNAL ;
    PORT
      LAYER M5 ;
        RECT  100.272 30.156 100.296 30.24 ;
    END
  END xb[76]
  PIN xb[77]
    DIRECTION OUTPUT ;
    USE SIGNAL ;
    PORT
      LAYER M5 ;
        RECT  100.416 30.156 100.44 30.24 ;
    END
  END xb[77]
  PIN xb[78]
    DIRECTION OUTPUT ;
    USE SIGNAL ;
    PORT
      LAYER M5 ;
        RECT  100.56 30.156 100.584 30.24 ;
    END
  END xb[78]
  PIN xb[79]
    DIRECTION OUTPUT ;
    USE SIGNAL ;
    PORT
      LAYER M5 ;
        RECT  100.704 30.156 100.728 30.24 ;
    END
  END xb[79]
  PIN xb[7]
    DIRECTION OUTPUT ;
    USE SIGNAL ;
    PORT
      LAYER M5 ;
        RECT  90.336 30.156 90.36 30.24 ;
    END
  END xb[7]
  PIN xb[80]
    DIRECTION OUTPUT ;
    USE SIGNAL ;
    PORT
      LAYER M5 ;
        RECT  100.848 30.156 100.872 30.24 ;
    END
  END xb[80]
  PIN xb[81]
    DIRECTION OUTPUT ;
    USE SIGNAL ;
    PORT
      LAYER M5 ;
        RECT  100.992 30.156 101.016 30.24 ;
    END
  END xb[81]
  PIN xb[82]
    DIRECTION OUTPUT ;
    USE SIGNAL ;
    PORT
      LAYER M5 ;
        RECT  101.136 30.156 101.16 30.24 ;
    END
  END xb[82]
  PIN xb[83]
    DIRECTION OUTPUT ;
    USE SIGNAL ;
    PORT
      LAYER M5 ;
        RECT  101.28 30.156 101.304 30.24 ;
    END
  END xb[83]
  PIN xb[84]
    DIRECTION OUTPUT ;
    USE SIGNAL ;
    PORT
      LAYER M5 ;
        RECT  101.424 30.156 101.448 30.24 ;
    END
  END xb[84]
  PIN xb[85]
    DIRECTION OUTPUT ;
    USE SIGNAL ;
    PORT
      LAYER M5 ;
        RECT  101.568 30.156 101.592 30.24 ;
    END
  END xb[85]
  PIN xb[86]
    DIRECTION OUTPUT ;
    USE SIGNAL ;
    PORT
      LAYER M5 ;
        RECT  101.712 30.156 101.736 30.24 ;
    END
  END xb[86]
  PIN xb[87]
    DIRECTION OUTPUT ;
    USE SIGNAL ;
    PORT
      LAYER M5 ;
        RECT  101.856 30.156 101.88 30.24 ;
    END
  END xb[87]
  PIN xb[88]
    DIRECTION OUTPUT ;
    USE SIGNAL ;
    PORT
      LAYER M5 ;
        RECT  102 30.156 102.024 30.24 ;
    END
  END xb[88]
  PIN xb[89]
    DIRECTION OUTPUT ;
    USE SIGNAL ;
    PORT
      LAYER M5 ;
        RECT  102.144 30.156 102.168 30.24 ;
    END
  END xb[89]
  PIN xb[8]
    DIRECTION OUTPUT ;
    USE SIGNAL ;
    PORT
      LAYER M5 ;
        RECT  90.48 30.156 90.504 30.24 ;
    END
  END xb[8]
  PIN xb[90]
    DIRECTION OUTPUT ;
    USE SIGNAL ;
    PORT
      LAYER M5 ;
        RECT  102.288 30.156 102.312 30.24 ;
    END
  END xb[90]
  PIN xb[91]
    DIRECTION OUTPUT ;
    USE SIGNAL ;
    PORT
      LAYER M5 ;
        RECT  102.432 30.156 102.456 30.24 ;
    END
  END xb[91]
  PIN xb[92]
    DIRECTION OUTPUT ;
    USE SIGNAL ;
    PORT
      LAYER M5 ;
        RECT  102.576 30.156 102.6 30.24 ;
    END
  END xb[92]
  PIN xb[93]
    DIRECTION OUTPUT ;
    USE SIGNAL ;
    PORT
      LAYER M5 ;
        RECT  102.72 30.156 102.744 30.24 ;
    END
  END xb[93]
  PIN xb[94]
    DIRECTION OUTPUT ;
    USE SIGNAL ;
    PORT
      LAYER M5 ;
        RECT  102.864 30.156 102.888 30.24 ;
    END
  END xb[94]
  PIN xb[95]
    DIRECTION OUTPUT ;
    USE SIGNAL ;
    PORT
      LAYER M5 ;
        RECT  103.008 30.156 103.032 30.24 ;
    END
  END xb[95]
  PIN xb[96]
    DIRECTION OUTPUT ;
    USE SIGNAL ;
    PORT
      LAYER M5 ;
        RECT  103.152 30.156 103.176 30.24 ;
    END
  END xb[96]
  PIN xb[97]
    DIRECTION OUTPUT ;
    USE SIGNAL ;
    PORT
      LAYER M5 ;
        RECT  103.296 30.156 103.32 30.24 ;
    END
  END xb[97]
  PIN xb[98]
    DIRECTION OUTPUT ;
    USE SIGNAL ;
    PORT
      LAYER M5 ;
        RECT  103.44 30.156 103.464 30.24 ;
    END
  END xb[98]
  PIN xb[99]
    DIRECTION OUTPUT ;
    USE SIGNAL ;
    PORT
      LAYER M5 ;
        RECT  103.584 30.156 103.608 30.24 ;
    END
  END xb[99]
  PIN xb[9]
    DIRECTION OUTPUT ;
    USE SIGNAL ;
    PORT
      LAYER M5 ;
        RECT  90.624 30.156 90.648 30.24 ;
    END
  END xb[9]
  PIN xbi[0]
    DIRECTION INPUT ;
    USE SIGNAL ;
    PORT
      LAYER M5 ;
        RECT  92.16 0 92.184 0.084 ;
    END
  END xbi[0]
  PIN xbi[100]
    DIRECTION INPUT ;
    USE SIGNAL ;
    PORT
      LAYER M5 ;
        RECT  106.56 0 106.584 0.084 ;
    END
  END xbi[100]
  PIN xbi[101]
    DIRECTION INPUT ;
    USE SIGNAL ;
    PORT
      LAYER M5 ;
        RECT  106.704 0 106.728 0.084 ;
    END
  END xbi[101]
  PIN xbi[102]
    DIRECTION INPUT ;
    USE SIGNAL ;
    PORT
      LAYER M5 ;
        RECT  106.848 0 106.872 0.084 ;
    END
  END xbi[102]
  PIN xbi[103]
    DIRECTION INPUT ;
    USE SIGNAL ;
    PORT
      LAYER M5 ;
        RECT  106.992 0 107.016 0.084 ;
    END
  END xbi[103]
  PIN xbi[104]
    DIRECTION INPUT ;
    USE SIGNAL ;
    PORT
      LAYER M5 ;
        RECT  107.136 0 107.16 0.084 ;
    END
  END xbi[104]
  PIN xbi[105]
    DIRECTION INPUT ;
    USE SIGNAL ;
    PORT
      LAYER M5 ;
        RECT  107.28 0 107.304 0.084 ;
    END
  END xbi[105]
  PIN xbi[106]
    DIRECTION INPUT ;
    USE SIGNAL ;
    PORT
      LAYER M5 ;
        RECT  107.424 0 107.448 0.084 ;
    END
  END xbi[106]
  PIN xbi[107]
    DIRECTION INPUT ;
    USE SIGNAL ;
    PORT
      LAYER M5 ;
        RECT  107.568 0 107.592 0.084 ;
    END
  END xbi[107]
  PIN xbi[108]
    DIRECTION INPUT ;
    USE SIGNAL ;
    PORT
      LAYER M5 ;
        RECT  107.712 0 107.736 0.084 ;
    END
  END xbi[108]
  PIN xbi[109]
    DIRECTION INPUT ;
    USE SIGNAL ;
    PORT
      LAYER M5 ;
        RECT  107.856 0 107.88 0.084 ;
    END
  END xbi[109]
  PIN xbi[10]
    DIRECTION INPUT ;
    USE SIGNAL ;
    PORT
      LAYER M5 ;
        RECT  93.6 0 93.624 0.084 ;
    END
  END xbi[10]
  PIN xbi[110]
    DIRECTION INPUT ;
    USE SIGNAL ;
    PORT
      LAYER M5 ;
        RECT  108 0 108.024 0.084 ;
    END
  END xbi[110]
  PIN xbi[111]
    DIRECTION INPUT ;
    USE SIGNAL ;
    PORT
      LAYER M5 ;
        RECT  108.144 0 108.168 0.084 ;
    END
  END xbi[111]
  PIN xbi[112]
    DIRECTION INPUT ;
    USE SIGNAL ;
    PORT
      LAYER M5 ;
        RECT  108.288 0 108.312 0.084 ;
    END
  END xbi[112]
  PIN xbi[113]
    DIRECTION INPUT ;
    USE SIGNAL ;
    PORT
      LAYER M5 ;
        RECT  108.432 0 108.456 0.084 ;
    END
  END xbi[113]
  PIN xbi[114]
    DIRECTION INPUT ;
    USE SIGNAL ;
    PORT
      LAYER M5 ;
        RECT  108.576 0 108.6 0.084 ;
    END
  END xbi[114]
  PIN xbi[115]
    DIRECTION INPUT ;
    USE SIGNAL ;
    PORT
      LAYER M5 ;
        RECT  108.72 0 108.744 0.084 ;
    END
  END xbi[115]
  PIN xbi[116]
    DIRECTION INPUT ;
    USE SIGNAL ;
    PORT
      LAYER M5 ;
        RECT  108.864 0 108.888 0.084 ;
    END
  END xbi[116]
  PIN xbi[117]
    DIRECTION INPUT ;
    USE SIGNAL ;
    PORT
      LAYER M5 ;
        RECT  109.008 0 109.032 0.084 ;
    END
  END xbi[117]
  PIN xbi[118]
    DIRECTION INPUT ;
    USE SIGNAL ;
    PORT
      LAYER M5 ;
        RECT  109.152 0 109.176 0.084 ;
    END
  END xbi[118]
  PIN xbi[119]
    DIRECTION INPUT ;
    USE SIGNAL ;
    PORT
      LAYER M5 ;
        RECT  109.296 0 109.32 0.084 ;
    END
  END xbi[119]
  PIN xbi[11]
    DIRECTION INPUT ;
    USE SIGNAL ;
    PORT
      LAYER M5 ;
        RECT  93.744 0 93.768 0.084 ;
    END
  END xbi[11]
  PIN xbi[120]
    DIRECTION INPUT ;
    USE SIGNAL ;
    PORT
      LAYER M5 ;
        RECT  109.44 0 109.464 0.084 ;
    END
  END xbi[120]
  PIN xbi[121]
    DIRECTION INPUT ;
    USE SIGNAL ;
    PORT
      LAYER M5 ;
        RECT  109.584 0 109.608 0.084 ;
    END
  END xbi[121]
  PIN xbi[122]
    DIRECTION INPUT ;
    USE SIGNAL ;
    PORT
      LAYER M5 ;
        RECT  109.728 0 109.752 0.084 ;
    END
  END xbi[122]
  PIN xbi[123]
    DIRECTION INPUT ;
    USE SIGNAL ;
    PORT
      LAYER M5 ;
        RECT  109.872 0 109.896 0.084 ;
    END
  END xbi[123]
  PIN xbi[124]
    DIRECTION INPUT ;
    USE SIGNAL ;
    PORT
      LAYER M5 ;
        RECT  110.016 0 110.04 0.084 ;
    END
  END xbi[124]
  PIN xbi[125]
    DIRECTION INPUT ;
    USE SIGNAL ;
    PORT
      LAYER M5 ;
        RECT  110.16 0 110.184 0.084 ;
    END
  END xbi[125]
  PIN xbi[126]
    DIRECTION INPUT ;
    USE SIGNAL ;
    PORT
      LAYER M5 ;
        RECT  110.304 0 110.328 0.084 ;
    END
  END xbi[126]
  PIN xbi[127]
    DIRECTION INPUT ;
    USE SIGNAL ;
    PORT
      LAYER M5 ;
        RECT  110.448 0 110.472 0.084 ;
    END
  END xbi[127]
  PIN xbi[128]
    DIRECTION INPUT ;
    USE SIGNAL ;
    PORT
      LAYER M5 ;
        RECT  110.592 0 110.616 0.084 ;
    END
  END xbi[128]
  PIN xbi[129]
    DIRECTION INPUT ;
    USE SIGNAL ;
    PORT
      LAYER M5 ;
        RECT  110.736 0 110.76 0.084 ;
    END
  END xbi[129]
  PIN xbi[12]
    DIRECTION INPUT ;
    USE SIGNAL ;
    PORT
      LAYER M5 ;
        RECT  93.888 0 93.912 0.084 ;
    END
  END xbi[12]
  PIN xbi[130]
    DIRECTION INPUT ;
    USE SIGNAL ;
    PORT
      LAYER M5 ;
        RECT  110.88 0 110.904 0.084 ;
    END
  END xbi[130]
  PIN xbi[131]
    DIRECTION INPUT ;
    USE SIGNAL ;
    PORT
      LAYER M5 ;
        RECT  111.024 0 111.048 0.084 ;
    END
  END xbi[131]
  PIN xbi[132]
    DIRECTION INPUT ;
    USE SIGNAL ;
    PORT
      LAYER M5 ;
        RECT  111.168 0 111.192 0.084 ;
    END
  END xbi[132]
  PIN xbi[133]
    DIRECTION INPUT ;
    USE SIGNAL ;
    PORT
      LAYER M5 ;
        RECT  111.312 0 111.336 0.084 ;
    END
  END xbi[133]
  PIN xbi[134]
    DIRECTION INPUT ;
    USE SIGNAL ;
    PORT
      LAYER M5 ;
        RECT  111.456 0 111.48 0.084 ;
    END
  END xbi[134]
  PIN xbi[135]
    DIRECTION INPUT ;
    USE SIGNAL ;
    PORT
      LAYER M5 ;
        RECT  111.6 0 111.624 0.084 ;
    END
  END xbi[135]
  PIN xbi[136]
    DIRECTION INPUT ;
    USE SIGNAL ;
    PORT
      LAYER M5 ;
        RECT  111.744 0 111.768 0.084 ;
    END
  END xbi[136]
  PIN xbi[137]
    DIRECTION INPUT ;
    USE SIGNAL ;
    PORT
      LAYER M5 ;
        RECT  111.888 0 111.912 0.084 ;
    END
  END xbi[137]
  PIN xbi[138]
    DIRECTION INPUT ;
    USE SIGNAL ;
    PORT
      LAYER M5 ;
        RECT  112.032 0 112.056 0.084 ;
    END
  END xbi[138]
  PIN xbi[139]
    DIRECTION INPUT ;
    USE SIGNAL ;
    PORT
      LAYER M5 ;
        RECT  112.176 0 112.2 0.084 ;
    END
  END xbi[139]
  PIN xbi[13]
    DIRECTION INPUT ;
    USE SIGNAL ;
    PORT
      LAYER M5 ;
        RECT  94.032 0 94.056 0.084 ;
    END
  END xbi[13]
  PIN xbi[140]
    DIRECTION INPUT ;
    USE SIGNAL ;
    PORT
      LAYER M5 ;
        RECT  112.32 0 112.344 0.084 ;
    END
  END xbi[140]
  PIN xbi[141]
    DIRECTION INPUT ;
    USE SIGNAL ;
    PORT
      LAYER M5 ;
        RECT  112.464 0 112.488 0.084 ;
    END
  END xbi[141]
  PIN xbi[142]
    DIRECTION INPUT ;
    USE SIGNAL ;
    PORT
      LAYER M5 ;
        RECT  112.608 0 112.632 0.084 ;
    END
  END xbi[142]
  PIN xbi[143]
    DIRECTION INPUT ;
    USE SIGNAL ;
    PORT
      LAYER M5 ;
        RECT  112.752 0 112.776 0.084 ;
    END
  END xbi[143]
  PIN xbi[144]
    DIRECTION INPUT ;
    USE SIGNAL ;
    PORT
      LAYER M5 ;
        RECT  112.896 0 112.92 0.084 ;
    END
  END xbi[144]
  PIN xbi[145]
    DIRECTION INPUT ;
    USE SIGNAL ;
    PORT
      LAYER M5 ;
        RECT  113.04 0 113.064 0.084 ;
    END
  END xbi[145]
  PIN xbi[146]
    DIRECTION INPUT ;
    USE SIGNAL ;
    PORT
      LAYER M5 ;
        RECT  113.184 0 113.208 0.084 ;
    END
  END xbi[146]
  PIN xbi[147]
    DIRECTION INPUT ;
    USE SIGNAL ;
    PORT
      LAYER M5 ;
        RECT  113.328 0 113.352 0.084 ;
    END
  END xbi[147]
  PIN xbi[148]
    DIRECTION INPUT ;
    USE SIGNAL ;
    PORT
      LAYER M5 ;
        RECT  113.472 0 113.496 0.084 ;
    END
  END xbi[148]
  PIN xbi[149]
    DIRECTION INPUT ;
    USE SIGNAL ;
    PORT
      LAYER M5 ;
        RECT  113.616 0 113.64 0.084 ;
    END
  END xbi[149]
  PIN xbi[14]
    DIRECTION INPUT ;
    USE SIGNAL ;
    PORT
      LAYER M5 ;
        RECT  94.176 0 94.2 0.084 ;
    END
  END xbi[14]
  PIN xbi[150]
    DIRECTION INPUT ;
    USE SIGNAL ;
    PORT
      LAYER M5 ;
        RECT  113.76 0 113.784 0.084 ;
    END
  END xbi[150]
  PIN xbi[151]
    DIRECTION INPUT ;
    USE SIGNAL ;
    PORT
      LAYER M5 ;
        RECT  113.904 0 113.928 0.084 ;
    END
  END xbi[151]
  PIN xbi[152]
    DIRECTION INPUT ;
    USE SIGNAL ;
    PORT
      LAYER M5 ;
        RECT  114.048 0 114.072 0.084 ;
    END
  END xbi[152]
  PIN xbi[153]
    DIRECTION INPUT ;
    USE SIGNAL ;
    PORT
      LAYER M5 ;
        RECT  114.192 0 114.216 0.084 ;
    END
  END xbi[153]
  PIN xbi[154]
    DIRECTION INPUT ;
    USE SIGNAL ;
    PORT
      LAYER M5 ;
        RECT  114.336 0 114.36 0.084 ;
    END
  END xbi[154]
  PIN xbi[155]
    DIRECTION INPUT ;
    USE SIGNAL ;
    PORT
      LAYER M5 ;
        RECT  114.48 0 114.504 0.084 ;
    END
  END xbi[155]
  PIN xbi[156]
    DIRECTION INPUT ;
    USE SIGNAL ;
    PORT
      LAYER M5 ;
        RECT  114.624 0 114.648 0.084 ;
    END
  END xbi[156]
  PIN xbi[157]
    DIRECTION INPUT ;
    USE SIGNAL ;
    PORT
      LAYER M5 ;
        RECT  114.768 0 114.792 0.084 ;
    END
  END xbi[157]
  PIN xbi[158]
    DIRECTION INPUT ;
    USE SIGNAL ;
    PORT
      LAYER M5 ;
        RECT  114.912 0 114.936 0.084 ;
    END
  END xbi[158]
  PIN xbi[159]
    DIRECTION INPUT ;
    USE SIGNAL ;
    PORT
      LAYER M5 ;
        RECT  115.056 0 115.08 0.084 ;
    END
  END xbi[159]
  PIN xbi[15]
    DIRECTION INPUT ;
    USE SIGNAL ;
    PORT
      LAYER M5 ;
        RECT  94.32 0 94.344 0.084 ;
    END
  END xbi[15]
  PIN xbi[160]
    DIRECTION INPUT ;
    USE SIGNAL ;
    PORT
      LAYER M5 ;
        RECT  115.2 0 115.224 0.084 ;
    END
  END xbi[160]
  PIN xbi[161]
    DIRECTION INPUT ;
    USE SIGNAL ;
    PORT
      LAYER M5 ;
        RECT  115.344 0 115.368 0.084 ;
    END
  END xbi[161]
  PIN xbi[162]
    DIRECTION INPUT ;
    USE SIGNAL ;
    PORT
      LAYER M5 ;
        RECT  115.488 0 115.512 0.084 ;
    END
  END xbi[162]
  PIN xbi[163]
    DIRECTION INPUT ;
    USE SIGNAL ;
    PORT
      LAYER M5 ;
        RECT  115.632 0 115.656 0.084 ;
    END
  END xbi[163]
  PIN xbi[164]
    DIRECTION INPUT ;
    USE SIGNAL ;
    PORT
      LAYER M5 ;
        RECT  115.776 0 115.8 0.084 ;
    END
  END xbi[164]
  PIN xbi[165]
    DIRECTION INPUT ;
    USE SIGNAL ;
    PORT
      LAYER M5 ;
        RECT  115.92 0 115.944 0.084 ;
    END
  END xbi[165]
  PIN xbi[166]
    DIRECTION INPUT ;
    USE SIGNAL ;
    PORT
      LAYER M5 ;
        RECT  116.064 0 116.088 0.084 ;
    END
  END xbi[166]
  PIN xbi[167]
    DIRECTION INPUT ;
    USE SIGNAL ;
    PORT
      LAYER M5 ;
        RECT  116.208 0 116.232 0.084 ;
    END
  END xbi[167]
  PIN xbi[168]
    DIRECTION INPUT ;
    USE SIGNAL ;
    PORT
      LAYER M5 ;
        RECT  116.352 0 116.376 0.084 ;
    END
  END xbi[168]
  PIN xbi[169]
    DIRECTION INPUT ;
    USE SIGNAL ;
    PORT
      LAYER M5 ;
        RECT  116.496 0 116.52 0.084 ;
    END
  END xbi[169]
  PIN xbi[16]
    DIRECTION INPUT ;
    USE SIGNAL ;
    PORT
      LAYER M5 ;
        RECT  94.464 0 94.488 0.084 ;
    END
  END xbi[16]
  PIN xbi[170]
    DIRECTION INPUT ;
    USE SIGNAL ;
    PORT
      LAYER M5 ;
        RECT  116.64 0 116.664 0.084 ;
    END
  END xbi[170]
  PIN xbi[171]
    DIRECTION INPUT ;
    USE SIGNAL ;
    PORT
      LAYER M5 ;
        RECT  116.784 0 116.808 0.084 ;
    END
  END xbi[171]
  PIN xbi[172]
    DIRECTION INPUT ;
    USE SIGNAL ;
    PORT
      LAYER M5 ;
        RECT  116.928 0 116.952 0.084 ;
    END
  END xbi[172]
  PIN xbi[173]
    DIRECTION INPUT ;
    USE SIGNAL ;
    PORT
      LAYER M5 ;
        RECT  117.072 0 117.096 0.084 ;
    END
  END xbi[173]
  PIN xbi[174]
    DIRECTION INPUT ;
    USE SIGNAL ;
    PORT
      LAYER M5 ;
        RECT  117.216 0 117.24 0.084 ;
    END
  END xbi[174]
  PIN xbi[175]
    DIRECTION INPUT ;
    USE SIGNAL ;
    PORT
      LAYER M5 ;
        RECT  117.36 0 117.384 0.084 ;
    END
  END xbi[175]
  PIN xbi[176]
    DIRECTION INPUT ;
    USE SIGNAL ;
    PORT
      LAYER M5 ;
        RECT  117.504 0 117.528 0.084 ;
    END
  END xbi[176]
  PIN xbi[177]
    DIRECTION INPUT ;
    USE SIGNAL ;
    PORT
      LAYER M5 ;
        RECT  117.648 0 117.672 0.084 ;
    END
  END xbi[177]
  PIN xbi[178]
    DIRECTION INPUT ;
    USE SIGNAL ;
    PORT
      LAYER M5 ;
        RECT  117.792 0 117.816 0.084 ;
    END
  END xbi[178]
  PIN xbi[179]
    DIRECTION INPUT ;
    USE SIGNAL ;
    PORT
      LAYER M5 ;
        RECT  117.936 0 117.96 0.084 ;
    END
  END xbi[179]
  PIN xbi[17]
    DIRECTION INPUT ;
    USE SIGNAL ;
    PORT
      LAYER M5 ;
        RECT  94.608 0 94.632 0.084 ;
    END
  END xbi[17]
  PIN xbi[180]
    DIRECTION INPUT ;
    USE SIGNAL ;
    PORT
      LAYER M5 ;
        RECT  118.08 0 118.104 0.084 ;
    END
  END xbi[180]
  PIN xbi[181]
    DIRECTION INPUT ;
    USE SIGNAL ;
    PORT
      LAYER M5 ;
        RECT  118.224 0 118.248 0.084 ;
    END
  END xbi[181]
  PIN xbi[182]
    DIRECTION INPUT ;
    USE SIGNAL ;
    PORT
      LAYER M5 ;
        RECT  118.368 0 118.392 0.084 ;
    END
  END xbi[182]
  PIN xbi[183]
    DIRECTION INPUT ;
    USE SIGNAL ;
    PORT
      LAYER M5 ;
        RECT  118.512 0 118.536 0.084 ;
    END
  END xbi[183]
  PIN xbi[184]
    DIRECTION INPUT ;
    USE SIGNAL ;
    PORT
      LAYER M5 ;
        RECT  118.656 0 118.68 0.084 ;
    END
  END xbi[184]
  PIN xbi[185]
    DIRECTION INPUT ;
    USE SIGNAL ;
    PORT
      LAYER M5 ;
        RECT  118.8 0 118.824 0.084 ;
    END
  END xbi[185]
  PIN xbi[186]
    DIRECTION INPUT ;
    USE SIGNAL ;
    PORT
      LAYER M5 ;
        RECT  118.944 0 118.968 0.084 ;
    END
  END xbi[186]
  PIN xbi[187]
    DIRECTION INPUT ;
    USE SIGNAL ;
    PORT
      LAYER M5 ;
        RECT  119.088 0 119.112 0.084 ;
    END
  END xbi[187]
  PIN xbi[188]
    DIRECTION INPUT ;
    USE SIGNAL ;
    PORT
      LAYER M5 ;
        RECT  119.232 0 119.256 0.084 ;
    END
  END xbi[188]
  PIN xbi[189]
    DIRECTION INPUT ;
    USE SIGNAL ;
    PORT
      LAYER M5 ;
        RECT  119.376 0 119.4 0.084 ;
    END
  END xbi[189]
  PIN xbi[18]
    DIRECTION INPUT ;
    USE SIGNAL ;
    PORT
      LAYER M5 ;
        RECT  94.752 0 94.776 0.084 ;
    END
  END xbi[18]
  PIN xbi[190]
    DIRECTION INPUT ;
    USE SIGNAL ;
    PORT
      LAYER M5 ;
        RECT  119.52 0 119.544 0.084 ;
    END
  END xbi[190]
  PIN xbi[191]
    DIRECTION INPUT ;
    USE SIGNAL ;
    PORT
      LAYER M5 ;
        RECT  119.664 0 119.688 0.084 ;
    END
  END xbi[191]
  PIN xbi[192]
    DIRECTION INPUT ;
    USE SIGNAL ;
    PORT
      LAYER M5 ;
        RECT  119.808 0 119.832 0.084 ;
    END
  END xbi[192]
  PIN xbi[193]
    DIRECTION INPUT ;
    USE SIGNAL ;
    PORT
      LAYER M5 ;
        RECT  119.952 0 119.976 0.084 ;
    END
  END xbi[193]
  PIN xbi[194]
    DIRECTION INPUT ;
    USE SIGNAL ;
    PORT
      LAYER M5 ;
        RECT  120.096 0 120.12 0.084 ;
    END
  END xbi[194]
  PIN xbi[195]
    DIRECTION INPUT ;
    USE SIGNAL ;
    PORT
      LAYER M5 ;
        RECT  120.24 0 120.264 0.084 ;
    END
  END xbi[195]
  PIN xbi[196]
    DIRECTION INPUT ;
    USE SIGNAL ;
    PORT
      LAYER M5 ;
        RECT  120.384 0 120.408 0.084 ;
    END
  END xbi[196]
  PIN xbi[197]
    DIRECTION INPUT ;
    USE SIGNAL ;
    PORT
      LAYER M5 ;
        RECT  120.528 0 120.552 0.084 ;
    END
  END xbi[197]
  PIN xbi[198]
    DIRECTION INPUT ;
    USE SIGNAL ;
    PORT
      LAYER M5 ;
        RECT  120.672 0 120.696 0.084 ;
    END
  END xbi[198]
  PIN xbi[199]
    DIRECTION INPUT ;
    USE SIGNAL ;
    PORT
      LAYER M5 ;
        RECT  120.816 0 120.84 0.084 ;
    END
  END xbi[199]
  PIN xbi[19]
    DIRECTION INPUT ;
    USE SIGNAL ;
    PORT
      LAYER M5 ;
        RECT  94.896 0 94.92 0.084 ;
    END
  END xbi[19]
  PIN xbi[1]
    DIRECTION INPUT ;
    USE SIGNAL ;
    PORT
      LAYER M5 ;
        RECT  92.304 0 92.328 0.084 ;
    END
  END xbi[1]
  PIN xbi[200]
    DIRECTION INPUT ;
    USE SIGNAL ;
    PORT
      LAYER M5 ;
        RECT  120.96 0 120.984 0.084 ;
    END
  END xbi[200]
  PIN xbi[201]
    DIRECTION INPUT ;
    USE SIGNAL ;
    PORT
      LAYER M5 ;
        RECT  121.104 0 121.128 0.084 ;
    END
  END xbi[201]
  PIN xbi[202]
    DIRECTION INPUT ;
    USE SIGNAL ;
    PORT
      LAYER M5 ;
        RECT  121.248 0 121.272 0.084 ;
    END
  END xbi[202]
  PIN xbi[203]
    DIRECTION INPUT ;
    USE SIGNAL ;
    PORT
      LAYER M5 ;
        RECT  121.392 0 121.416 0.084 ;
    END
  END xbi[203]
  PIN xbi[204]
    DIRECTION INPUT ;
    USE SIGNAL ;
    PORT
      LAYER M5 ;
        RECT  121.536 0 121.56 0.084 ;
    END
  END xbi[204]
  PIN xbi[205]
    DIRECTION INPUT ;
    USE SIGNAL ;
    PORT
      LAYER M5 ;
        RECT  121.68 0 121.704 0.084 ;
    END
  END xbi[205]
  PIN xbi[206]
    DIRECTION INPUT ;
    USE SIGNAL ;
    PORT
      LAYER M5 ;
        RECT  121.824 0 121.848 0.084 ;
    END
  END xbi[206]
  PIN xbi[207]
    DIRECTION INPUT ;
    USE SIGNAL ;
    PORT
      LAYER M5 ;
        RECT  121.968 0 121.992 0.084 ;
    END
  END xbi[207]
  PIN xbi[208]
    DIRECTION INPUT ;
    USE SIGNAL ;
    PORT
      LAYER M5 ;
        RECT  122.112 0 122.136 0.084 ;
    END
  END xbi[208]
  PIN xbi[209]
    DIRECTION INPUT ;
    USE SIGNAL ;
    PORT
      LAYER M5 ;
        RECT  122.256 0 122.28 0.084 ;
    END
  END xbi[209]
  PIN xbi[20]
    DIRECTION INPUT ;
    USE SIGNAL ;
    PORT
      LAYER M5 ;
        RECT  95.04 0 95.064 0.084 ;
    END
  END xbi[20]
  PIN xbi[210]
    DIRECTION INPUT ;
    USE SIGNAL ;
    PORT
      LAYER M5 ;
        RECT  122.4 0 122.424 0.084 ;
    END
  END xbi[210]
  PIN xbi[211]
    DIRECTION INPUT ;
    USE SIGNAL ;
    PORT
      LAYER M5 ;
        RECT  122.544 0 122.568 0.084 ;
    END
  END xbi[211]
  PIN xbi[212]
    DIRECTION INPUT ;
    USE SIGNAL ;
    PORT
      LAYER M5 ;
        RECT  122.688 0 122.712 0.084 ;
    END
  END xbi[212]
  PIN xbi[213]
    DIRECTION INPUT ;
    USE SIGNAL ;
    PORT
      LAYER M5 ;
        RECT  122.832 0 122.856 0.084 ;
    END
  END xbi[213]
  PIN xbi[214]
    DIRECTION INPUT ;
    USE SIGNAL ;
    PORT
      LAYER M5 ;
        RECT  122.976 0 123 0.084 ;
    END
  END xbi[214]
  PIN xbi[215]
    DIRECTION INPUT ;
    USE SIGNAL ;
    PORT
      LAYER M5 ;
        RECT  123.12 0 123.144 0.084 ;
    END
  END xbi[215]
  PIN xbi[216]
    DIRECTION INPUT ;
    USE SIGNAL ;
    PORT
      LAYER M5 ;
        RECT  123.264 0 123.288 0.084 ;
    END
  END xbi[216]
  PIN xbi[217]
    DIRECTION INPUT ;
    USE SIGNAL ;
    PORT
      LAYER M5 ;
        RECT  123.408 0 123.432 0.084 ;
    END
  END xbi[217]
  PIN xbi[218]
    DIRECTION INPUT ;
    USE SIGNAL ;
    PORT
      LAYER M5 ;
        RECT  123.552 0 123.576 0.084 ;
    END
  END xbi[218]
  PIN xbi[219]
    DIRECTION INPUT ;
    USE SIGNAL ;
    PORT
      LAYER M5 ;
        RECT  123.696 0 123.72 0.084 ;
    END
  END xbi[219]
  PIN xbi[21]
    DIRECTION INPUT ;
    USE SIGNAL ;
    PORT
      LAYER M5 ;
        RECT  95.184 0 95.208 0.084 ;
    END
  END xbi[21]
  PIN xbi[220]
    DIRECTION INPUT ;
    USE SIGNAL ;
    PORT
      LAYER M5 ;
        RECT  123.84 0 123.864 0.084 ;
    END
  END xbi[220]
  PIN xbi[221]
    DIRECTION INPUT ;
    USE SIGNAL ;
    PORT
      LAYER M5 ;
        RECT  123.984 0 124.008 0.084 ;
    END
  END xbi[221]
  PIN xbi[222]
    DIRECTION INPUT ;
    USE SIGNAL ;
    PORT
      LAYER M5 ;
        RECT  124.128 0 124.152 0.084 ;
    END
  END xbi[222]
  PIN xbi[223]
    DIRECTION INPUT ;
    USE SIGNAL ;
    PORT
      LAYER M5 ;
        RECT  124.272 0 124.296 0.084 ;
    END
  END xbi[223]
  PIN xbi[224]
    DIRECTION INPUT ;
    USE SIGNAL ;
    PORT
      LAYER M5 ;
        RECT  124.416 0 124.44 0.084 ;
    END
  END xbi[224]
  PIN xbi[225]
    DIRECTION INPUT ;
    USE SIGNAL ;
    PORT
      LAYER M5 ;
        RECT  124.56 0 124.584 0.084 ;
    END
  END xbi[225]
  PIN xbi[226]
    DIRECTION INPUT ;
    USE SIGNAL ;
    PORT
      LAYER M5 ;
        RECT  124.704 0 124.728 0.084 ;
    END
  END xbi[226]
  PIN xbi[227]
    DIRECTION INPUT ;
    USE SIGNAL ;
    PORT
      LAYER M5 ;
        RECT  124.848 0 124.872 0.084 ;
    END
  END xbi[227]
  PIN xbi[228]
    DIRECTION INPUT ;
    USE SIGNAL ;
    PORT
      LAYER M5 ;
        RECT  124.992 0 125.016 0.084 ;
    END
  END xbi[228]
  PIN xbi[229]
    DIRECTION INPUT ;
    USE SIGNAL ;
    PORT
      LAYER M5 ;
        RECT  125.136 0 125.16 0.084 ;
    END
  END xbi[229]
  PIN xbi[22]
    DIRECTION INPUT ;
    USE SIGNAL ;
    PORT
      LAYER M5 ;
        RECT  95.328 0 95.352 0.084 ;
    END
  END xbi[22]
  PIN xbi[230]
    DIRECTION INPUT ;
    USE SIGNAL ;
    PORT
      LAYER M5 ;
        RECT  125.28 0 125.304 0.084 ;
    END
  END xbi[230]
  PIN xbi[231]
    DIRECTION INPUT ;
    USE SIGNAL ;
    PORT
      LAYER M5 ;
        RECT  125.424 0 125.448 0.084 ;
    END
  END xbi[231]
  PIN xbi[232]
    DIRECTION INPUT ;
    USE SIGNAL ;
    PORT
      LAYER M5 ;
        RECT  125.568 0 125.592 0.084 ;
    END
  END xbi[232]
  PIN xbi[233]
    DIRECTION INPUT ;
    USE SIGNAL ;
    PORT
      LAYER M5 ;
        RECT  125.712 0 125.736 0.084 ;
    END
  END xbi[233]
  PIN xbi[234]
    DIRECTION INPUT ;
    USE SIGNAL ;
    PORT
      LAYER M5 ;
        RECT  125.856 0 125.88 0.084 ;
    END
  END xbi[234]
  PIN xbi[235]
    DIRECTION INPUT ;
    USE SIGNAL ;
    PORT
      LAYER M5 ;
        RECT  126 0 126.024 0.084 ;
    END
  END xbi[235]
  PIN xbi[236]
    DIRECTION INPUT ;
    USE SIGNAL ;
    PORT
      LAYER M5 ;
        RECT  126.144 0 126.168 0.084 ;
    END
  END xbi[236]
  PIN xbi[237]
    DIRECTION INPUT ;
    USE SIGNAL ;
    PORT
      LAYER M5 ;
        RECT  126.288 0 126.312 0.084 ;
    END
  END xbi[237]
  PIN xbi[238]
    DIRECTION INPUT ;
    USE SIGNAL ;
    PORT
      LAYER M5 ;
        RECT  126.432 0 126.456 0.084 ;
    END
  END xbi[238]
  PIN xbi[239]
    DIRECTION INPUT ;
    USE SIGNAL ;
    PORT
      LAYER M5 ;
        RECT  126.576 0 126.6 0.084 ;
    END
  END xbi[239]
  PIN xbi[23]
    DIRECTION INPUT ;
    USE SIGNAL ;
    PORT
      LAYER M5 ;
        RECT  95.472 0 95.496 0.084 ;
    END
  END xbi[23]
  PIN xbi[240]
    DIRECTION INPUT ;
    USE SIGNAL ;
    PORT
      LAYER M5 ;
        RECT  126.72 0 126.744 0.084 ;
    END
  END xbi[240]
  PIN xbi[241]
    DIRECTION INPUT ;
    USE SIGNAL ;
    PORT
      LAYER M5 ;
        RECT  126.864 0 126.888 0.084 ;
    END
  END xbi[241]
  PIN xbi[242]
    DIRECTION INPUT ;
    USE SIGNAL ;
    PORT
      LAYER M5 ;
        RECT  127.008 0 127.032 0.084 ;
    END
  END xbi[242]
  PIN xbi[243]
    DIRECTION INPUT ;
    USE SIGNAL ;
    PORT
      LAYER M5 ;
        RECT  127.152 0 127.176 0.084 ;
    END
  END xbi[243]
  PIN xbi[244]
    DIRECTION INPUT ;
    USE SIGNAL ;
    PORT
      LAYER M5 ;
        RECT  127.296 0 127.32 0.084 ;
    END
  END xbi[244]
  PIN xbi[245]
    DIRECTION INPUT ;
    USE SIGNAL ;
    PORT
      LAYER M5 ;
        RECT  127.44 0 127.464 0.084 ;
    END
  END xbi[245]
  PIN xbi[246]
    DIRECTION INPUT ;
    USE SIGNAL ;
    PORT
      LAYER M5 ;
        RECT  127.584 0 127.608 0.084 ;
    END
  END xbi[246]
  PIN xbi[247]
    DIRECTION INPUT ;
    USE SIGNAL ;
    PORT
      LAYER M5 ;
        RECT  127.728 0 127.752 0.084 ;
    END
  END xbi[247]
  PIN xbi[248]
    DIRECTION INPUT ;
    USE SIGNAL ;
    PORT
      LAYER M5 ;
        RECT  127.872 0 127.896 0.084 ;
    END
  END xbi[248]
  PIN xbi[249]
    DIRECTION INPUT ;
    USE SIGNAL ;
    PORT
      LAYER M5 ;
        RECT  128.016 0 128.04 0.084 ;
    END
  END xbi[249]
  PIN xbi[24]
    DIRECTION INPUT ;
    USE SIGNAL ;
    PORT
      LAYER M5 ;
        RECT  95.616 0 95.64 0.084 ;
    END
  END xbi[24]
  PIN xbi[250]
    DIRECTION INPUT ;
    USE SIGNAL ;
    PORT
      LAYER M5 ;
        RECT  128.16 0 128.184 0.084 ;
    END
  END xbi[250]
  PIN xbi[251]
    DIRECTION INPUT ;
    USE SIGNAL ;
    PORT
      LAYER M5 ;
        RECT  128.304 0 128.328 0.084 ;
    END
  END xbi[251]
  PIN xbi[252]
    DIRECTION INPUT ;
    USE SIGNAL ;
    PORT
      LAYER M5 ;
        RECT  128.448 0 128.472 0.084 ;
    END
  END xbi[252]
  PIN xbi[253]
    DIRECTION INPUT ;
    USE SIGNAL ;
    PORT
      LAYER M5 ;
        RECT  128.592 0 128.616 0.084 ;
    END
  END xbi[253]
  PIN xbi[254]
    DIRECTION INPUT ;
    USE SIGNAL ;
    PORT
      LAYER M5 ;
        RECT  128.736 0 128.76 0.084 ;
    END
  END xbi[254]
  PIN xbi[255]
    DIRECTION INPUT ;
    USE SIGNAL ;
    PORT
      LAYER M5 ;
        RECT  128.88 0 128.904 0.084 ;
    END
  END xbi[255]
  PIN xbi[256]
    DIRECTION INPUT ;
    USE SIGNAL ;
    PORT
      LAYER M5 ;
        RECT  129.024 0 129.048 0.084 ;
    END
  END xbi[256]
  PIN xbi[257]
    DIRECTION INPUT ;
    USE SIGNAL ;
    PORT
      LAYER M5 ;
        RECT  129.168 0 129.192 0.084 ;
    END
  END xbi[257]
  PIN xbi[258]
    DIRECTION INPUT ;
    USE SIGNAL ;
    PORT
      LAYER M5 ;
        RECT  129.312 0 129.336 0.084 ;
    END
  END xbi[258]
  PIN xbi[259]
    DIRECTION INPUT ;
    USE SIGNAL ;
    PORT
      LAYER M5 ;
        RECT  129.456 0 129.48 0.084 ;
    END
  END xbi[259]
  PIN xbi[25]
    DIRECTION INPUT ;
    USE SIGNAL ;
    PORT
      LAYER M5 ;
        RECT  95.76 0 95.784 0.084 ;
    END
  END xbi[25]
  PIN xbi[260]
    DIRECTION INPUT ;
    USE SIGNAL ;
    PORT
      LAYER M5 ;
        RECT  129.6 0 129.624 0.084 ;
    END
  END xbi[260]
  PIN xbi[261]
    DIRECTION INPUT ;
    USE SIGNAL ;
    PORT
      LAYER M5 ;
        RECT  129.744 0 129.768 0.084 ;
    END
  END xbi[261]
  PIN xbi[262]
    DIRECTION INPUT ;
    USE SIGNAL ;
    PORT
      LAYER M5 ;
        RECT  129.888 0 129.912 0.084 ;
    END
  END xbi[262]
  PIN xbi[263]
    DIRECTION INPUT ;
    USE SIGNAL ;
    PORT
      LAYER M5 ;
        RECT  130.032 0 130.056 0.084 ;
    END
  END xbi[263]
  PIN xbi[264]
    DIRECTION INPUT ;
    USE SIGNAL ;
    PORT
      LAYER M5 ;
        RECT  130.176 0 130.2 0.084 ;
    END
  END xbi[264]
  PIN xbi[265]
    DIRECTION INPUT ;
    USE SIGNAL ;
    PORT
      LAYER M5 ;
        RECT  130.32 0 130.344 0.084 ;
    END
  END xbi[265]
  PIN xbi[26]
    DIRECTION INPUT ;
    USE SIGNAL ;
    PORT
      LAYER M5 ;
        RECT  95.904 0 95.928 0.084 ;
    END
  END xbi[26]
  PIN xbi[27]
    DIRECTION INPUT ;
    USE SIGNAL ;
    PORT
      LAYER M5 ;
        RECT  96.048 0 96.072 0.084 ;
    END
  END xbi[27]
  PIN xbi[28]
    DIRECTION INPUT ;
    USE SIGNAL ;
    PORT
      LAYER M5 ;
        RECT  96.192 0 96.216 0.084 ;
    END
  END xbi[28]
  PIN xbi[29]
    DIRECTION INPUT ;
    USE SIGNAL ;
    PORT
      LAYER M5 ;
        RECT  96.336 0 96.36 0.084 ;
    END
  END xbi[29]
  PIN xbi[2]
    DIRECTION INPUT ;
    USE SIGNAL ;
    PORT
      LAYER M5 ;
        RECT  92.448 0 92.472 0.084 ;
    END
  END xbi[2]
  PIN xbi[30]
    DIRECTION INPUT ;
    USE SIGNAL ;
    PORT
      LAYER M5 ;
        RECT  96.48 0 96.504 0.084 ;
    END
  END xbi[30]
  PIN xbi[31]
    DIRECTION INPUT ;
    USE SIGNAL ;
    PORT
      LAYER M5 ;
        RECT  96.624 0 96.648 0.084 ;
    END
  END xbi[31]
  PIN xbi[32]
    DIRECTION INPUT ;
    USE SIGNAL ;
    PORT
      LAYER M5 ;
        RECT  96.768 0 96.792 0.084 ;
    END
  END xbi[32]
  PIN xbi[33]
    DIRECTION INPUT ;
    USE SIGNAL ;
    PORT
      LAYER M5 ;
        RECT  96.912 0 96.936 0.084 ;
    END
  END xbi[33]
  PIN xbi[34]
    DIRECTION INPUT ;
    USE SIGNAL ;
    PORT
      LAYER M5 ;
        RECT  97.056 0 97.08 0.084 ;
    END
  END xbi[34]
  PIN xbi[35]
    DIRECTION INPUT ;
    USE SIGNAL ;
    PORT
      LAYER M5 ;
        RECT  97.2 0 97.224 0.084 ;
    END
  END xbi[35]
  PIN xbi[36]
    DIRECTION INPUT ;
    USE SIGNAL ;
    PORT
      LAYER M5 ;
        RECT  97.344 0 97.368 0.084 ;
    END
  END xbi[36]
  PIN xbi[37]
    DIRECTION INPUT ;
    USE SIGNAL ;
    PORT
      LAYER M5 ;
        RECT  97.488 0 97.512 0.084 ;
    END
  END xbi[37]
  PIN xbi[38]
    DIRECTION INPUT ;
    USE SIGNAL ;
    PORT
      LAYER M5 ;
        RECT  97.632 0 97.656 0.084 ;
    END
  END xbi[38]
  PIN xbi[39]
    DIRECTION INPUT ;
    USE SIGNAL ;
    PORT
      LAYER M5 ;
        RECT  97.776 0 97.8 0.084 ;
    END
  END xbi[39]
  PIN xbi[3]
    DIRECTION INPUT ;
    USE SIGNAL ;
    PORT
      LAYER M5 ;
        RECT  92.592 0 92.616 0.084 ;
    END
  END xbi[3]
  PIN xbi[40]
    DIRECTION INPUT ;
    USE SIGNAL ;
    PORT
      LAYER M5 ;
        RECT  97.92 0 97.944 0.084 ;
    END
  END xbi[40]
  PIN xbi[41]
    DIRECTION INPUT ;
    USE SIGNAL ;
    PORT
      LAYER M5 ;
        RECT  98.064 0 98.088 0.084 ;
    END
  END xbi[41]
  PIN xbi[42]
    DIRECTION INPUT ;
    USE SIGNAL ;
    PORT
      LAYER M5 ;
        RECT  98.208 0 98.232 0.084 ;
    END
  END xbi[42]
  PIN xbi[43]
    DIRECTION INPUT ;
    USE SIGNAL ;
    PORT
      LAYER M5 ;
        RECT  98.352 0 98.376 0.084 ;
    END
  END xbi[43]
  PIN xbi[44]
    DIRECTION INPUT ;
    USE SIGNAL ;
    PORT
      LAYER M5 ;
        RECT  98.496 0 98.52 0.084 ;
    END
  END xbi[44]
  PIN xbi[45]
    DIRECTION INPUT ;
    USE SIGNAL ;
    PORT
      LAYER M5 ;
        RECT  98.64 0 98.664 0.084 ;
    END
  END xbi[45]
  PIN xbi[46]
    DIRECTION INPUT ;
    USE SIGNAL ;
    PORT
      LAYER M5 ;
        RECT  98.784 0 98.808 0.084 ;
    END
  END xbi[46]
  PIN xbi[47]
    DIRECTION INPUT ;
    USE SIGNAL ;
    PORT
      LAYER M5 ;
        RECT  98.928 0 98.952 0.084 ;
    END
  END xbi[47]
  PIN xbi[48]
    DIRECTION INPUT ;
    USE SIGNAL ;
    PORT
      LAYER M5 ;
        RECT  99.072 0 99.096 0.084 ;
    END
  END xbi[48]
  PIN xbi[49]
    DIRECTION INPUT ;
    USE SIGNAL ;
    PORT
      LAYER M5 ;
        RECT  99.216 0 99.24 0.084 ;
    END
  END xbi[49]
  PIN xbi[4]
    DIRECTION INPUT ;
    USE SIGNAL ;
    PORT
      LAYER M5 ;
        RECT  92.736 0 92.76 0.084 ;
    END
  END xbi[4]
  PIN xbi[50]
    DIRECTION INPUT ;
    USE SIGNAL ;
    PORT
      LAYER M5 ;
        RECT  99.36 0 99.384 0.084 ;
    END
  END xbi[50]
  PIN xbi[51]
    DIRECTION INPUT ;
    USE SIGNAL ;
    PORT
      LAYER M5 ;
        RECT  99.504 0 99.528 0.084 ;
    END
  END xbi[51]
  PIN xbi[52]
    DIRECTION INPUT ;
    USE SIGNAL ;
    PORT
      LAYER M5 ;
        RECT  99.648 0 99.672 0.084 ;
    END
  END xbi[52]
  PIN xbi[53]
    DIRECTION INPUT ;
    USE SIGNAL ;
    PORT
      LAYER M5 ;
        RECT  99.792 0 99.816 0.084 ;
    END
  END xbi[53]
  PIN xbi[54]
    DIRECTION INPUT ;
    USE SIGNAL ;
    PORT
      LAYER M5 ;
        RECT  99.936 0 99.96 0.084 ;
    END
  END xbi[54]
  PIN xbi[55]
    DIRECTION INPUT ;
    USE SIGNAL ;
    PORT
      LAYER M5 ;
        RECT  100.08 0 100.104 0.084 ;
    END
  END xbi[55]
  PIN xbi[56]
    DIRECTION INPUT ;
    USE SIGNAL ;
    PORT
      LAYER M5 ;
        RECT  100.224 0 100.248 0.084 ;
    END
  END xbi[56]
  PIN xbi[57]
    DIRECTION INPUT ;
    USE SIGNAL ;
    PORT
      LAYER M5 ;
        RECT  100.368 0 100.392 0.084 ;
    END
  END xbi[57]
  PIN xbi[58]
    DIRECTION INPUT ;
    USE SIGNAL ;
    PORT
      LAYER M5 ;
        RECT  100.512 0 100.536 0.084 ;
    END
  END xbi[58]
  PIN xbi[59]
    DIRECTION INPUT ;
    USE SIGNAL ;
    PORT
      LAYER M5 ;
        RECT  100.656 0 100.68 0.084 ;
    END
  END xbi[59]
  PIN xbi[5]
    DIRECTION INPUT ;
    USE SIGNAL ;
    PORT
      LAYER M5 ;
        RECT  92.88 0 92.904 0.084 ;
    END
  END xbi[5]
  PIN xbi[60]
    DIRECTION INPUT ;
    USE SIGNAL ;
    PORT
      LAYER M5 ;
        RECT  100.8 0 100.824 0.084 ;
    END
  END xbi[60]
  PIN xbi[61]
    DIRECTION INPUT ;
    USE SIGNAL ;
    PORT
      LAYER M5 ;
        RECT  100.944 0 100.968 0.084 ;
    END
  END xbi[61]
  PIN xbi[62]
    DIRECTION INPUT ;
    USE SIGNAL ;
    PORT
      LAYER M5 ;
        RECT  101.088 0 101.112 0.084 ;
    END
  END xbi[62]
  PIN xbi[63]
    DIRECTION INPUT ;
    USE SIGNAL ;
    PORT
      LAYER M5 ;
        RECT  101.232 0 101.256 0.084 ;
    END
  END xbi[63]
  PIN xbi[64]
    DIRECTION INPUT ;
    USE SIGNAL ;
    PORT
      LAYER M5 ;
        RECT  101.376 0 101.4 0.084 ;
    END
  END xbi[64]
  PIN xbi[65]
    DIRECTION INPUT ;
    USE SIGNAL ;
    PORT
      LAYER M5 ;
        RECT  101.52 0 101.544 0.084 ;
    END
  END xbi[65]
  PIN xbi[66]
    DIRECTION INPUT ;
    USE SIGNAL ;
    PORT
      LAYER M5 ;
        RECT  101.664 0 101.688 0.084 ;
    END
  END xbi[66]
  PIN xbi[67]
    DIRECTION INPUT ;
    USE SIGNAL ;
    PORT
      LAYER M5 ;
        RECT  101.808 0 101.832 0.084 ;
    END
  END xbi[67]
  PIN xbi[68]
    DIRECTION INPUT ;
    USE SIGNAL ;
    PORT
      LAYER M5 ;
        RECT  101.952 0 101.976 0.084 ;
    END
  END xbi[68]
  PIN xbi[69]
    DIRECTION INPUT ;
    USE SIGNAL ;
    PORT
      LAYER M5 ;
        RECT  102.096 0 102.12 0.084 ;
    END
  END xbi[69]
  PIN xbi[6]
    DIRECTION INPUT ;
    USE SIGNAL ;
    PORT
      LAYER M5 ;
        RECT  93.024 0 93.048 0.084 ;
    END
  END xbi[6]
  PIN xbi[70]
    DIRECTION INPUT ;
    USE SIGNAL ;
    PORT
      LAYER M5 ;
        RECT  102.24 0 102.264 0.084 ;
    END
  END xbi[70]
  PIN xbi[71]
    DIRECTION INPUT ;
    USE SIGNAL ;
    PORT
      LAYER M5 ;
        RECT  102.384 0 102.408 0.084 ;
    END
  END xbi[71]
  PIN xbi[72]
    DIRECTION INPUT ;
    USE SIGNAL ;
    PORT
      LAYER M5 ;
        RECT  102.528 0 102.552 0.084 ;
    END
  END xbi[72]
  PIN xbi[73]
    DIRECTION INPUT ;
    USE SIGNAL ;
    PORT
      LAYER M5 ;
        RECT  102.672 0 102.696 0.084 ;
    END
  END xbi[73]
  PIN xbi[74]
    DIRECTION INPUT ;
    USE SIGNAL ;
    PORT
      LAYER M5 ;
        RECT  102.816 0 102.84 0.084 ;
    END
  END xbi[74]
  PIN xbi[75]
    DIRECTION INPUT ;
    USE SIGNAL ;
    PORT
      LAYER M5 ;
        RECT  102.96 0 102.984 0.084 ;
    END
  END xbi[75]
  PIN xbi[76]
    DIRECTION INPUT ;
    USE SIGNAL ;
    PORT
      LAYER M5 ;
        RECT  103.104 0 103.128 0.084 ;
    END
  END xbi[76]
  PIN xbi[77]
    DIRECTION INPUT ;
    USE SIGNAL ;
    PORT
      LAYER M5 ;
        RECT  103.248 0 103.272 0.084 ;
    END
  END xbi[77]
  PIN xbi[78]
    DIRECTION INPUT ;
    USE SIGNAL ;
    PORT
      LAYER M5 ;
        RECT  103.392 0 103.416 0.084 ;
    END
  END xbi[78]
  PIN xbi[79]
    DIRECTION INPUT ;
    USE SIGNAL ;
    PORT
      LAYER M5 ;
        RECT  103.536 0 103.56 0.084 ;
    END
  END xbi[79]
  PIN xbi[7]
    DIRECTION INPUT ;
    USE SIGNAL ;
    PORT
      LAYER M5 ;
        RECT  93.168 0 93.192 0.084 ;
    END
  END xbi[7]
  PIN xbi[80]
    DIRECTION INPUT ;
    USE SIGNAL ;
    PORT
      LAYER M5 ;
        RECT  103.68 0 103.704 0.084 ;
    END
  END xbi[80]
  PIN xbi[81]
    DIRECTION INPUT ;
    USE SIGNAL ;
    PORT
      LAYER M5 ;
        RECT  103.824 0 103.848 0.084 ;
    END
  END xbi[81]
  PIN xbi[82]
    DIRECTION INPUT ;
    USE SIGNAL ;
    PORT
      LAYER M5 ;
        RECT  103.968 0 103.992 0.084 ;
    END
  END xbi[82]
  PIN xbi[83]
    DIRECTION INPUT ;
    USE SIGNAL ;
    PORT
      LAYER M5 ;
        RECT  104.112 0 104.136 0.084 ;
    END
  END xbi[83]
  PIN xbi[84]
    DIRECTION INPUT ;
    USE SIGNAL ;
    PORT
      LAYER M5 ;
        RECT  104.256 0 104.28 0.084 ;
    END
  END xbi[84]
  PIN xbi[85]
    DIRECTION INPUT ;
    USE SIGNAL ;
    PORT
      LAYER M5 ;
        RECT  104.4 0 104.424 0.084 ;
    END
  END xbi[85]
  PIN xbi[86]
    DIRECTION INPUT ;
    USE SIGNAL ;
    PORT
      LAYER M5 ;
        RECT  104.544 0 104.568 0.084 ;
    END
  END xbi[86]
  PIN xbi[87]
    DIRECTION INPUT ;
    USE SIGNAL ;
    PORT
      LAYER M5 ;
        RECT  104.688 0 104.712 0.084 ;
    END
  END xbi[87]
  PIN xbi[88]
    DIRECTION INPUT ;
    USE SIGNAL ;
    PORT
      LAYER M5 ;
        RECT  104.832 0 104.856 0.084 ;
    END
  END xbi[88]
  PIN xbi[89]
    DIRECTION INPUT ;
    USE SIGNAL ;
    PORT
      LAYER M5 ;
        RECT  104.976 0 105 0.084 ;
    END
  END xbi[89]
  PIN xbi[8]
    DIRECTION INPUT ;
    USE SIGNAL ;
    PORT
      LAYER M5 ;
        RECT  93.312 0 93.336 0.084 ;
    END
  END xbi[8]
  PIN xbi[90]
    DIRECTION INPUT ;
    USE SIGNAL ;
    PORT
      LAYER M5 ;
        RECT  105.12 0 105.144 0.084 ;
    END
  END xbi[90]
  PIN xbi[91]
    DIRECTION INPUT ;
    USE SIGNAL ;
    PORT
      LAYER M5 ;
        RECT  105.264 0 105.288 0.084 ;
    END
  END xbi[91]
  PIN xbi[92]
    DIRECTION INPUT ;
    USE SIGNAL ;
    PORT
      LAYER M5 ;
        RECT  105.408 0 105.432 0.084 ;
    END
  END xbi[92]
  PIN xbi[93]
    DIRECTION INPUT ;
    USE SIGNAL ;
    PORT
      LAYER M5 ;
        RECT  105.552 0 105.576 0.084 ;
    END
  END xbi[93]
  PIN xbi[94]
    DIRECTION INPUT ;
    USE SIGNAL ;
    PORT
      LAYER M5 ;
        RECT  105.696 0 105.72 0.084 ;
    END
  END xbi[94]
  PIN xbi[95]
    DIRECTION INPUT ;
    USE SIGNAL ;
    PORT
      LAYER M5 ;
        RECT  105.84 0 105.864 0.084 ;
    END
  END xbi[95]
  PIN xbi[96]
    DIRECTION INPUT ;
    USE SIGNAL ;
    PORT
      LAYER M5 ;
        RECT  105.984 0 106.008 0.084 ;
    END
  END xbi[96]
  PIN xbi[97]
    DIRECTION INPUT ;
    USE SIGNAL ;
    PORT
      LAYER M5 ;
        RECT  106.128 0 106.152 0.084 ;
    END
  END xbi[97]
  PIN xbi[98]
    DIRECTION INPUT ;
    USE SIGNAL ;
    PORT
      LAYER M5 ;
        RECT  106.272 0 106.296 0.084 ;
    END
  END xbi[98]
  PIN xbi[99]
    DIRECTION INPUT ;
    USE SIGNAL ;
    PORT
      LAYER M5 ;
        RECT  106.416 0 106.44 0.084 ;
    END
  END xbi[99]
  PIN xbi[9]
    DIRECTION INPUT ;
    USE SIGNAL ;
    PORT
      LAYER M5 ;
        RECT  93.456 0 93.48 0.084 ;
    END
  END xbi[9]
  PIN VDD
    DIRECTION INOUT ;
    USE POWER ;
    PORT
      LAYER M5 ;
        RECT  169.992 2.151 170.112 28.089 ;
        RECT  167.292 2.151 167.412 28.089 ;
        RECT  164.592 2.151 164.712 28.089 ;
        RECT  161.892 2.151 162.012 28.089 ;
        RECT  159.192 2.151 159.312 28.089 ;
        RECT  156.492 2.151 156.612 28.089 ;
        RECT  153.792 2.151 153.912 28.089 ;
        RECT  151.092 2.151 151.212 28.089 ;
        RECT  148.392 2.151 148.512 28.089 ;
        RECT  145.692 2.151 145.812 28.089 ;
        RECT  142.992 2.151 143.112 28.089 ;
        RECT  140.292 2.151 140.412 28.089 ;
        RECT  137.592 2.151 137.712 28.089 ;
        RECT  134.892 2.151 135.012 28.089 ;
        RECT  132.192 2.151 132.312 28.089 ;
        RECT  129.492 2.151 129.612 28.089 ;
        RECT  126.792 2.151 126.912 28.089 ;
        RECT  124.092 2.151 124.212 28.089 ;
        RECT  121.392 2.151 121.512 28.089 ;
        RECT  118.692 2.151 118.812 28.089 ;
        RECT  115.992 2.151 116.112 28.089 ;
        RECT  113.292 2.151 113.412 28.089 ;
        RECT  110.592 2.151 110.712 28.089 ;
        RECT  107.892 2.151 108.012 28.089 ;
        RECT  105.192 2.151 105.312 28.089 ;
        RECT  102.492 2.151 102.612 28.089 ;
        RECT  99.792 2.151 99.912 28.089 ;
        RECT  97.092 2.151 97.212 28.089 ;
        RECT  94.392 2.151 94.512 28.089 ;
        RECT  91.692 2.151 91.812 28.089 ;
        RECT  88.992 2.151 89.112 28.089 ;
        RECT  86.292 2.151 86.412 28.089 ;
        RECT  83.592 2.151 83.712 28.089 ;
        RECT  80.892 2.151 81.012 28.089 ;
        RECT  78.192 2.151 78.312 28.089 ;
        RECT  75.492 2.151 75.612 28.089 ;
        RECT  72.792 2.151 72.912 28.089 ;
        RECT  70.092 2.151 70.212 28.089 ;
        RECT  67.392 2.151 67.512 28.089 ;
        RECT  64.692 2.151 64.812 28.089 ;
        RECT  61.992 2.151 62.112 28.089 ;
        RECT  59.292 2.151 59.412 28.089 ;
        RECT  56.592 2.151 56.712 28.089 ;
        RECT  53.892 2.151 54.012 28.089 ;
        RECT  51.192 2.151 51.312 28.089 ;
        RECT  48.492 2.151 48.612 28.089 ;
        RECT  45.792 2.151 45.912 28.089 ;
        RECT  43.092 2.151 43.212 28.089 ;
        RECT  40.392 2.151 40.512 28.089 ;
        RECT  37.692 2.151 37.812 28.089 ;
        RECT  34.992 2.151 35.112 28.089 ;
        RECT  32.292 2.151 32.412 28.089 ;
        RECT  29.592 2.151 29.712 28.089 ;
        RECT  26.892 2.151 27.012 28.089 ;
        RECT  24.192 2.151 24.312 28.089 ;
        RECT  21.492 2.151 21.612 28.089 ;
        RECT  18.792 2.151 18.912 28.089 ;
        RECT  16.092 2.151 16.212 28.089 ;
        RECT  13.392 2.151 13.512 28.089 ;
        RECT  10.692 2.151 10.812 28.089 ;
        RECT  7.992 2.151 8.112 28.089 ;
        RECT  5.292 2.151 5.412 28.089 ;
        RECT  2.592 2.151 2.712 28.089 ;
    END
  END VDD
  PIN VSS
    DIRECTION INOUT ;
    USE GROUND ;
    PORT
      LAYER M5 ;
        RECT  169.8 2.137 169.92 28.103 ;
        RECT  167.1 2.137 167.22 28.103 ;
        RECT  164.4 2.137 164.52 28.103 ;
        RECT  161.7 2.137 161.82 28.103 ;
        RECT  159 2.137 159.12 28.103 ;
        RECT  156.3 2.137 156.42 28.103 ;
        RECT  153.6 2.137 153.72 28.103 ;
        RECT  150.9 2.137 151.02 28.103 ;
        RECT  148.2 2.137 148.32 28.103 ;
        RECT  145.5 2.137 145.62 28.103 ;
        RECT  142.8 2.137 142.92 28.103 ;
        RECT  140.1 2.137 140.22 28.103 ;
        RECT  137.4 2.137 137.52 28.103 ;
        RECT  134.7 2.137 134.82 28.103 ;
        RECT  132 2.137 132.12 28.103 ;
        RECT  129.3 2.137 129.42 28.103 ;
        RECT  126.6 2.137 126.72 28.103 ;
        RECT  123.9 2.137 124.02 28.103 ;
        RECT  121.2 2.137 121.32 28.103 ;
        RECT  118.5 2.137 118.62 28.103 ;
        RECT  115.8 2.137 115.92 28.103 ;
        RECT  113.1 2.137 113.22 28.103 ;
        RECT  110.4 2.137 110.52 28.103 ;
        RECT  107.7 2.137 107.82 28.103 ;
        RECT  105 2.137 105.12 28.103 ;
        RECT  102.3 2.137 102.42 28.103 ;
        RECT  99.6 2.137 99.72 28.103 ;
        RECT  96.9 2.137 97.02 28.103 ;
        RECT  94.2 2.137 94.32 28.103 ;
        RECT  91.5 2.137 91.62 28.103 ;
        RECT  88.8 2.137 88.92 28.103 ;
        RECT  86.1 2.137 86.22 28.103 ;
        RECT  83.4 2.137 83.52 28.103 ;
        RECT  80.7 2.137 80.82 28.103 ;
        RECT  78 2.137 78.12 28.103 ;
        RECT  75.3 2.137 75.42 28.103 ;
        RECT  72.6 2.137 72.72 28.103 ;
        RECT  69.9 2.137 70.02 28.103 ;
        RECT  67.2 2.137 67.32 28.103 ;
        RECT  64.5 2.137 64.62 28.103 ;
        RECT  61.8 2.137 61.92 28.103 ;
        RECT  59.1 2.137 59.22 28.103 ;
        RECT  56.4 2.137 56.52 28.103 ;
        RECT  53.7 2.137 53.82 28.103 ;
        RECT  51 2.137 51.12 28.103 ;
        RECT  48.3 2.137 48.42 28.103 ;
        RECT  45.6 2.137 45.72 28.103 ;
        RECT  42.9 2.137 43.02 28.103 ;
        RECT  40.2 2.137 40.32 28.103 ;
        RECT  37.5 2.137 37.62 28.103 ;
        RECT  34.8 2.137 34.92 28.103 ;
        RECT  32.1 2.137 32.22 28.103 ;
        RECT  29.4 2.137 29.52 28.103 ;
        RECT  26.7 2.137 26.82 28.103 ;
        RECT  24 2.137 24.12 28.103 ;
        RECT  21.3 2.137 21.42 28.103 ;
        RECT  18.6 2.137 18.72 28.103 ;
        RECT  15.9 2.137 16.02 28.103 ;
        RECT  13.2 2.137 13.32 28.103 ;
        RECT  10.5 2.137 10.62 28.103 ;
        RECT  7.8 2.137 7.92 28.103 ;
        RECT  5.1 2.137 5.22 28.103 ;
        RECT  2.4 2.137 2.52 28.103 ;
    END
  END VSS
  # OT_OBS_CLOSED layer=M5 d_um=1.536 added=114
  OBS
    LAYER RVTN ;
     RECT  2.16 2.16 170.64 2.295 ;
     RECT  2.16 2.565 170.64 2.835 ;
     RECT  2.16 3.105 170.64 3.375 ;
     RECT  2.16 3.645 170.64 3.915 ;
     RECT  2.16 4.185 170.64 4.455 ;
     RECT  2.16 4.725 170.64 4.995 ;
     RECT  2.16 5.265 170.64 5.535 ;
     RECT  2.16 5.805 170.64 6.075 ;
     RECT  2.16 6.345 170.64 6.615 ;
     RECT  2.16 6.885 170.64 7.155 ;
     RECT  2.16 7.425 170.64 7.695 ;
     RECT  2.16 7.965 170.64 8.235 ;
     RECT  2.16 8.505 170.64 8.775 ;
     RECT  2.16 9.045 170.64 9.315 ;
     RECT  2.16 9.585 170.64 9.855 ;
     RECT  2.16 10.125 170.64 10.395 ;
     RECT  2.16 10.665 170.64 10.935 ;
     RECT  2.16 11.205 170.64 11.475 ;
     RECT  2.16 11.745 170.64 12.015 ;
     RECT  2.16 12.285 170.64 12.555 ;
     RECT  2.16 12.825 170.64 13.095 ;
     RECT  2.16 13.365 170.64 13.635 ;
     RECT  2.16 13.905 170.64 14.175 ;
     RECT  2.16 14.445 170.64 14.715 ;
     RECT  2.16 14.985 170.64 15.255 ;
     RECT  2.16 15.525 170.64 15.795 ;
     RECT  2.16 16.065 170.64 16.335 ;
     RECT  2.16 16.605 170.64 16.875 ;
     RECT  2.16 17.145 170.64 17.415 ;
     RECT  2.16 17.685 170.64 17.955 ;
     RECT  2.16 18.225 170.64 18.495 ;
     RECT  2.16 18.765 170.64 19.035 ;
     RECT  2.16 19.305 170.64 19.575 ;
     RECT  2.16 19.845 170.64 20.115 ;
     RECT  2.16 20.385 170.64 20.655 ;
     RECT  2.16 20.925 170.64 21.195 ;
     RECT  2.16 21.465 170.64 21.735 ;
     RECT  2.16 22.005 170.64 22.275 ;
     RECT  2.16 22.545 170.64 22.815 ;
     RECT  2.16 23.085 170.64 23.355 ;
     RECT  2.16 23.625 170.64 23.895 ;
     RECT  2.16 24.165 170.64 24.435 ;
     RECT  2.16 24.705 170.64 24.975 ;
     RECT  2.16 25.245 170.64 25.515 ;
     RECT  2.16 25.785 170.64 26.055 ;
     RECT  2.16 26.325 170.64 26.595 ;
     RECT  2.16 26.865 170.64 27.135 ;
     RECT  2.16 27.405 170.64 27.675 ;
     RECT  2.16 27.945 170.64 28.08 ;
    LAYER RVTP ;
     RECT  2.16 2.295 170.64 2.565 ;
     RECT  2.16 2.835 170.64 3.105 ;
     RECT  2.16 3.375 170.64 3.645 ;
     RECT  2.16 3.915 170.64 4.185 ;
     RECT  2.16 4.455 170.64 4.725 ;
     RECT  2.16 4.995 170.64 5.265 ;
     RECT  2.16 5.535 170.64 5.805 ;
     RECT  2.16 6.075 170.64 6.345 ;
     RECT  2.16 6.615 170.64 6.885 ;
     RECT  2.16 7.155 170.64 7.425 ;
     RECT  2.16 7.695 170.64 7.965 ;
     RECT  2.16 8.235 170.64 8.505 ;
     RECT  2.16 8.775 170.64 9.045 ;
     RECT  2.16 9.315 170.64 9.585 ;
     RECT  2.16 9.855 170.64 10.125 ;
     RECT  2.16 10.395 170.64 10.665 ;
     RECT  2.16 10.935 170.64 11.205 ;
     RECT  2.16 11.475 170.64 11.745 ;
     RECT  2.16 12.015 170.64 12.285 ;
     RECT  2.16 12.555 170.64 12.825 ;
     RECT  2.16 13.095 170.64 13.365 ;
     RECT  2.16 13.635 170.64 13.905 ;
     RECT  2.16 14.175 170.64 14.445 ;
     RECT  2.16 14.715 170.64 14.985 ;
     RECT  2.16 15.255 170.64 15.525 ;
     RECT  2.16 15.795 170.64 16.065 ;
     RECT  2.16 16.335 170.64 16.605 ;
     RECT  2.16 16.875 170.64 17.145 ;
     RECT  2.16 17.415 170.64 17.685 ;
     RECT  2.16 17.955 170.64 18.225 ;
     RECT  2.16 18.495 170.64 18.765 ;
     RECT  2.16 19.035 170.64 19.305 ;
     RECT  2.16 19.575 170.64 19.845 ;
     RECT  2.16 20.115 170.64 20.385 ;
     RECT  2.16 20.655 170.64 20.925 ;
     RECT  2.16 21.195 170.64 21.465 ;
     RECT  2.16 21.735 170.64 22.005 ;
     RECT  2.16 22.275 170.64 22.545 ;
     RECT  2.16 22.815 170.64 23.085 ;
     RECT  2.16 23.355 170.64 23.625 ;
     RECT  2.16 23.895 170.64 24.165 ;
     RECT  2.16 24.435 170.64 24.705 ;
     RECT  2.16 24.975 170.64 25.245 ;
     RECT  2.16 25.515 170.64 25.785 ;
     RECT  2.16 26.055 170.64 26.325 ;
     RECT  2.16 26.595 170.64 26.865 ;
     RECT  2.16 27.135 170.64 27.405 ;
     RECT  2.16 27.675 170.64 27.945 ;
    LAYER M1 ;
     RECT  2.16 2.151 170.64 28.089 ;
    LAYER M2 ;
     RECT  2.16 2.151 46.003 28.089 ;
     RECT  46.003 2.151 48.479 28.134 ;
     RECT  48.667 29.034 48.767 29.052 ;
     RECT  48.479 2.151 51.655 28.089 ;
     RECT  68.647 29.034 68.963 29.052 ;
     RECT  87.619 29.034 87.719 29.052 ;
     RECT  51.655 1.836 90.067 28.089 ;
     RECT  93.235 29.034 93.335 29.052 ;
     RECT  90.067 1.8 94.027 28.089 ;
     RECT  94.027 1.764 96.899 28.089 ;
     RECT  96.899 1.8 130.531 28.089 ;
     RECT  130.531 1.728 134.771 28.089 ;
     RECT  134.771 1.764 137.111 28.089 ;
     RECT  137.111 1.8 141.619 28.089 ;
     RECT  141.619 1.764 141.655 28.089 ;
     RECT  141.655 1.728 143.879 28.089 ;
     RECT  143.879 1.764 169.475 28.089 ;
     RECT  169.475 1.881 169.799 28.089 ;
     RECT  169.799 2.151 170.64 28.089 ;
     RECT  170.64 3.42 170.807 5.49 ;
     RECT  170.807 3.42 171.311 4.788 ;
     RECT  171.311 4.158 171.455 4.788 ;
     RECT  171.455 4.662 171.599 4.788 ;
     RECT  171.599 4.77 172.031 4.788 ;
    LAYER M3 ;
     RECT  170.244 0.091 170.262 0.523 ;
     RECT  92.268 0.091 92.286 0.571 ;
     RECT  170.244 0.523 170.442 0.619 ;
     RECT  170.136 0.619 170.442 1.051 ;
     RECT  91.908 0.571 92.286 1.099 ;
     RECT  170.136 1.051 170.694 1.099 ;
     RECT  94.176 0.523 94.194 1.147 ;
     RECT  131.688 1.147 131.706 1.675 ;
     RECT  90.9 0.091 90.918 1.723 ;
     RECT  91.908 1.099 92.826 1.723 ;
     RECT  94.176 1.147 94.698 1.723 ;
     RECT  96.336 1.099 96.354 1.723 ;
     RECT  100.008 1.627 100.026 1.723 ;
     RECT  123.192 0.091 123.21 1.723 ;
     RECT  124.848 1.099 124.866 1.723 ;
     RECT  131.688 1.675 131.886 1.723 ;
     RECT  132.84 1.099 132.858 1.723 ;
     RECT  134.892 0.523 134.91 1.723 ;
     RECT  142.488 0.571 142.506 1.723 ;
     RECT  147.924 0.091 147.942 1.723 ;
     RECT  153.972 0.091 153.99 1.723 ;
     RECT  170.136 1.099 170.802 1.723 ;
     RECT  96.336 1.723 96.606 1.759 ;
     RECT  136.44 1.723 136.998 1.759 ;
     RECT  91.908 1.723 95.562 1.771 ;
     RECT  96.336 1.759 96.894 1.771 ;
     RECT  97.812 1.723 103.734 1.771 ;
     RECT  105.336 1.723 107.586 1.771 ;
     RECT  112.824 1.723 112.842 1.771 ;
     RECT  113.652 1.723 115.362 1.771 ;
     RECT  118.152 1.723 118.17 1.771 ;
     RECT  118.908 1.723 118.926 1.771 ;
     RECT  122.832 1.723 125.622 1.771 ;
     RECT  126.396 1.723 126.594 1.771 ;
     RECT  127.512 1.723 130.554 1.771 ;
     RECT  136.44 1.759 137.106 1.771 ;
     RECT  137.844 1.723 138.186 1.771 ;
     RECT  150.12 1.723 158.742 1.771 ;
     RECT  159.588 1.723 160.326 1.771 ;
     RECT  165.168 1.723 165.582 1.771 ;
     RECT  166.356 1.723 166.734 1.771 ;
     RECT  97.632 1.771 103.734 1.819 ;
     RECT  104.94 1.771 107.586 1.819 ;
     RECT  131.364 1.723 135.63 1.819 ;
     RECT  136.44 1.771 138.186 1.819 ;
     RECT  161.208 1.723 164.178 1.819 ;
     RECT  138.924 1.723 143.874 1.876 ;
     RECT  144.648 1.723 147.186 1.876 ;
     RECT  165.168 1.771 166.734 1.876 ;
     RECT  167.616 1.723 171.018 1.876 ;
     RECT  91.908 1.771 96.894 1.915 ;
     RECT  97.632 1.819 104.166 1.915 ;
     RECT  104.94 1.819 107.658 1.915 ;
     RECT  161.172 1.819 164.178 1.915 ;
     RECT  147.924 1.723 149.13 1.921 ;
     RECT  150.12 1.771 160.326 1.921 ;
     RECT  116.172 1.723 116.19 1.957 ;
     RECT  117.144 1.723 117.162 1.957 ;
     RECT  112.824 1.771 115.362 1.963 ;
     RECT  116.172 1.957 117.162 1.963 ;
     RECT  161.172 1.915 164.214 2.011 ;
     RECT  104.94 1.915 108.198 2.029 ;
     RECT  109.044 1.723 111.546 2.029 ;
     RECT  91.908 1.915 104.166 2.059 ;
     RECT  104.94 2.029 111.546 2.059 ;
     RECT  120.168 1.723 122.094 2.059 ;
     RECT  122.832 1.771 130.554 2.059 ;
     RECT  131.364 1.819 138.186 2.059 ;
     RECT  138.924 1.876 147.186 2.059 ;
     RECT  147.924 1.921 160.326 2.059 ;
     RECT  161.172 2.011 164.25 2.059 ;
     RECT  90.072 1.795 90.09 2.065 ;
     RECT  90.9 1.723 91.098 2.065 ;
     RECT  91.908 2.059 111.546 2.065 ;
     RECT  112.824 1.963 117.162 2.065 ;
     RECT  118.152 1.771 119.07 2.065 ;
     RECT  131.364 2.059 147.186 2.065 ;
     RECT  147.924 2.059 164.25 2.065 ;
     RECT  131.364 2.065 164.25 2.101 ;
     RECT  51.66 1.831 51.678 2.143 ;
     RECT  61.236 2.059 61.254 2.143 ;
     RECT  61.992 2.059 62.73 2.143 ;
     RECT  70.092 2.059 70.722 2.143 ;
     RECT  78.192 2.059 78.678 2.143 ;
     RECT  86.292 2.059 86.67 2.143 ;
     RECT  131.364 2.101 164.286 2.143 ;
     RECT  165.168 1.876 171.018 2.143 ;
     RECT  90.9 2.065 111.546 2.191 ;
     RECT  112.824 2.065 119.07 2.191 ;
     RECT  120.168 2.059 130.59 2.191 ;
     RECT  61.236 2.143 62.73 2.237 ;
     RECT  69.915 2.143 70.722 2.237 ;
     RECT  78.015 2.143 78.678 2.237 ;
     RECT  86.115 2.143 86.67 2.237 ;
     RECT  90.9 2.191 111.798 2.263 ;
     RECT  112.68 2.191 130.59 2.263 ;
     RECT  90.9 2.263 130.59 2.299 ;
     RECT  131.364 2.143 171.018 2.299 ;
     RECT  90.9 2.299 130.626 2.371 ;
     RECT  131.364 2.299 172.026 2.371 ;
     RECT  2.415 2.143 2.505 2.413 ;
     RECT  5.115 2.143 5.205 2.413 ;
     RECT  7.815 2.143 7.905 2.413 ;
     RECT  10.515 2.143 10.605 2.413 ;
     RECT  13.215 2.143 13.305 2.413 ;
     RECT  15.915 2.143 16.005 2.413 ;
     RECT  18.615 2.143 18.705 2.413 ;
     RECT  21.315 2.143 21.405 2.413 ;
     RECT  24.015 2.143 24.105 2.413 ;
     RECT  26.715 2.143 26.805 2.413 ;
     RECT  29.415 2.143 29.505 2.413 ;
     RECT  32.115 2.143 32.205 2.413 ;
     RECT  34.815 2.143 34.905 2.413 ;
     RECT  37.515 2.143 37.605 2.413 ;
     RECT  40.215 2.143 40.305 2.413 ;
     RECT  42.915 2.143 43.005 2.413 ;
     RECT  45.615 2.143 45.705 2.413 ;
     RECT  48.315 2.143 48.405 2.413 ;
     RECT  53.715 2.143 53.805 2.413 ;
     RECT  56.415 2.143 56.505 2.413 ;
     RECT  59.115 2.143 59.205 2.413 ;
     RECT  64.515 2.143 64.605 2.413 ;
     RECT  67.215 2.143 67.305 2.413 ;
     RECT  72.615 2.143 72.705 2.413 ;
     RECT  75.315 2.143 75.405 2.413 ;
     RECT  80.715 2.143 80.805 2.413 ;
     RECT  83.415 2.143 83.505 2.413 ;
     RECT  88.815 2.143 88.905 2.413 ;
     RECT  90.072 2.065 90.162 2.461 ;
     RECT  90.9 2.371 172.026 2.461 ;
     RECT  63.54 1.921 63.558 2.491 ;
     RECT  53.715 2.413 53.997 2.539 ;
     RECT  88.815 2.413 89.097 2.569 ;
     RECT  90.072 2.461 172.026 2.569 ;
     RECT  53.136 2.539 53.997 2.839 ;
     RECT  61.236 2.237 62.406 3.343 ;
     RECT  88.815 2.569 172.026 3.407 ;
     RECT  87.876 2.101 87.894 3.451 ;
     RECT  86.115 2.237 86.397 3.541 ;
     RECT  87.372 3.451 87.894 3.541 ;
     RECT  86.115 3.541 87.894 3.577 ;
     RECT  88.815 3.407 163.602 3.577 ;
     RECT  53.136 2.839 54.414 3.649 ;
     RECT  75.315 2.413 75.597 3.721 ;
     RECT  86.115 3.577 163.602 3.749 ;
     RECT  87.372 3.749 163.602 3.875 ;
     RECT  164.415 3.407 172.026 4.181 ;
     RECT  72.615 2.413 72.897 4.261 ;
     RECT  53.136 3.649 54.45 4.423 ;
     RECT  51.015 2.143 51.678 4.459 ;
     RECT  52.632 4.423 54.45 4.459 ;
     RECT  64.515 2.413 64.797 4.495 ;
     RECT  171.576 4.181 172.026 4.685 ;
     RECT  88.272 3.875 163.602 4.765 ;
     RECT  172.008 4.685 172.026 4.793 ;
     RECT  66.276 3.685 66.294 4.801 ;
     RECT  67.215 2.413 67.497 4.801 ;
     RECT  69.915 2.237 70.197 4.963 ;
     RECT  51.015 4.459 54.45 4.999 ;
     RECT  87.372 3.875 87.462 5.035 ;
     RECT  88.2 4.765 163.602 5.035 ;
     RECT  164.415 4.181 170.802 5.495 ;
     RECT  66.276 4.801 67.497 5.503 ;
     RECT  66.276 5.503 67.95 5.539 ;
     RECT  76.644 5.431 76.662 5.575 ;
     RECT  78.015 2.237 78.297 5.575 ;
     RECT  69.48 4.963 70.197 5.611 ;
     RECT  72.072 4.261 72.897 5.881 ;
     RECT  66.276 5.539 68.562 5.971 ;
     RECT  69.48 5.611 70.722 5.971 ;
     RECT  51.015 4.999 54.81 6.043 ;
     RECT  74.88 3.721 75.597 6.079 ;
     RECT  76.644 5.575 78.297 6.079 ;
     RECT  56.415 2.413 56.697 6.115 ;
     RECT  80.715 2.413 80.997 6.151 ;
     RECT  80.1 6.151 80.997 6.511 ;
     RECT  66.276 5.971 70.722 6.547 ;
     RECT  49.428 2.875 49.446 6.583 ;
     RECT  50.436 6.043 54.81 6.583 ;
     RECT  55.8 6.115 56.697 6.619 ;
     RECT  72.072 5.881 72.99 6.781 ;
     RECT  49.428 6.583 54.81 6.817 ;
     RECT  84.852 6.007 84.87 7.159 ;
     RECT  74.88 6.079 78.297 7.195 ;
     RECT  72.072 6.781 73.422 7.231 ;
     RECT  74.268 7.195 78.297 7.231 ;
     RECT  82.224 5.341 82.242 7.357 ;
     RECT  80.1 6.511 81.234 7.771 ;
     RECT  48.315 2.413 48.597 7.861 ;
     RECT  49.428 6.817 55.062 7.861 ;
     RECT  83.415 2.413 83.697 7.933 ;
     RECT  48.315 7.861 55.062 8.401 ;
     RECT  55.8 6.619 57.294 8.401 ;
     RECT  72.072 7.231 78.297 8.509 ;
     RECT  83.415 7.933 84.114 8.815 ;
     RECT  84.852 7.159 85.266 8.815 ;
     RECT  86.115 3.749 86.397 9.085 ;
     RECT  86.004 9.085 86.397 9.517 ;
     RECT  87.372 5.035 163.602 9.517 ;
     RECT  59.115 2.413 59.397 9.553 ;
     RECT  48.315 8.401 57.294 9.589 ;
     RECT  58.392 9.553 59.397 9.589 ;
     RECT  86.004 9.517 163.602 9.653 ;
     RECT  79.992 7.771 81.234 9.931 ;
     RECT  66.276 6.547 71.298 10.057 ;
     RECT  82.224 7.357 82.566 10.471 ;
     RECT  79.524 9.931 81.234 10.597 ;
     RECT  82.224 10.471 82.638 10.705 ;
     RECT  83.415 8.815 85.266 10.705 ;
     RECT  79.236 10.597 81.234 11.011 ;
     RECT  82.224 10.705 85.266 11.011 ;
     RECT  79.236 11.011 85.266 11.101 ;
     RECT  86.004 9.653 86.397 11.101 ;
     RECT  60.876 3.343 62.406 11.173 ;
     RECT  72.072 8.509 78.354 11.209 ;
     RECT  79.236 11.101 86.397 11.209 ;
     RECT  63.54 2.491 63.666 11.281 ;
     RECT  64.515 4.495 65.214 11.281 ;
     RECT  87.372 9.653 163.602 11.479 ;
     RECT  72.072 11.209 86.397 12.019 ;
     RECT  87.12 11.479 163.602 12.019 ;
     RECT  60.876 11.173 62.442 12.091 ;
     RECT  63.54 11.281 65.214 12.091 ;
     RECT  60.876 12.091 65.214 12.253 ;
     RECT  72.072 12.019 163.602 12.353 ;
     RECT  72.072 12.353 161.997 12.623 ;
     RECT  72.072 12.623 158.274 12.821 ;
     RECT  60.876 12.253 65.286 12.901 ;
     RECT  66.276 10.057 71.334 13.369 ;
     RECT  72.072 12.821 152.586 13.369 ;
     RECT  164.415 5.495 170.622 13.631 ;
     RECT  153.615 12.821 158.274 14.135 ;
     RECT  154.908 14.135 158.274 14.639 ;
     RECT  164.415 13.631 168.282 14.783 ;
     RECT  154.908 14.639 154.962 15.089 ;
     RECT  162.72 12.353 163.602 15.179 ;
     RECT  66.276 13.369 152.586 15.215 ;
     RECT  45.615 2.413 45.897 15.223 ;
     RECT  47.556 5.467 47.574 15.457 ;
     RECT  2.415 2.413 2.697 15.592 ;
     RECT  5.115 2.413 5.397 15.592 ;
     RECT  13.215 2.413 13.497 15.592 ;
     RECT  2.304 15.592 2.697 15.629 ;
     RECT  5.004 15.592 5.397 15.629 ;
     RECT  6.84 15.499 6.858 15.629 ;
     RECT  13.104 15.592 13.497 15.629 ;
     RECT  42.915 2.413 43.197 15.691 ;
     RECT  43.92 15.601 43.938 15.691 ;
     RECT  42.915 15.691 43.938 15.719 ;
     RECT  15.915 2.413 16.197 15.727 ;
     RECT  14.832 15.595 14.85 15.773 ;
     RECT  15.915 15.727 16.542 15.773 ;
     RECT  42.915 15.719 43.722 15.791 ;
     RECT  137.415 15.215 152.586 15.791 ;
     RECT  163.584 15.179 163.602 15.827 ;
     RECT  155.808 14.639 158.274 15.899 ;
     RECT  169.128 13.631 170.622 16.259 ;
     RECT  66.276 15.215 136.53 16.267 ;
     RECT  137.415 15.791 152.514 16.295 ;
     RECT  162.72 15.179 162.738 16.331 ;
     RECT  156.096 15.899 158.274 16.403 ;
     RECT  156.096 16.403 158.166 16.835 ;
     RECT  150.915 16.295 152.514 16.907 ;
     RECT  137.415 16.295 150.066 16.943 ;
     RECT  164.415 14.783 165.114 17.411 ;
     RECT  150.915 16.907 152.226 17.519 ;
     RECT  137.415 16.943 150.03 17.609 ;
     RECT  156.096 16.835 157.086 17.645 ;
     RECT  150.915 17.519 151.902 17.951 ;
     RECT  159.015 12.623 161.997 17.987 ;
     RECT  166.32 14.783 168.282 18.149 ;
     RECT  66.168 16.267 136.53 18.185 ;
     RECT  137.415 17.609 149.67 18.221 ;
     RECT  150.915 17.951 151.83 18.527 ;
     RECT  166.32 18.149 167.397 18.725 ;
     RECT  161.28 17.987 161.997 18.761 ;
     RECT  66.168 18.185 135.99 18.797 ;
     RECT  48.315 9.589 59.397 18.805 ;
     RECT  60.12 1.993 60.138 18.805 ;
     RECT  60.876 12.901 65.322 18.805 ;
     RECT  48.315 18.805 60.138 18.833 ;
     RECT  154.944 15.089 154.962 19.103 ;
     RECT  145.515 18.221 149.67 19.111 ;
     RECT  145.515 19.111 149.706 19.229 ;
     RECT  159.015 17.987 160.146 19.229 ;
     RECT  168.192 18.149 168.282 19.373 ;
     RECT  145.515 19.229 149.67 19.643 ;
     RECT  168.192 19.373 168.21 19.679 ;
     RECT  153.615 14.135 154.098 19.769 ;
     RECT  66.168 18.797 134.997 19.877 ;
     RECT  148.215 19.643 149.67 19.949 ;
     RECT  156.096 17.645 157.05 20.219 ;
     RECT  148.215 19.949 149.238 20.309 ;
     RECT  158.148 16.835 158.166 20.345 ;
     RECT  164.415 17.411 165.042 20.381 ;
     RECT  145.515 19.643 147.474 20.417 ;
     RECT  60.876 18.805 65.358 20.425 ;
     RECT  145.515 20.417 146.25 20.453 ;
     RECT  148.215 20.309 148.806 20.687 ;
     RECT  156.096 20.219 156.597 20.885 ;
     RECT  159.015 19.229 159.75 20.921 ;
     RECT  153.615 19.769 153.954 20.957 ;
     RECT  147.456 20.417 147.474 20.993 ;
     RECT  66.168 19.877 133.83 21.029 ;
     RECT  135.936 18.797 135.99 21.299 ;
     RECT  137.415 18.221 144.558 21.533 ;
     RECT  48.315 18.833 60.03 21.541 ;
     RECT  60.876 20.425 65.43 21.541 ;
     RECT  48.315 21.541 65.43 21.667 ;
     RECT  66.168 21.029 132.462 21.667 ;
     RECT  48.315 21.667 132.462 21.965 ;
     RECT  137.415 21.533 138.546 22.037 ;
     RECT  139.392 21.533 144.558 22.109 ;
     RECT  48.315 21.965 132.297 22.307 ;
     RECT  142.236 22.109 144.558 22.379 ;
     RECT  130.356 22.307 132.297 22.469 ;
     RECT  139.392 22.109 141.318 22.919 ;
     RECT  143.928 22.379 144.558 23.189 ;
     RECT  166.788 18.725 167.397 23.351 ;
     RECT  139.392 22.919 141.066 23.459 ;
     RECT  130.752 22.469 132.297 23.621 ;
     RECT  133.668 21.029 133.83 23.657 ;
     RECT  133.812 23.657 133.83 23.729 ;
     RECT  137.415 22.037 138.402 23.999 ;
     RECT  145.515 20.453 145.962 24.233 ;
     RECT  48.315 22.307 129.597 24.331 ;
     RECT  143.928 23.189 144.018 24.431 ;
     RECT  142.236 22.379 143.097 24.503 ;
     RECT  47.268 15.457 47.574 24.511 ;
     RECT  48.315 24.331 129.798 24.511 ;
     RECT  47.268 24.511 129.798 24.601 ;
     RECT  130.752 23.621 131.058 24.601 ;
     RECT  47.268 24.601 131.058 24.737 ;
     RECT  45.615 15.223 46.314 24.763 ;
     RECT  47.268 24.737 129.978 24.763 ;
     RECT  135.972 21.299 135.99 24.809 ;
     RECT  45.615 24.763 129.978 24.899 ;
     RECT  144 24.431 144.018 24.971 ;
     RECT  166.932 23.351 167.397 25.043 ;
     RECT  169.128 16.259 170.097 25.277 ;
     RECT  140.115 23.459 141.066 25.511 ;
     RECT  47.124 24.899 129.978 25.619 ;
     RECT  45.615 24.899 46.314 25.861 ;
     RECT  47.124 25.619 129.597 25.861 ;
     RECT  131.04 24.737 131.058 25.889 ;
     RECT  45.615 25.861 129.597 27.175 ;
     RECT  45.396 27.175 129.597 27.211 ;
     RECT  132.015 23.621 132.297 27.373 ;
     RECT  45.396 27.211 130.122 27.643 ;
     RECT  45.396 27.643 130.518 27.679 ;
     RECT  131.292 27.373 132.297 27.679 ;
     RECT  45.396 27.679 132.297 27.779 ;
     RECT  2.415 15.629 2.697 27.827 ;
     RECT  5.115 15.629 5.397 27.827 ;
     RECT  7.815 2.413 8.097 27.827 ;
     RECT  10.515 2.413 10.797 27.827 ;
     RECT  13.215 15.629 13.497 27.827 ;
     RECT  15.915 15.773 16.197 27.827 ;
     RECT  18.615 2.413 18.897 27.827 ;
     RECT  21.315 2.413 21.597 27.827 ;
     RECT  24.015 2.413 24.297 27.827 ;
     RECT  26.715 2.413 26.997 27.827 ;
     RECT  29.415 2.413 29.697 27.827 ;
     RECT  32.115 2.413 32.397 27.827 ;
     RECT  34.815 2.413 35.097 27.827 ;
     RECT  37.515 2.413 37.797 27.827 ;
     RECT  40.215 2.413 40.497 27.827 ;
     RECT  42.915 15.791 43.197 27.827 ;
     RECT  61.812 27.779 132.297 27.827 ;
     RECT  134.715 19.877 134.997 27.827 ;
     RECT  137.415 23.999 137.697 27.827 ;
     RECT  140.115 25.511 140.397 27.827 ;
     RECT  142.815 24.503 143.097 27.827 ;
     RECT  145.515 24.233 145.797 27.827 ;
     RECT  148.215 20.687 148.497 27.827 ;
     RECT  150.915 18.527 151.197 27.827 ;
     RECT  153.615 20.957 153.897 27.827 ;
     RECT  156.315 20.885 156.597 27.827 ;
     RECT  159.015 20.921 159.297 27.827 ;
     RECT  161.715 18.761 161.997 27.827 ;
     RECT  164.415 20.381 164.697 27.827 ;
     RECT  167.115 25.043 167.397 27.827 ;
     RECT  169.815 25.277 170.097 27.827 ;
     RECT  45.396 27.779 61.038 27.869 ;
     RECT  61.812 27.827 132.105 27.869 ;
     RECT  105.015 27.869 105.93 27.875 ;
     RECT  50.364 27.869 52.794 27.905 ;
     RECT  119.88 27.869 121.878 27.905 ;
     RECT  122.832 27.869 132.105 27.905 ;
     RECT  88.815 27.869 91.605 27.917 ;
     RECT  45.396 27.869 49.122 27.941 ;
     RECT  55.656 27.869 57.366 27.941 ;
     RECT  58.716 27.869 59.205 27.941 ;
     RECT  62.676 27.869 66.114 27.941 ;
     RECT  67.215 27.869 70.866 27.941 ;
     RECT  71.856 27.869 73.566 27.941 ;
     RECT  74.772 27.869 75.405 27.941 ;
     RECT  76.14 27.869 78.678 27.941 ;
     RECT  79.884 27.869 83.79 27.941 ;
     RECT  85.14 27.869 88.074 27.941 ;
     RECT  88.815 27.917 89.262 27.941 ;
     RECT  92.52 27.869 94.374 27.941 ;
     RECT  95.328 27.869 97.938 27.941 ;
     RECT  98.928 27.869 100.854 27.941 ;
     RECT  103.14 27.869 103.806 27.941 ;
     RECT  105.015 27.875 105.426 27.941 ;
     RECT  106.848 27.869 109.53 27.941 ;
     RECT  110.415 27.869 113.205 27.941 ;
     RECT  115.74 27.869 116.154 27.941 ;
     RECT  119.88 27.905 119.97 27.941 ;
     RECT  120.78 27.905 121.878 27.941 ;
     RECT  122.832 27.905 131.022 27.941 ;
     RECT  63.18 27.941 64.89 27.965 ;
     RECT  76.788 27.941 78.57 27.965 ;
     RECT  92.52 27.941 93.474 27.965 ;
     RECT  114.444 27.869 114.462 27.965 ;
     RECT  77.004 27.965 78.57 27.977 ;
     RECT  81.756 27.941 83.79 27.977 ;
     RECT  45.396 27.941 48.942 28.013 ;
     RECT  122.832 27.941 129.942 28.013 ;
     RECT  45.396 28.013 46.062 28.061 ;
     RECT  122.832 28.013 127.566 28.061 ;
     RECT  2.415 27.827 2.505 28.097 ;
     RECT  5.115 27.827 5.205 28.097 ;
     RECT  7.815 27.827 7.905 28.097 ;
     RECT  10.515 27.827 10.605 28.097 ;
     RECT  13.215 27.827 13.305 28.097 ;
     RECT  15.915 27.827 16.005 28.097 ;
     RECT  18.615 27.827 18.705 28.097 ;
     RECT  21.315 27.827 21.405 28.097 ;
     RECT  24.015 27.827 24.105 28.097 ;
     RECT  26.715 27.827 26.805 28.097 ;
     RECT  29.415 27.827 29.505 28.097 ;
     RECT  32.115 27.827 32.205 28.097 ;
     RECT  34.815 27.827 34.905 28.097 ;
     RECT  37.515 27.827 37.605 28.097 ;
     RECT  40.215 27.827 40.305 28.097 ;
     RECT  42.915 27.827 43.005 28.097 ;
     RECT  45.615 28.061 46.062 28.097 ;
     RECT  53.715 27.869 54.522 28.097 ;
     RECT  59.115 27.941 59.205 28.097 ;
     RECT  61.815 27.869 61.905 28.097 ;
     RECT  67.215 27.941 67.59 28.097 ;
     RECT  71.856 27.941 72.705 28.097 ;
     RECT  75.315 27.941 75.405 28.097 ;
     RECT  77.58 27.977 78.57 28.097 ;
     RECT  79.884 27.941 80.805 28.097 ;
     RECT  86.115 27.941 87.714 28.097 ;
     RECT  88.815 27.941 88.905 28.097 ;
     RECT  90.072 27.917 91.605 28.097 ;
     RECT  94.215 27.941 94.374 28.097 ;
     RECT  96.915 27.941 97.938 28.097 ;
     RECT  101.808 27.869 102.405 28.097 ;
     RECT  105.015 27.941 105.39 28.097 ;
     RECT  110.415 27.941 111.654 28.097 ;
     RECT  112.968 27.941 113.205 28.097 ;
     RECT  115.74 27.941 115.905 28.097 ;
     RECT  118.224 27.869 118.605 28.097 ;
     RECT  121.215 27.941 121.806 28.097 ;
     RECT  125.568 28.061 127.566 28.097 ;
     RECT  132.015 27.905 132.105 28.097 ;
     RECT  134.715 27.827 134.805 28.097 ;
     RECT  137.415 27.827 137.505 28.097 ;
     RECT  140.115 27.827 140.205 28.097 ;
     RECT  142.815 27.827 142.905 28.097 ;
     RECT  145.515 27.827 145.605 28.097 ;
     RECT  148.215 27.827 148.305 28.097 ;
     RECT  150.915 27.827 151.005 28.097 ;
     RECT  153.615 27.827 153.705 28.097 ;
     RECT  156.315 27.827 156.405 28.097 ;
     RECT  159.015 27.827 159.105 28.097 ;
     RECT  161.715 27.827 161.805 28.097 ;
     RECT  164.415 27.827 164.505 28.097 ;
     RECT  167.115 27.827 167.205 28.097 ;
     RECT  169.815 27.827 169.905 28.097 ;
     RECT  46.008 28.097 46.062 28.139 ;
     RECT  67.572 28.097 67.59 28.253 ;
     RECT  71.856 28.097 72.594 28.253 ;
     RECT  128.52 28.013 129.942 28.253 ;
     RECT  54.072 28.097 54.522 28.301 ;
     RECT  112.968 28.097 112.986 28.301 ;
     RECT  122.832 28.061 124.794 28.301 ;
     RECT  128.772 28.253 129.942 28.301 ;
     RECT  126.972 28.097 127.566 28.445 ;
     RECT  128.772 28.301 129.834 28.445 ;
     RECT  103.14 27.941 103.158 28.493 ;
     RECT  124.704 28.301 124.794 28.493 ;
     RECT  127.116 28.445 127.566 28.493 ;
     RECT  46.872 28.013 48.942 28.541 ;
     RECT  50.904 27.905 52.794 28.541 ;
     RECT  56.376 27.941 57.366 28.541 ;
     RECT  60.192 27.869 60.822 28.541 ;
     RECT  71.856 28.253 72.558 28.541 ;
     RECT  73.548 27.941 73.566 28.541 ;
     RECT  78.552 28.097 78.57 28.541 ;
     RECT  79.884 28.097 80.298 28.541 ;
     RECT  83.376 27.977 83.79 28.541 ;
     RECT  85.14 27.941 85.158 28.541 ;
     RECT  90.072 28.097 91.278 28.541 ;
     RECT  94.356 28.097 94.374 28.541 ;
     RECT  97.416 28.097 97.938 28.541 ;
     RECT  99.144 27.941 100.854 28.541 ;
     RECT  101.808 28.097 101.826 28.541 ;
     RECT  109.44 27.941 109.458 28.541 ;
     RECT  110.916 28.097 111.654 28.541 ;
     RECT  115.74 28.097 115.758 28.541 ;
     RECT  118.224 28.097 118.242 28.541 ;
     RECT  122.832 28.301 123.894 28.541 ;
     RECT  124.704 28.493 124.722 28.541 ;
     RECT  72.504 28.541 72.522 28.637 ;
     RECT  131.004 27.941 131.022 28.781 ;
     RECT  83.772 28.541 83.79 28.829 ;
     RECT  106.848 27.941 108.198 28.829 ;
     RECT  122.832 28.541 122.85 28.829 ;
     RECT  68.652 27.941 70.866 28.877 ;
     RECT  70.848 28.877 70.866 28.973 ;
     RECT  68.652 28.877 69.822 29.057 ;
     RECT  86.688 28.097 87.714 29.057 ;
     RECT  46.044 28.139 46.062 29.069 ;
     RECT  50.904 28.541 52.038 29.069 ;
     RECT  52.776 28.541 52.794 29.069 ;
     RECT  54.504 28.301 54.522 29.069 ;
     RECT  60.804 28.541 60.822 29.069 ;
     RECT  81.756 27.977 82.062 29.069 ;
     RECT  86.688 29.057 87.642 29.069 ;
     RECT  90.252 28.541 90.738 29.069 ;
     RECT  95.328 27.941 95.922 29.069 ;
     RECT  99.54 28.541 100.278 29.069 ;
     RECT  121.788 28.097 121.806 29.069 ;
     RECT  46.872 28.541 48.87 29.117 ;
     RECT  63.72 27.965 64.89 29.117 ;
     RECT  65.664 27.941 66.114 29.117 ;
     RECT  77.58 28.097 77.598 29.117 ;
     RECT  87.012 29.069 87.642 29.117 ;
     RECT  90.72 29.069 90.738 29.117 ;
     RECT  92.52 27.965 93.366 29.117 ;
     RECT  125.568 28.097 126.09 29.117 ;
     RECT  48.744 29.117 48.87 29.165 ;
     RECT  48.744 29.165 48.834 29.213 ;
     RECT  63.72 29.117 63.738 29.645 ;
     RECT  64.872 29.117 64.89 29.645 ;
     RECT  66.096 29.117 66.114 29.645 ;
     RECT  92.52 29.117 93.33 29.645 ;
     RECT  97.416 28.541 97.434 29.645 ;
     RECT  105.372 28.097 105.39 29.645 ;
     RECT  119.952 27.941 119.97 29.645 ;
     RECT  46.872 29.117 47.898 29.693 ;
     RECT  92.52 29.645 92.862 29.693 ;
     RECT  46.872 29.693 47.358 29.741 ;
     RECT  48.816 29.213 48.834 29.789 ;
     RECT  123.768 29.659 123.786 29.837 ;
     RECT  125.568 29.117 125.586 30.029 ;
     RECT  95.328 29.069 95.67 30.077 ;
     RECT  112.824 29.083 112.842 30.077 ;
     RECT  122.76 30.043 122.778 30.091 ;
     RECT  47.34 29.741 47.358 30.125 ;
     RECT  67.752 29.851 67.77 30.125 ;
     RECT  68.94 29.057 69.822 30.125 ;
     RECT  87.012 29.117 87.03 30.125 ;
     RECT  95.328 30.077 95.346 30.125 ;
     RECT  106.848 28.829 106.866 30.125 ;
     RECT  108.18 28.829 108.198 30.125 ;
     RECT  128.772 28.445 129.69 30.125 ;
     RECT  122.76 30.091 123.21 30.173 ;
     RECT  128.772 30.125 128.79 30.173 ;
     RECT  123.192 30.173 123.21 30.221 ;
     RECT  129.672 30.125 129.69 30.221 ;
    LAYER M4 ;
     RECT  0.181 21.456 2.408 21.48 ;
     RECT  2.408 2.148 2.512 28.092 ;
     RECT  2.512 2.418 2.704 27.822 ;
     RECT  2.704 15.6 5.108 15.624 ;
     RECT  2.704 21.456 5.108 21.48 ;
     RECT  5.108 2.148 5.212 28.092 ;
     RECT  5.212 2.418 5.404 27.822 ;
     RECT  5.404 15.6 6.829 15.624 ;
     RECT  6.829 15.504 7.808 15.624 ;
     RECT  5.404 21.456 7.808 21.48 ;
     RECT  7.808 2.148 7.912 28.092 ;
     RECT  7.912 2.418 8.104 27.822 ;
     RECT  8.104 15.504 10.508 15.528 ;
     RECT  8.104 21.456 10.508 21.48 ;
     RECT  10.508 2.148 10.612 28.092 ;
     RECT  10.612 2.418 10.804 27.822 ;
     RECT  10.804 15.6 13.208 15.624 ;
     RECT  10.804 21.456 13.208 21.48 ;
     RECT  13.208 2.148 13.312 28.092 ;
     RECT  13.312 2.418 13.504 27.822 ;
     RECT  13.504 15.6 14.821 15.624 ;
     RECT  14.821 15.6 14.861 15.768 ;
     RECT  14.861 15.744 15.908 15.768 ;
     RECT  13.504 21.456 15.908 21.48 ;
     RECT  15.908 2.148 16.012 28.092 ;
     RECT  16.012 2.418 16.204 27.822 ;
     RECT  16.204 15.744 16.553 15.768 ;
     RECT  16.204 21.456 18.608 21.48 ;
     RECT  18.608 2.148 18.712 28.092 ;
     RECT  18.712 2.418 18.904 27.822 ;
     RECT  18.904 21.456 21.308 21.48 ;
     RECT  21.308 2.148 21.412 28.092 ;
     RECT  21.412 2.418 21.604 27.822 ;
     RECT  21.604 21.456 24.008 21.48 ;
     RECT  24.008 2.148 24.112 28.092 ;
     RECT  24.112 2.418 24.304 27.822 ;
     RECT  24.304 21.456 26.708 21.48 ;
     RECT  26.708 2.148 26.812 28.092 ;
     RECT  26.812 2.418 27.004 27.822 ;
     RECT  27.004 21.456 29.408 21.48 ;
     RECT  29.408 2.148 29.512 28.092 ;
     RECT  29.512 2.418 29.704 27.822 ;
     RECT  29.704 21.456 32.108 21.48 ;
     RECT  32.108 2.148 32.212 28.092 ;
     RECT  32.212 2.418 32.404 27.822 ;
     RECT  32.404 21.456 34.808 21.48 ;
     RECT  34.808 2.148 34.912 28.092 ;
     RECT  34.912 2.418 35.104 27.822 ;
     RECT  35.104 21.456 37.508 21.48 ;
     RECT  37.508 2.148 37.612 28.092 ;
     RECT  37.612 2.418 37.804 27.822 ;
     RECT  37.804 21.456 40.208 21.48 ;
     RECT  40.208 2.148 40.312 28.092 ;
     RECT  40.312 2.418 40.504 27.822 ;
     RECT  40.504 21.456 42.908 21.48 ;
     RECT  42.908 2.148 43.012 28.092 ;
     RECT  43.012 2.418 43.204 27.822 ;
     RECT  45.109 27.936 45.253 27.96 ;
     RECT  43.204 21.456 45.608 21.48 ;
     RECT  45.253 27.936 45.608 28.056 ;
     RECT  45.608 2.148 45.712 28.092 ;
     RECT  45.712 2.418 45.904 27.96 ;
     RECT  46.033 29.04 46.403 29.064 ;
     RECT  45.904 27.12 47.185 27.96 ;
     RECT  46.861 29.712 47.329 29.736 ;
     RECT  47.329 29.712 47.401 30.12 ;
     RECT  47.185 27.12 47.617 28.536 ;
     RECT  47.617 27.072 47.653 28.536 ;
     RECT  47.401 29.616 47.939 30.12 ;
     RECT  45.904 21.456 48.308 21.48 ;
     RECT  45.904 24.768 48.308 24.792 ;
     RECT  47.653 26.88 48.308 28.536 ;
     RECT  48.308 2.148 48.412 28.536 ;
     RECT  48.412 2.418 48.445 28.536 ;
     RECT  47.939 29.616 48.445 29.784 ;
     RECT  48.445 2.418 48.604 29.784 ;
     RECT  48.604 26.88 48.845 29.784 ;
     RECT  48.845 26.88 48.953 29.736 ;
     RECT  48.953 26.88 49.379 27.96 ;
     RECT  48.604 23.04 49.529 23.88 ;
     RECT  48.953 29.088 49.667 29.736 ;
     RECT  49.667 29.616 49.811 29.736 ;
     RECT  48.604 21.456 49.885 21.48 ;
     RECT  49.379 27.936 49.955 27.96 ;
     RECT  49.379 26.88 50.065 26.904 ;
     RECT  50.065 26.784 50.453 26.904 ;
     RECT  50.453 26.544 50.461 26.904 ;
     RECT  50.461 26.544 50.569 27.384 ;
     RECT  49.885 21.456 50.749 21.672 ;
     RECT  49.529 23.04 50.749 23.16 ;
     RECT  50.569 26.016 50.785 27.384 ;
     RECT  49.811 29.664 50.821 29.736 ;
     RECT  50.821 29.664 50.893 30.072 ;
     RECT  50.749 21.456 51.008 23.16 ;
     RECT  50.785 25.968 51.008 27.384 ;
     RECT  50.893 29.04 51.008 30.072 ;
     RECT  51.008 2.148 51.107 30.072 ;
     RECT  51.107 2.148 51.112 29.976 ;
     RECT  51.112 2.418 51.251 29.976 ;
     RECT  51.251 2.418 51.304 29.064 ;
     RECT  51.304 25.68 51.491 29.064 ;
     RECT  51.491 25.68 51.923 27.384 ;
     RECT  51.491 28.416 52.193 29.064 ;
     RECT  51.923 25.68 52.229 27.192 ;
     RECT  51.304 24.624 52.265 24.648 ;
     RECT  51.304 21.456 52.445 22.344 ;
     RECT  52.193 28.512 52.445 29.064 ;
     RECT  51.304 23.376 52.765 23.4 ;
     RECT  52.229 25.68 52.789 26.808 ;
     RECT  52.445 29.04 52.805 29.064 ;
     RECT  53.125 2.544 53.708 2.568 ;
     RECT  52.445 21.456 53.708 21.672 ;
     RECT  52.765 23.376 53.708 24.408 ;
     RECT  52.789 25.632 53.708 26.808 ;
     RECT  53.653 28.272 53.708 28.296 ;
     RECT  53.708 2.148 53.812 28.296 ;
     RECT  53.812 2.418 54.004 28.296 ;
     RECT  53.557 30.048 54.131 30.072 ;
     RECT  54.004 23.808 54.137 28.296 ;
     RECT  54.137 23.808 54.179 27.432 ;
     RECT  54.179 23.808 54.563 26.76 ;
     RECT  54.493 29.04 54.577 29.064 ;
     RECT  54.563 23.808 54.677 26.328 ;
     RECT  54.677 23.808 54.785 25.896 ;
     RECT  54.004 21.456 54.997 22.248 ;
     RECT  54.785 23.808 54.997 25.8 ;
     RECT  55.169 27.408 55.253 27.432 ;
     RECT  54.997 21.456 55.897 25.8 ;
     RECT  55.957 29.04 56.099 29.064 ;
     RECT  56.101 30.048 56.149 30.072 ;
     RECT  54.004 2.544 56.408 2.568 ;
     RECT  55.897 21.456 56.408 26.856 ;
     RECT  56.245 28.512 56.408 28.536 ;
     RECT  56.149 29.952 56.435 30.072 ;
     RECT  56.408 2.148 56.512 28.536 ;
     RECT  56.512 2.418 56.704 28.536 ;
     RECT  56.435 30.048 57.011 30.072 ;
     RECT  56.704 21.456 57.059 27.528 ;
     RECT  57.059 21.456 57.107 27.432 ;
     RECT  57.107 21.456 57.125 27.384 ;
     RECT  56.704 28.512 57.377 28.536 ;
     RECT  57.397 29.04 57.539 29.064 ;
     RECT  57.125 21.456 58.309 21.72 ;
     RECT  57.125 22.752 58.309 27.384 ;
     RECT  58.693 29.04 58.789 29.064 ;
     RECT  58.789 28.944 58.837 29.064 ;
     RECT  58.693 30.048 58.837 30.072 ;
     RECT  58.837 28.944 58.931 30.072 ;
     RECT  58.931 29.952 58.979 30.072 ;
     RECT  56.704 2.544 59.108 2.568 ;
     RECT  58.309 21.456 59.108 27.384 ;
     RECT  59.108 2.148 59.212 28.536 ;
     RECT  59.212 2.418 59.404 28.536 ;
     RECT  58.979 30 59.555 30.072 ;
     RECT  59.555 30 59.651 30.024 ;
     RECT  59.404 28.512 60.221 28.536 ;
     RECT  60.709 29.04 60.833 29.064 ;
     RECT  59.404 2.544 61.225 2.568 ;
     RECT  59.404 21.216 61.381 27.384 ;
     RECT  61.225 2.064 61.808 2.568 ;
     RECT  61.381 21.216 61.808 28.248 ;
     RECT  61.808 2.064 61.907 28.248 ;
     RECT  60.997 30.048 62.051 30.072 ;
     RECT  61.907 2.064 62.104 28.2 ;
     RECT  62.104 27.936 62.291 28.2 ;
     RECT  62.104 21.216 63.205 26.808 ;
     RECT  62.291 27.936 63.205 27.96 ;
     RECT  63.205 21.216 63.209 27.96 ;
     RECT  63.457 19.344 63.733 19.368 ;
     RECT  63.733 19.152 63.781 19.368 ;
     RECT  63.301 29.616 64.412 29.64 ;
     RECT  64.412 29.088 64.499 29.64 ;
     RECT  62.104 2.064 64.508 2.568 ;
     RECT  63.781 18.48 64.508 19.368 ;
     RECT  63.209 21.216 64.508 27.144 ;
     RECT  64.499 29.616 64.597 29.64 ;
     RECT  64.508 2.064 64.789 28.092 ;
     RECT  64.597 29.616 64.789 29.928 ;
     RECT  64.789 2.064 64.804 28.2 ;
     RECT  64.804 21.216 65.123 28.2 ;
     RECT  64.789 29.616 65.365 30.024 ;
     RECT  65.365 29.616 65.653 30.072 ;
     RECT  65.653 29.088 66.083 30.072 ;
     RECT  66.083 29.616 66.125 30.072 ;
     RECT  64.804 2.064 67.208 2.568 ;
     RECT  64.804 18.48 67.208 18.504 ;
     RECT  65.123 21.216 67.208 27.384 ;
     RECT  67.208 2.064 67.333 28.092 ;
     RECT  67.333 2.064 67.504 28.248 ;
     RECT  67.504 21.216 67.601 28.248 ;
     RECT  66.125 30.048 67.621 30.072 ;
     RECT  67.621 29.04 67.714 30.072 ;
     RECT  67.714 29.04 67.763 30.12 ;
     RECT  67.763 29.856 67.781 30.12 ;
     RECT  67.781 29.952 67.811 30.12 ;
     RECT  67.601 21.216 68.965 27.384 ;
     RECT  67.811 30.096 69.205 30.12 ;
     RECT  68.965 21.216 69.397 27.432 ;
     RECT  69.205 30.048 69.637 30.12 ;
     RECT  69.637 29.952 69.827 30.12 ;
     RECT  69.827 30.048 69.833 30.12 ;
     RECT  67.504 2.064 69.908 2.568 ;
     RECT  67.504 18.48 69.908 18.504 ;
     RECT  69.397 21.216 69.908 27.528 ;
     RECT  68.629 28.512 69.908 28.536 ;
     RECT  69.908 2.064 70.115 28.536 ;
     RECT  70.115 2.064 70.204 27.864 ;
     RECT  70.357 28.848 70.517 28.872 ;
     RECT  70.204 21.216 70.777 27.864 ;
     RECT  70.789 28.944 70.877 28.968 ;
     RECT  69.833 30.048 72.083 30.072 ;
     RECT  71.797 28.512 72.469 28.536 ;
     RECT  70.777 21.216 72.565 27.432 ;
     RECT  72.469 28.512 72.565 29.064 ;
     RECT  70.204 2.064 72.608 2.568 ;
     RECT  70.204 18.48 72.608 18.504 ;
     RECT  72.565 21.216 72.608 29.064 ;
     RECT  72.608 2.064 72.851 29.064 ;
     RECT  72.851 2.064 72.904 28.536 ;
     RECT  72.949 29.904 73.093 29.928 ;
     RECT  73.093 29.904 73.139 30.024 ;
     RECT  73.139 30 73.235 30.024 ;
     RECT  72.904 28.512 73.859 28.536 ;
     RECT  72.904 21.216 74.581 27.384 ;
     RECT  74.581 21.216 74.617 27.432 ;
     RECT  74.677 29.904 74.821 29.928 ;
     RECT  74.821 29.904 74.867 30.024 ;
     RECT  74.617 21.216 75.253 27.528 ;
     RECT  72.904 2.064 75.308 2.568 ;
     RECT  72.904 18.48 75.308 18.504 ;
     RECT  75.253 21.216 75.308 28.248 ;
     RECT  74.867 29.952 75.397 30.024 ;
     RECT  75.308 2.064 75.604 28.248 ;
     RECT  75.604 27.936 75.685 28.248 ;
     RECT  75.397 29.952 75.779 30.072 ;
     RECT  75.779 30.048 75.827 30.072 ;
     RECT  75.685 27.936 75.829 28.344 ;
     RECT  75.829 27.936 75.971 28.44 ;
     RECT  75.971 27.936 76.817 27.96 ;
     RECT  75.604 21.216 76.853 26.856 ;
     RECT  76.741 29.04 76.883 29.064 ;
     RECT  77.269 30.048 77.569 30.072 ;
     RECT  77.569 29.088 77.747 30.072 ;
     RECT  76.853 21.216 77.845 26.664 ;
     RECT  77.747 29.904 77.891 30.072 ;
     RECT  75.604 2.064 78.008 2.568 ;
     RECT  75.604 18.48 78.008 18.504 ;
     RECT  77.845 21.216 78.008 27.096 ;
     RECT  77.891 30 78.035 30.072 ;
     RECT  78.008 2.064 78.133 28.092 ;
     RECT  78.133 2.064 78.304 28.536 ;
     RECT  78.035 30.048 78.563 30.072 ;
     RECT  78.304 21.216 78.581 28.536 ;
     RECT  78.581 21.216 78.905 27.672 ;
     RECT  79.285 29.04 79.427 29.064 ;
     RECT  78.905 21.216 79.667 27.144 ;
     RECT  80.149 30.048 80.485 30.072 ;
     RECT  78.304 2.064 80.708 2.568 ;
     RECT  78.304 18.48 80.708 18.504 ;
     RECT  79.667 21.216 80.708 26.856 ;
     RECT  79.861 28.512 80.708 28.536 ;
     RECT  80.485 29.952 80.915 30.072 ;
     RECT  80.708 2.064 81.004 28.536 ;
     RECT  81.004 21.216 81.109 28.536 ;
     RECT  81.109 21.216 81.155 29.064 ;
     RECT  80.915 30.048 81.155 30.072 ;
     RECT  81.155 21.216 81.497 27.384 ;
     RECT  81.155 29.04 82.073 29.064 ;
     RECT  81.497 21.216 83.185 26.76 ;
     RECT  83.125 28.176 83.185 28.2 ;
     RECT  83.185 21.216 83.365 28.2 ;
     RECT  81.004 2.064 83.408 2.568 ;
     RECT  81.004 18.48 83.408 18.504 ;
     RECT  83.365 21.216 83.408 28.536 ;
     RECT  83.408 2.064 83.461 28.536 ;
     RECT  83.461 2.064 83.704 28.824 ;
     RECT  83.704 28.512 83.795 28.824 ;
     RECT  83.795 28.8 83.801 28.824 ;
     RECT  83.704 21.216 83.891 27.48 ;
     RECT  83.891 21.216 84.565 27.384 ;
     RECT  84.565 29.04 84.613 29.064 ;
     RECT  82.453 30.048 84.613 30.072 ;
     RECT  84.613 29.04 84.947 30.072 ;
     RECT  84.565 21.216 84.96 27.336 ;
     RECT  85.129 28.512 85.235 28.536 ;
     RECT  84.947 29.952 86.053 30.072 ;
     RECT  83.704 2.064 86.108 2.568 ;
     RECT  83.704 18.48 86.108 18.504 ;
     RECT  84.96 21.216 86.108 26.76 ;
     RECT  86.053 29.808 86.197 30.072 ;
     RECT  86.108 2.064 86.389 28.092 ;
     RECT  86.389 2.064 86.404 28.2 ;
     RECT  86.404 21.216 86.465 26.856 ;
     RECT  86.197 29.712 86.627 30.072 ;
     RECT  86.404 28.176 86.629 28.2 ;
     RECT  86.629 28.176 86.675 29.064 ;
     RECT  86.465 21.456 86.771 26.856 ;
     RECT  86.773 30.096 87.041 30.12 ;
     RECT  86.675 29.04 87.059 29.064 ;
     RECT  87.596 29.088 87.683 29.112 ;
     RECT  86.771 21.456 87.925 26.808 ;
     RECT  86.404 2.064 88.808 2.568 ;
     RECT  86.404 18.48 88.808 18.504 ;
     RECT  87.925 21.456 88.808 27.144 ;
     RECT  88.808 2.064 88.912 28.092 ;
     RECT  88.912 2.064 89.104 27.912 ;
     RECT  89.104 23.376 89.165 27.912 ;
     RECT  89.104 21.696 89.507 22.056 ;
     RECT  89.165 26.208 89.813 27.912 ;
     RECT  89.813 26.208 89.849 27.384 ;
     RECT  89.849 26.4 89.939 27.384 ;
     RECT  90.037 29.04 90.061 29.064 ;
     RECT  89.104 2.064 90.277 2.568 ;
     RECT  89.104 18.48 90.323 18.504 ;
     RECT  90.277 2.064 90.389 3.96 ;
     RECT  89.165 23.376 90.601 24.984 ;
     RECT  89.507 21.936 90.637 22.056 ;
     RECT  90.601 23.136 90.637 24.984 ;
     RECT  90.637 21.936 90.673 24.984 ;
     RECT  90.061 28.416 90.709 29.064 ;
     RECT  90.709 28.416 90.803 29.112 ;
     RECT  90.389 2.064 90.901 2.568 ;
     RECT  89.939 26.4 90.997 27.336 ;
     RECT  90.803 28.416 90.997 28.536 ;
     RECT  90.673 21.888 91.069 24.984 ;
     RECT  90.889 0.096 91.091 0.12 ;
     RECT  90.901 1.728 91.109 2.568 ;
     RECT  91.069 21.888 91.141 25.32 ;
     RECT  90.997 26.4 91.141 28.536 ;
     RECT  91.141 21.888 91.379 28.536 ;
     RECT  91.285 30 91.381 30.024 ;
     RECT  91.109 2.064 91.508 2.568 ;
     RECT  90.389 3.936 91.508 3.96 ;
     RECT  91.379 21.888 91.508 28.092 ;
     RECT  91.508 2.064 91.612 28.092 ;
     RECT  91.612 2.064 91.804 27.822 ;
     RECT  91.381 30 92.053 30.072 ;
     RECT  91.897 0.576 92.195 0.6 ;
     RECT  91.804 21.792 92.291 27.432 ;
     RECT  91.804 2.064 92.293 3.288 ;
     RECT  92.291 21.792 92.297 26.712 ;
     RECT  92.257 0.096 92.483 0.12 ;
     RECT  92.053 29.904 92.509 30.072 ;
     RECT  92.293 1.728 92.797 3.288 ;
     RECT  92.509 29.664 92.867 30.072 ;
     RECT  92.867 29.664 92.873 29.688 ;
     RECT  92.797 1.104 93.059 3.288 ;
     RECT  92.917 27.936 93.157 27.96 ;
     RECT  92.297 21.792 93.308 26.616 ;
     RECT  93.061 29.616 93.308 29.64 ;
     RECT  93.308 29.088 93.341 29.64 ;
     RECT  93.308 21.792 93.373 26.712 ;
     RECT  93.157 27.936 93.373 28.008 ;
     RECT  93.341 29.088 93.395 29.112 ;
     RECT  93.373 21.792 94.069 28.008 ;
     RECT  93.059 1.728 94.208 3.288 ;
     RECT  94.069 21.792 94.208 29.064 ;
     RECT  94.124 0.528 94.211 0.552 ;
     RECT  94.208 1.728 94.504 29.064 ;
     RECT  94.504 1.728 94.669 3.144 ;
     RECT  94.504 28.176 94.691 29.064 ;
     RECT  94.597 0.144 94.739 0.168 ;
     RECT  94.504 21.552 94.739 27.144 ;
     RECT  94.669 1.152 94.753 3.144 ;
     RECT  94.691 28.224 94.787 29.064 ;
     RECT  94.981 30.048 95.221 30.072 ;
     RECT  95.221 30.048 95.357 30.12 ;
     RECT  94.739 21.552 95.459 26.808 ;
     RECT  94.787 28.464 95.557 29.064 ;
     RECT  95.357 30.048 95.557 30.072 ;
     RECT  95.459 21.888 95.797 26.808 ;
     RECT  95.797 21.888 96.065 26.856 ;
     RECT  94.753 1.728 96.253 3.144 ;
     RECT  96.253 1.728 96.284 3.192 ;
     RECT  96.284 1.104 96.325 3.192 ;
     RECT  96.325 1.104 96.371 3.336 ;
     RECT  95.557 28.464 96.517 30.072 ;
     RECT  96.517 28.176 96.755 30.072 ;
     RECT  96.065 21.888 96.901 26.904 ;
     RECT  96.371 1.728 96.908 3.336 ;
     RECT  96.901 21.168 96.908 26.904 ;
     RECT  96.755 28.176 96.908 28.2 ;
     RECT  96.908 1.728 97.204 28.2 ;
     RECT  96.755 29.616 97.379 30.072 ;
     RECT  97.379 29.616 97.445 29.64 ;
     RECT  97.204 21.648 98.341 27.144 ;
     RECT  98.341 21.648 98.809 27.384 ;
     RECT  98.809 21.12 99.349 27.384 ;
     RECT  97.909 28.512 99.349 28.536 ;
     RECT  99.349 21.12 99.529 28.536 ;
     RECT  97.204 1.728 99.608 3.192 ;
     RECT  99.529 21.12 99.608 29.064 ;
     RECT  99.397 0.144 99.683 0.168 ;
     RECT  99.608 1.728 99.781 29.064 ;
     RECT  99.781 1.632 99.904 29.064 ;
     RECT  99.904 1.632 100.037 3.384 ;
     RECT  99.904 21.648 100.145 27.384 ;
     RECT  99.904 28.512 100.333 29.064 ;
     RECT  98.437 30.048 100.883 30.072 ;
     RECT  100.037 1.728 100.973 3.384 ;
     RECT  100.145 21.648 101.125 26.664 ;
     RECT  101.125 21.648 101.149 26.808 ;
     RECT  101.149 21.648 101.233 27.384 ;
     RECT  100.333 28.512 101.413 28.536 ;
     RECT  101.413 28.464 101.891 28.536 ;
     RECT  102.037 30.048 102.085 30.072 ;
     RECT  100.973 1.728 102.133 3.24 ;
     RECT  102.085 29.904 102.133 30.072 ;
     RECT  102.133 1.728 102.308 3.336 ;
     RECT  101.233 21.648 102.308 27.096 ;
     RECT  101.891 28.464 102.308 28.488 ;
     RECT  102.308 1.728 102.604 28.488 ;
     RECT  102.133 29.808 102.611 30.072 ;
     RECT  102.604 1.728 102.665 3.336 ;
     RECT  102.604 21.408 102.755 27.096 ;
     RECT  102.133 0.144 102.803 0.168 ;
     RECT  102.604 28.464 103.169 28.488 ;
     RECT  102.755 21.408 103.457 26.808 ;
     RECT  103.457 21.936 103.601 26.808 ;
     RECT  102.665 1.728 103.741 3.192 ;
     RECT  103.741 1.728 103.745 3.288 ;
     RECT  103.601 22.032 103.813 26.808 ;
     RECT  103.745 1.824 104.641 3.288 ;
     RECT  104.641 1.824 104.821 3.336 ;
     RECT  104.821 1.824 104.893 3.384 ;
     RECT  104.893 1.824 104.929 3.432 ;
     RECT  104.929 1.776 105.008 3.432 ;
     RECT  104.569 6.816 105.008 6.84 ;
     RECT  103.813 22.032 105.008 27.384 ;
     RECT  105.008 1.776 105.109 28.092 ;
     RECT  105.109 1.728 105.157 28.092 ;
     RECT  105.253 0.336 105.301 0.36 ;
     RECT  102.611 30.048 105.301 30.072 ;
     RECT  105.157 1.728 105.304 28.2 ;
     RECT  105.301 29.616 105.401 30.072 ;
     RECT  105.301 0.24 105.443 0.36 ;
     RECT  105.401 29.952 105.443 30.072 ;
     RECT  105.304 21.168 105.491 28.2 ;
     RECT  105.443 29.952 105.587 29.976 ;
     RECT  105.491 21.168 105.985 27.864 ;
     RECT  105.304 1.728 106.297 3.432 ;
     RECT  106.297 1.728 106.517 3.528 ;
     RECT  105.985 21.168 106.561 27.384 ;
     RECT  106.597 30.096 106.876 30.12 ;
     RECT  106.876 30.048 106.877 30.12 ;
     RECT  106.873 28.512 107.461 28.536 ;
     RECT  106.877 30.048 107.605 30.072 ;
     RECT  106.517 1.728 107.641 3.432 ;
     RECT  107.641 1.824 107.669 3.432 ;
     RECT  107.669 1.92 107.708 3.432 ;
     RECT  106.561 21.168 107.708 27.144 ;
     RECT  107.461 28.512 107.708 28.824 ;
     RECT  107.708 1.92 107.812 28.824 ;
     RECT  107.605 29.856 107.893 30.072 ;
     RECT  107.812 1.92 108.004 27.822 ;
     RECT  107.893 29.856 108.209 30.12 ;
     RECT  108.209 29.856 108.323 30.072 ;
     RECT  108.469 29.04 108.611 29.064 ;
     RECT  108.004 1.92 108.785 3.432 ;
     RECT  108.004 22.032 108.785 27.384 ;
     RECT  108.785 1.92 108.989 3.144 ;
     RECT  108.785 22.128 109.393 27.384 ;
     RECT  109.429 28.512 109.523 28.536 ;
     RECT  108.323 30.048 110.005 30.072 ;
     RECT  110.005 29.904 110.149 30.072 ;
     RECT  109.393 22.128 110.365 27.432 ;
     RECT  108.989 1.728 110.408 3.144 ;
     RECT  110.365 21.936 110.408 27.432 ;
     RECT  110.149 29.856 110.531 30.072 ;
     RECT  110.408 1.728 110.704 28.092 ;
     RECT  110.245 0.144 110.819 0.168 ;
     RECT  110.704 1.728 110.819 3.336 ;
     RECT  110.704 21.648 111.593 27.384 ;
     RECT  110.876 28.512 111.665 28.536 ;
     RECT  111.593 21.648 111.683 26.904 ;
     RECT  110.819 1.728 112.021 3.144 ;
     RECT  112.021 1.728 112.105 3.192 ;
     RECT  112.597 28.896 112.693 28.92 ;
     RECT  111.683 21.648 112.733 26.808 ;
     RECT  112.693 28.896 112.796 29.016 ;
     RECT  110.531 30.048 112.796 30.072 ;
     RECT  112.796 28.896 112.933 30.072 ;
     RECT  112.933 28.224 112.979 30.072 ;
     RECT  112.105 1.728 113.108 3.144 ;
     RECT  112.733 21.648 113.108 26.856 ;
     RECT  112.979 28.224 113.108 28.296 ;
     RECT  113.108 1.728 113.123 28.296 ;
     RECT  113.123 1.728 113.267 28.248 ;
     RECT  113.267 1.728 113.404 28.2 ;
     RECT  113.404 21.936 113.603 28.2 ;
     RECT  112.979 29.952 113.747 30.072 ;
     RECT  113.747 29.952 113.795 29.976 ;
     RECT  113.404 1.728 113.833 3.192 ;
     RECT  113.603 21.936 114.473 27.96 ;
     RECT  113.833 1.728 114.893 2.952 ;
     RECT  114.473 21.936 115.477 27.384 ;
     RECT  114.893 1.728 115.808 3.048 ;
     RECT  115.513 6.528 115.808 6.552 ;
     RECT  115.477 21.408 115.808 27.384 ;
     RECT  115.729 28.512 115.808 28.536 ;
     RECT  116.053 0.336 116.101 0.36 ;
     RECT  115.808 1.728 116.104 28.536 ;
     RECT  116.104 21.408 116.147 28.536 ;
     RECT  116.101 0.144 116.243 0.36 ;
     RECT  115.237 30.048 116.243 30.072 ;
     RECT  116.147 21.408 116.291 28.2 ;
     RECT  116.291 27.696 116.387 28.2 ;
     RECT  116.387 27.696 116.435 27.72 ;
     RECT  116.389 29.904 116.579 30.024 ;
     RECT  116.579 30 116.675 30.024 ;
     RECT  116.104 1.728 116.819 3.24 ;
     RECT  116.291 21.408 117.269 26.712 ;
     RECT  116.819 1.728 117.781 3.144 ;
     RECT  117.269 21.408 117.853 26.76 ;
     RECT  117.853 21.12 117.925 26.76 ;
     RECT  117.925 21.12 118.261 27.384 ;
     RECT  118.213 28.512 118.261 28.536 ;
     RECT  118.261 21.12 118.307 28.536 ;
     RECT  117.781 1.728 118.309 3.24 ;
     RECT  118.307 21.12 118.451 28.2 ;
     RECT  118.309 1.728 118.508 3.336 ;
     RECT  118.451 21.12 118.508 28.092 ;
     RECT  118.309 0.144 118.547 0.168 ;
     RECT  118.508 1.728 118.612 28.092 ;
     RECT  118.549 29.856 118.693 29.88 ;
     RECT  118.612 1.728 118.804 27.822 ;
     RECT  118.804 1.728 118.937 3.096 ;
     RECT  118.693 29.856 119.125 30.024 ;
     RECT  119.125 29.808 119.269 30.024 ;
     RECT  118.937 1.776 119.737 3.096 ;
     RECT  118.804 21.12 119.795 27.432 ;
     RECT  118.804 12.912 119.845 12.936 ;
     RECT  119.269 29.808 119.845 30.072 ;
     RECT  119.737 1.776 119.941 3.048 ;
     RECT  119.941 1.728 119.945 3.048 ;
     RECT  119.845 29.616 119.981 30.072 ;
     RECT  119.845 12.48 120.661 12.936 ;
     RECT  120.565 29.04 120.707 29.064 ;
     RECT  120.661 12.48 120.901 13.08 ;
     RECT  119.945 1.728 121.093 2.952 ;
     RECT  120.901 12 121.093 13.08 ;
     RECT  121.093 1.728 121.208 3.336 ;
     RECT  121.093 11.952 121.208 13.08 ;
     RECT  119.795 21.12 121.208 26.856 ;
     RECT  120.901 28.224 121.208 28.776 ;
     RECT  119.981 30.048 121.331 30.072 ;
     RECT  120.997 0.144 121.427 0.168 ;
     RECT  121.208 1.728 121.504 28.776 ;
     RECT  121.504 21.12 121.717 28.776 ;
     RECT  121.717 21.12 121.781 29.064 ;
     RECT  121.781 27.648 121.817 29.064 ;
     RECT  121.817 27.648 122.099 28.776 ;
     RECT  121.781 21.12 122.531 26.328 ;
     RECT  121.504 11.952 122.533 13.368 ;
     RECT  121.504 1.728 122.605 2.952 ;
     RECT  122.705 30.048 122.749 30.072 ;
     RECT  122.531 22.224 122.78 26.328 ;
     RECT  122.099 28.176 122.821 28.776 ;
     RECT  122.533 11.952 122.965 13.656 ;
     RECT  122.749 30.048 123.181 30.168 ;
     RECT  123.109 0.096 123.221 0.12 ;
     RECT  122.531 21.12 123.613 21.144 ;
     RECT  122.78 22.224 123.613 26.616 ;
     RECT  122.821 28.176 123.613 28.824 ;
     RECT  123.613 21.12 123.685 21.192 ;
     RECT  123.613 22.224 123.685 28.824 ;
     RECT  123.181 30.048 123.713 30.216 ;
     RECT  123.685 21.12 123.733 28.824 ;
     RECT  123.713 29.808 123.733 30.216 ;
     RECT  122.605 1.728 123.908 3.144 ;
     RECT  122.965 11.424 123.908 13.656 ;
     RECT  123.733 21.12 123.908 30.216 ;
     RECT  123.908 1.728 123.923 30.216 ;
     RECT  123.923 1.728 124.204 28.776 ;
     RECT  124.204 21.12 124.355 28.776 ;
     RECT  124.355 21.12 124.589 24.984 ;
     RECT  124.204 1.728 124.796 3.144 ;
     RECT  124.796 1.104 124.883 3.144 ;
     RECT  124.355 26.16 124.883 28.776 ;
     RECT  124.883 26.16 124.921 26.328 ;
     RECT  124.204 12 125.101 13.656 ;
     RECT  125.101 12.048 125.173 13.656 ;
     RECT  125.173 12.528 125.237 13.656 ;
     RECT  125.233 18.816 125.345 18.84 ;
     RECT  123.923 30.048 125.461 30.216 ;
     RECT  124.883 27.36 126.061 28.776 ;
     RECT  125.461 30 126.061 30.216 ;
     RECT  124.589 22.032 126.133 24.984 ;
     RECT  125.237 12.912 126.385 13.656 ;
     RECT  124.921 26.304 126.469 26.328 ;
     RECT  126.061 27.36 126.469 30.216 ;
     RECT  124.883 1.728 126.608 3.144 ;
     RECT  126.385 12.528 126.608 13.656 ;
     RECT  126.133 21.696 126.608 24.984 ;
     RECT  126.469 26.304 126.608 30.216 ;
     RECT  126.608 1.728 126.904 30.216 ;
     RECT  126.904 26.256 127.091 30.216 ;
     RECT  126.904 21.648 127.235 24.984 ;
     RECT  127.235 21.648 127.397 23.352 ;
     RECT  127.477 0.144 127.619 0.168 ;
     RECT  127.397 21.648 127.873 22.824 ;
     RECT  127.873 21.648 128.041 22.776 ;
     RECT  127.091 26.64 128.045 28.776 ;
     RECT  126.904 12.432 128.197 13.08 ;
     RECT  128.045 27.312 128.225 28.776 ;
     RECT  128.041 21.12 128.261 22.776 ;
     RECT  128.197 12.336 128.905 13.08 ;
     RECT  129.061 0.144 129.203 0.168 ;
     RECT  126.904 1.728 129.308 3.144 ;
     RECT  128.653 6.816 129.308 6.84 ;
     RECT  128.905 12 129.308 13.08 ;
     RECT  128.261 22.032 129.308 22.776 ;
     RECT  127.235 24.624 129.308 24.984 ;
     RECT  128.225 27.36 129.308 28.776 ;
     RECT  129.308 1.728 129.604 28.776 ;
     RECT  129.604 12.24 129.629 12.504 ;
     RECT  127.091 30.048 129.665 30.216 ;
     RECT  129.665 30.192 129.701 30.216 ;
     RECT  129.629 12.24 129.731 12.264 ;
     RECT  129.604 24.96 129.953 24.984 ;
     RECT  129.604 27.36 129.953 28.776 ;
     RECT  129.953 27.36 129.989 27.672 ;
     RECT  129.604 1.728 130.097 3.144 ;
     RECT  130.097 1.728 130.241 2.952 ;
     RECT  130.241 1.728 130.313 2.664 ;
     RECT  129.989 27.456 130.529 27.672 ;
     RECT  130.313 1.776 130.709 2.664 ;
     RECT  129.953 28.752 131.033 28.776 ;
     RECT  130.709 1.776 131.353 2.568 ;
     RECT  131.353 1.728 131.677 2.568 ;
     RECT  131.677 1.152 131.713 2.568 ;
     RECT  131.713 1.152 131.761 2.904 ;
     RECT  131.761 1.68 132.008 2.904 ;
     RECT  130.529 27.456 132.008 27.48 ;
     RECT  132.008 1.68 132.112 28.092 ;
     RECT  132.112 1.68 132.304 27.822 ;
     RECT  132.304 1.68 132.812 2.568 ;
     RECT  132.812 1.104 132.899 2.568 ;
     RECT  132.899 1.728 134.708 2.568 ;
     RECT  134.708 1.728 134.812 28.092 ;
     RECT  134.812 1.728 135.004 27.822 ;
     RECT  134.881 0.528 135.203 0.552 ;
     RECT  135.004 1.728 136 2.904 ;
     RECT  136 1.728 136.133 2.952 ;
     RECT  136.133 1.728 136.217 3.048 ;
     RECT  136.217 1.728 137.408 2.904 ;
     RECT  137.408 1.728 137.512 28.092 ;
     RECT  137.512 1.728 137.704 27.822 ;
     RECT  137.704 1.728 139.445 2.952 ;
     RECT  139.445 1.728 140.108 3.24 ;
     RECT  140.108 1.728 140.212 28.092 ;
     RECT  140.212 1.728 140.404 27.822 ;
     RECT  140.404 1.728 140.897 2.952 ;
     RECT  142.44 0.576 142.561 0.6 ;
     RECT  140.897 1.728 142.808 2.904 ;
     RECT  142.808 1.728 142.912 28.092 ;
     RECT  142.912 1.728 143.104 27.822 ;
     RECT  143.104 1.728 144.085 2.952 ;
     RECT  144.085 1.728 144.281 3.096 ;
     RECT  144.281 1.728 145.508 2.952 ;
     RECT  145.508 1.728 145.612 28.092 ;
     RECT  145.612 1.728 145.804 27.822 ;
     RECT  145.804 1.728 146.657 3.144 ;
     RECT  146.657 1.728 147.011 3.096 ;
     RECT  147.685 0.096 147.953 0.12 ;
     RECT  147.011 1.728 148.208 3 ;
     RECT  148.208 1.728 148.312 28.092 ;
     RECT  148.312 1.728 148.504 27.822 ;
     RECT  148.504 1.728 149.185 3.192 ;
     RECT  149.185 1.728 150.469 2.952 ;
     RECT  150.469 1.728 150.908 3.144 ;
     RECT  150.908 1.728 151.012 28.092 ;
     RECT  151.012 1.728 151.204 27.822 ;
     RECT  151.204 1.728 152.869 2.904 ;
     RECT  152.869 1.728 153.493 3 ;
     RECT  153.493 1.728 153.608 3.048 ;
     RECT  153.608 1.728 153.712 28.092 ;
     RECT  153.493 0.144 153.779 0.168 ;
     RECT  153.712 1.728 153.904 27.822 ;
     RECT  153.877 0.096 154.001 0.12 ;
     RECT  153.904 1.728 154.577 3.144 ;
     RECT  154.577 1.728 155.893 2.904 ;
     RECT  155.893 1.728 156.308 3.096 ;
     RECT  156.308 1.728 156.412 28.092 ;
     RECT  156.412 1.728 156.604 27.822 ;
     RECT  156.469 0.144 156.755 0.168 ;
     RECT  156.604 1.728 157.133 3.096 ;
     RECT  157.133 1.728 158.173 2.952 ;
     RECT  158.821 0.144 158.963 0.168 ;
     RECT  158.173 1.728 159.008 3.336 ;
     RECT  159.008 1.728 159.112 28.092 ;
     RECT  159.112 1.728 159.304 27.822 ;
     RECT  159.304 1.728 160.589 3.096 ;
     RECT  160.589 1.728 161.557 3 ;
     RECT  161.557 1.728 161.708 3.048 ;
     RECT  161.708 1.728 161.812 28.092 ;
     RECT  161.557 0.144 161.843 0.168 ;
     RECT  161.812 1.728 162.004 27.822 ;
     RECT  162.004 1.728 164.408 3.096 ;
     RECT  164.408 1.728 164.512 28.092 ;
     RECT  164.512 1.728 164.704 27.822 ;
     RECT  164.704 1.728 164.945 3.096 ;
     RECT  164.945 1.728 166.093 1.848 ;
     RECT  164.945 2.88 166.693 3.096 ;
     RECT  166.093 1.728 166.805 1.896 ;
     RECT  166.693 2.88 166.805 3.144 ;
     RECT  166.805 1.728 167.108 3.144 ;
     RECT  167.108 1.728 167.212 28.092 ;
     RECT  167.212 1.728 167.404 27.822 ;
     RECT  167.404 1.728 167.501 3.336 ;
     RECT  167.413 0.144 167.555 0.168 ;
     RECT  167.501 1.728 168.565 1.848 ;
     RECT  167.501 2.88 168.565 3.336 ;
     RECT  168.565 1.728 168.577 3.336 ;
     RECT  168.577 1.728 169.189 3.864 ;
     RECT  169.189 1.728 169.808 3.912 ;
     RECT  169.621 0.144 169.861 0.168 ;
     RECT  169.808 1.728 169.912 28.092 ;
     RECT  169.861 0.144 170.005 0.6 ;
     RECT  169.912 1.728 170.104 27.822 ;
     RECT  170.005 0.144 170.149 0.648 ;
     RECT  170.149 0.096 170.273 0.648 ;
     RECT  170.273 0.528 170.497 0.648 ;
     RECT  170.104 1.728 170.521 1.8 ;
     RECT  170.521 1.056 171.203 1.8 ;
     RECT  171.203 1.104 171.277 1.8 ;
     RECT  171.277 1.104 171.421 2.328 ;
     RECT  171.421 1.104 171.505 2.904 ;
     RECT  171.505 1.104 171.779 2.328 ;
     RECT  171.779 1.104 171.923 1.128 ;
     RECT  171.779 2.304 172.081 2.328 ;
    LAYER M5 ;
     RECT  90.912 0.016 91.08 0.131 ;
     RECT  92.16 0.016 130.344 0.611 ;
     RECT  90.912 0.131 90.936 1.763 ;
     RECT  131.424 0.016 172.056 1.763 ;
     RECT  92.304 0.611 130.344 1.811 ;
     RECT  132 1.763 172.056 1.811 ;
     RECT  92.88 1.811 129.912 1.859 ;
     RECT  132 1.811 170.112 1.859 ;
     RECT  133.872 1.859 170.112 1.907 ;
     RECT  2.4 2.137 2.52 2.151 ;
     RECT  5.1 2.137 5.22 2.151 ;
     RECT  7.8 2.137 7.92 2.151 ;
     RECT  10.5 2.137 10.62 2.151 ;
     RECT  13.2 2.137 13.32 2.151 ;
     RECT  15.9 2.137 16.02 2.151 ;
     RECT  18.6 2.137 18.72 2.151 ;
     RECT  21.3 2.137 21.42 2.151 ;
     RECT  24 2.137 24.12 2.151 ;
     RECT  26.7 2.137 26.82 2.151 ;
     RECT  29.4 2.137 29.52 2.151 ;
     RECT  32.1 2.137 32.22 2.151 ;
     RECT  34.8 2.137 34.92 2.151 ;
     RECT  37.5 2.137 37.62 2.151 ;
     RECT  40.2 2.137 40.32 2.151 ;
     RECT  42.9 2.137 43.02 2.151 ;
     RECT  45.6 2.137 45.72 2.151 ;
     RECT  48.3 2.137 48.42 2.151 ;
     RECT  51 2.137 51.12 2.151 ;
     RECT  53.7 2.137 53.82 2.151 ;
     RECT  56.4 2.137 56.52 2.151 ;
     RECT  59.1 2.137 59.22 2.151 ;
     RECT  61.8 2.137 61.92 2.151 ;
     RECT  64.5 2.137 64.62 2.151 ;
     RECT  67.2 2.137 67.32 2.151 ;
     RECT  69.9 2.137 70.02 2.151 ;
     RECT  72.6 2.137 72.72 2.151 ;
     RECT  75.3 2.137 75.42 2.151 ;
     RECT  78 2.137 78.12 2.151 ;
     RECT  80.7 2.137 80.82 2.151 ;
     RECT  83.4 2.137 83.52 2.151 ;
     RECT  86.1 2.137 86.22 2.151 ;
     RECT  88.8 2.137 88.92 2.151 ;
     RECT  92.88 1.859 92.904 2.291 ;
     RECT  94.2 1.859 129.912 2.291 ;
     RECT  134.7 1.907 170.112 2.291 ;
     RECT  171.312 1.811 172.056 2.339 ;
     RECT  94.2 2.291 106.008 2.915 ;
     RECT  106.992 2.291 129.768 2.915 ;
     RECT  134.7 2.291 153.912 2.915 ;
     RECT  154.896 2.291 167.88 2.915 ;
     RECT  171.456 2.339 171.48 2.915 ;
     RECT  99.072 2.915 102.792 2.963 ;
     RECT  104.256 2.915 106.008 2.963 ;
     RECT  107.136 2.915 119.688 2.963 ;
     RECT  120.816 2.915 129.768 2.963 ;
     RECT  136.032 2.915 136.2 2.963 ;
     RECT  137.4 2.915 140.664 2.963 ;
     RECT  142.8 2.915 149.736 2.963 ;
     RECT  155.904 2.915 160.536 2.963 ;
     RECT  101.952 2.963 102.612 3.011 ;
     RECT  110.256 2.963 113.784 3.011 ;
     RECT  145.5 2.963 149.16 3.011 ;
     RECT  152.88 2.915 153.912 3.011 ;
     RECT  166.704 2.915 167.544 3.011 ;
     RECT  94.2 2.915 97.32 3.059 ;
     RECT  107.7 2.963 108.888 3.059 ;
     RECT  110.256 3.011 110.808 3.059 ;
     RECT  114.912 2.963 119.688 3.059 ;
     RECT  120.912 2.963 127.512 3.059 ;
     RECT  136.176 2.963 136.2 3.059 ;
     RECT  153.504 3.011 153.912 3.059 ;
     RECT  161.568 2.915 165.72 3.059 ;
     RECT  99.072 2.963 100.824 3.107 ;
     RECT  107.7 3.059 108.744 3.107 ;
     RECT  112.032 3.011 113.784 3.107 ;
     RECT  117.792 3.059 119.688 3.107 ;
     RECT  144.096 2.963 144.12 3.107 ;
     RECT  145.5 3.011 147 3.107 ;
     RECT  155.904 2.963 157.08 3.107 ;
     RECT  158.352 2.963 160.536 3.107 ;
     RECT  161.7 3.059 165.72 3.107 ;
     RECT  94.2 3.059 97.212 3.155 ;
     RECT  120.912 3.059 127.032 3.155 ;
     RECT  166.704 3.011 167.412 3.155 ;
     RECT  96.288 3.155 97.212 3.203 ;
     RECT  112.032 3.107 112.056 3.203 ;
     RECT  113.1 3.107 113.784 3.203 ;
     RECT  148.2 3.011 149.16 3.203 ;
     RECT  99.6 3.107 100.824 3.251 ;
     RECT  115.8 3.059 116.808 3.251 ;
     RECT  117.792 3.107 118.812 3.251 ;
     RECT  139.488 2.963 140.412 3.251 ;
     RECT  158.352 3.107 159.312 3.251 ;
     RECT  102.144 3.011 102.612 3.347 ;
     RECT  110.4 3.059 110.808 3.347 ;
     RECT  118.32 3.251 118.812 3.347 ;
     RECT  104.832 2.963 106.008 3.395 ;
     RECT  169.632 2.291 170.112 3.923 ;
     RECT  120.912 3.155 125.16 12.083 ;
     RECT  128.592 2.963 129.72 12.275 ;
     RECT  128.592 12.275 129.612 12.325 ;
     RECT  126.432 3.155 127.032 12.421 ;
     RECT  128.208 12.325 129.612 12.421 ;
     RECT  119.856 12.469 119.88 12.517 ;
     RECT  120.912 12.083 125.112 12.517 ;
     RECT  126.432 12.421 129.612 12.563 ;
     RECT  126.48 12.563 129.612 12.611 ;
     RECT  118.5 3.347 118.812 12.901 ;
     RECT  119.856 12.517 125.112 12.901 ;
     RECT  118.5 12.901 125.112 13.045 ;
     RECT  126.48 12.611 128.232 13.139 ;
     RECT  90.288 3.109 90.312 18.515 ;
     RECT  64.5 2.151 64.812 19.141 ;
     RECT  126.6 13.139 128.232 21.155 ;
     RECT  63.744 19.141 64.812 21.251 ;
     RECT  105 3.395 105.312 21.253 ;
     RECT  115.8 3.251 116.112 21.397 ;
     RECT  0.192 14.581 0.216 21.491 ;
     RECT  94.2 3.155 94.512 21.541 ;
     RECT  52.56 21.541 52.584 21.637 ;
     RECT  53.7 2.151 54.012 21.637 ;
     RECT  69.9 2.151 70.212 21.637 ;
     RECT  72.6 2.151 72.912 21.637 ;
     RECT  107.7 3.107 108.012 21.637 ;
     RECT  88.8 2.151 89.112 21.685 ;
     RECT  71.712 21.637 72.912 21.781 ;
     RECT  88.8 21.685 89.496 22.067 ;
     RECT  80.7 2.151 81.012 22.117 ;
     RECT  82.128 21.541 82.152 22.117 ;
     RECT  59.1 2.151 59.412 22.165 ;
     RECT  83.4 2.151 83.712 22.165 ;
     RECT  105 21.253 105.96 22.165 ;
     RECT  107.232 21.637 108.012 22.165 ;
     RECT  113.1 3.203 113.412 22.165 ;
     RECT  118.5 13.045 125.352 22.165 ;
     RECT  52.56 21.637 54.012 22.213 ;
     RECT  56.4 2.151 56.712 22.213 ;
     RECT  78 2.151 78.312 22.213 ;
     RECT  118.08 22.165 125.352 22.259 ;
     RECT  51 2.151 51.312 22.309 ;
     RECT  52.56 22.213 54.456 22.309 ;
     RECT  94.2 21.541 95.448 22.453 ;
     RECT  96.9 3.203 97.212 22.453 ;
     RECT  102.3 3.347 102.612 22.501 ;
     RECT  58.32 22.165 59.412 22.597 ;
     RECT  60.768 22.453 60.792 22.597 ;
     RECT  115.488 21.397 116.112 22.645 ;
     RECT  115.44 22.645 116.112 22.693 ;
     RECT  56.4 22.213 57.048 22.741 ;
     RECT  71.712 21.781 73.848 22.741 ;
     RECT  75.3 2.151 75.612 22.741 ;
     RECT  78 22.213 78.504 22.741 ;
     RECT  126.6 21.155 127.848 22.741 ;
     RECT  80.7 22.117 82.152 22.787 ;
     RECT  80.7 22.787 82.008 22.789 ;
     RECT  83.232 22.165 83.712 22.789 ;
     RECT  99.6 3.251 99.912 22.789 ;
     RECT  102.3 22.501 102.792 22.789 ;
     RECT  110.4 3.347 110.712 22.789 ;
     RECT  121.2 22.259 125.16 22.835 ;
     RECT  126.144 22.741 127.848 22.835 ;
     RECT  86.1 2.151 86.412 22.837 ;
     RECT  121.2 22.835 124.212 22.883 ;
     RECT  102.3 22.789 103.56 23.077 ;
     RECT  94.2 22.453 97.212 23.173 ;
     RECT  102.144 23.077 103.56 23.173 ;
     RECT  110.4 22.789 110.856 23.173 ;
     RECT  63.792 21.251 64.812 23.269 ;
     RECT  93.408 23.173 97.212 23.269 ;
     RECT  51 22.309 54.456 23.317 ;
     RECT  83.232 22.789 83.928 23.317 ;
     RECT  93.408 23.269 97.416 23.317 ;
     RECT  109.728 23.173 110.856 23.317 ;
     RECT  61.8 2.151 62.112 23.365 ;
     RECT  63.792 23.269 65.16 23.365 ;
     RECT  67.2 2.151 67.512 23.365 ;
     RECT  69.9 21.637 70.344 23.365 ;
     RECT  83.232 23.317 84.6 23.365 ;
     RECT  126.144 22.835 126.912 23.411 ;
     RECT  105 22.165 108.012 23.701 ;
     RECT  67.2 23.365 70.584 23.749 ;
     RECT  115.44 22.693 117.096 23.749 ;
     RECT  118.08 22.259 119.832 23.749 ;
     RECT  123.504 22.883 124.212 23.795 ;
     RECT  78 22.741 78.792 23.893 ;
     RECT  86.1 22.837 86.616 23.893 ;
     RECT  99.216 22.789 99.912 23.893 ;
     RECT  126.6 23.411 126.912 23.893 ;
     RECT  71.712 22.741 75.612 23.939 ;
     RECT  93.264 23.317 98.184 23.939 ;
     RECT  51 23.317 55.224 23.941 ;
     RECT  56.4 22.741 57.096 23.941 ;
     RECT  109.728 23.317 111.144 23.941 ;
     RECT  112.416 22.165 114.312 23.941 ;
     RECT  115.44 23.749 119.832 23.941 ;
     RECT  71.952 23.939 75.612 23.989 ;
     RECT  77.184 23.893 78.792 23.989 ;
     RECT  99.216 23.893 100.008 23.989 ;
     RECT  109.248 23.941 111.144 24.037 ;
     RECT  112.32 23.941 119.832 24.037 ;
     RECT  71.952 23.989 78.792 24.133 ;
     RECT  80.4 22.789 82.008 24.229 ;
     RECT  58.32 22.597 60.792 24.373 ;
     RECT  61.8 23.365 62.376 24.373 ;
     RECT  99.216 23.989 100.104 24.421 ;
     RECT  101.184 23.173 103.56 24.421 ;
     RECT  101.184 24.421 103.608 24.469 ;
     RECT  104.88 23.701 108.012 24.469 ;
     RECT  58.32 24.373 62.376 24.517 ;
     RECT  63.792 23.365 66.072 24.517 ;
     RECT  91.5 2.137 91.812 24.517 ;
     RECT  99.216 24.421 100.152 24.517 ;
     RECT  71.952 24.133 78.84 24.757 ;
     RECT  126.6 23.893 127.224 24.803 ;
     RECT  51 23.941 57.096 24.901 ;
     RECT  58.32 24.517 66.072 24.901 ;
     RECT  101.184 24.469 108.012 24.901 ;
     RECT  83.232 23.365 84.888 24.997 ;
     RECT  67.2 23.749 70.728 25.045 ;
     RECT  71.952 24.757 79.176 25.045 ;
     RECT  93.408 23.939 98.184 25.045 ;
     RECT  99.216 24.517 100.2 25.045 ;
     RECT  67.2 25.045 79.176 25.093 ;
     RECT  80.4 24.229 82.056 25.093 ;
     RECT  91.5 24.517 92.28 25.093 ;
     RECT  93.408 25.045 100.2 25.093 ;
     RECT  101.184 24.901 108.168 25.093 ;
     RECT  109.248 24.037 119.832 25.093 ;
     RECT  121.2 22.883 122.088 25.093 ;
     RECT  67.2 25.093 82.056 25.189 ;
     RECT  51 24.901 66.072 25.381 ;
     RECT  67.056 25.189 82.056 25.381 ;
     RECT  83.184 24.997 84.888 25.429 ;
     RECT  51 25.381 82.056 25.525 ;
     RECT  83.184 25.429 85.08 25.525 ;
     RECT  86.1 23.893 86.952 25.669 ;
     RECT  91.5 25.093 100.2 25.669 ;
     RECT  101.184 25.093 122.088 25.669 ;
     RECT  123.696 23.795 124.212 25.669 ;
     RECT  51 25.525 85.08 25.717 ;
     RECT  86.1 25.669 87.528 25.717 ;
     RECT  91.5 25.669 124.212 25.717 ;
     RECT  51 25.717 87.528 25.957 ;
     RECT  91.5 25.717 124.344 25.957 ;
     RECT  50.832 25.957 87.528 26.005 ;
     RECT  91.2 25.957 124.344 26.149 ;
     RECT  88.8 22.067 89.112 26.197 ;
     RECT  126.6 24.803 126.912 26.245 ;
     RECT  50.736 26.005 87.528 26.293 ;
     RECT  88.8 26.197 89.784 26.293 ;
     RECT  126.6 26.245 127.08 26.293 ;
     RECT  50.736 26.293 89.784 26.389 ;
     RECT  50.736 26.389 90.216 26.533 ;
     RECT  50.496 26.533 90.216 26.771 ;
     RECT  50.496 26.771 89.928 26.773 ;
     RECT  48.3 2.151 48.612 26.869 ;
     RECT  50.352 26.773 89.928 26.869 ;
     RECT  125.904 26.293 127.08 27.301 ;
     RECT  91.2 26.149 124.872 27.397 ;
     RECT  125.904 27.301 127.128 27.397 ;
     RECT  91.2 27.397 127.128 27.637 ;
     RECT  48.3 26.869 89.928 27.877 ;
     RECT  45.6 2.151 45.912 27.925 ;
     RECT  91.2 27.637 127.224 27.925 ;
     RECT  2.4 2.151 2.712 28.089 ;
     RECT  5.1 2.151 5.412 28.089 ;
     RECT  7.8 2.151 8.112 28.089 ;
     RECT  10.5 2.151 10.812 28.089 ;
     RECT  13.2 2.151 13.512 28.089 ;
     RECT  15.9 2.151 16.212 28.089 ;
     RECT  18.6 2.151 18.912 28.089 ;
     RECT  21.3 2.151 21.612 28.089 ;
     RECT  24 2.151 24.312 28.089 ;
     RECT  26.7 2.151 27.012 28.089 ;
     RECT  29.4 2.151 29.712 28.089 ;
     RECT  32.1 2.151 32.412 28.089 ;
     RECT  34.8 2.151 35.112 28.089 ;
     RECT  37.5 2.151 37.812 28.089 ;
     RECT  40.2 2.151 40.512 28.089 ;
     RECT  42.9 2.151 43.212 28.089 ;
     RECT  129.3 12.611 129.612 28.089 ;
     RECT  132 1.859 132.312 28.089 ;
     RECT  134.7 2.915 135.012 28.089 ;
     RECT  137.4 2.963 137.712 28.089 ;
     RECT  140.1 3.251 140.412 28.089 ;
     RECT  142.8 2.963 143.112 28.089 ;
     RECT  145.5 3.107 145.812 28.089 ;
     RECT  148.2 3.203 148.512 28.089 ;
     RECT  150.9 2.915 151.212 28.089 ;
     RECT  153.6 3.059 153.912 28.089 ;
     RECT  156.3 3.107 156.612 28.089 ;
     RECT  159 3.251 159.312 28.089 ;
     RECT  161.7 3.107 162.012 28.089 ;
     RECT  164.4 3.107 164.712 28.089 ;
     RECT  167.1 3.155 167.412 28.089 ;
     RECT  169.8 3.923 170.112 28.089 ;
     RECT  2.4 28.089 2.52 28.103 ;
     RECT  5.1 28.089 5.22 28.103 ;
     RECT  7.8 28.089 7.92 28.103 ;
     RECT  10.5 28.089 10.62 28.103 ;
     RECT  13.2 28.089 13.32 28.103 ;
     RECT  15.9 28.089 16.02 28.103 ;
     RECT  18.6 28.089 18.72 28.103 ;
     RECT  21.3 28.089 21.42 28.103 ;
     RECT  24 28.089 24.12 28.103 ;
     RECT  26.7 28.089 26.82 28.103 ;
     RECT  29.4 28.089 29.52 28.103 ;
     RECT  32.1 28.089 32.22 28.103 ;
     RECT  34.8 28.089 34.92 28.103 ;
     RECT  37.5 28.089 37.62 28.103 ;
     RECT  40.2 28.089 40.32 28.103 ;
     RECT  42.9 28.089 43.02 28.103 ;
     RECT  45.12 27.925 46.536 28.103 ;
     RECT  47.616 27.877 89.928 28.103 ;
     RECT  129.3 28.089 129.42 28.103 ;
     RECT  132 28.089 132.12 28.103 ;
     RECT  134.7 28.089 134.82 28.103 ;
     RECT  137.4 28.089 137.52 28.103 ;
     RECT  140.1 28.089 140.22 28.103 ;
     RECT  142.8 28.089 142.92 28.103 ;
     RECT  145.5 28.089 145.62 28.103 ;
     RECT  148.2 28.089 148.32 28.103 ;
     RECT  150.9 28.089 151.02 28.103 ;
     RECT  153.6 28.089 153.72 28.103 ;
     RECT  156.3 28.089 156.42 28.103 ;
     RECT  159 28.089 159.12 28.103 ;
     RECT  161.7 28.089 161.82 28.103 ;
     RECT  164.4 28.089 164.52 28.103 ;
     RECT  167.1 28.089 167.22 28.103 ;
     RECT  169.8 28.089 169.92 28.103 ;
     RECT  89.328 28.103 89.928 28.405 ;
     RECT  91.056 27.925 127.224 28.405 ;
     RECT  45.12 28.103 45.288 30.224 ;
     RECT  46.368 28.103 46.536 30.224 ;
     RECT  47.616 28.103 88.248 30.224 ;
     RECT  89.328 28.405 127.512 30.224 ;
     RECT  91.128 0.016 92.112 0.132 ;
     RECT  130.392 0.016 131.376 0.132 ;
     RECT  90.984 0.131 91.008 0.132 ;
     RECT  90.936 0.132 92.16 0.611 ;
     RECT  130.344 0.132 131.424 1.763 ;
     RECT  90.936 0.611 92.304 1.763 ;
     RECT  90.912 1.763 92.304 1.811 ;
     RECT  90.912 1.811 92.88 2.137 ;
     RECT  170.112 1.811 171.312 2.339 ;
     RECT  92.904 1.859 94.2 2.291 ;
     RECT  90.912 2.137 91.5 3.109 ;
     RECT  91.812 2.137 92.88 2.291 ;
     RECT  106.008 2.291 106.992 2.915 ;
     RECT  153.912 2.291 154.896 2.915 ;
     RECT  170.112 2.339 171.456 2.915 ;
     RECT  102.792 2.915 104.256 2.963 ;
     RECT  106.008 2.915 107.136 2.963 ;
     RECT  119.688 2.915 120.816 2.963 ;
     RECT  135.012 2.915 136.032 2.963 ;
     RECT  136.2 2.915 137.4 3.059 ;
     RECT  149.736 2.915 150.9 2.963 ;
     RECT  160.536 2.915 161.568 3.059 ;
     RECT  165.72 2.915 166.704 3.107 ;
     RECT  100.824 2.963 101.952 3.011 ;
     RECT  108.888 2.963 110.256 3.059 ;
     RECT  113.784 2.963 114.912 3.059 ;
     RECT  119.688 2.963 120.912 3.107 ;
     RECT  127.512 2.963 128.592 3.059 ;
     RECT  135.012 2.963 136.176 3.059 ;
     RECT  143.112 2.963 144.096 3.107 ;
     RECT  144.12 2.963 145.5 3.107 ;
     RECT  157.08 2.963 158.352 3.107 ;
     RECT  100.824 3.011 102.144 3.251 ;
     RECT  110.808 3.011 112.032 3.203 ;
     RECT  147 3.011 148.2 3.107 ;
     RECT  116.808 3.059 117.792 3.251 ;
     RECT  160.536 3.059 161.7 3.107 ;
     RECT  112.056 3.107 113.1 3.203 ;
     RECT  89.112 3.109 90.288 18.515 ;
     RECT  90.312 3.109 91.5 18.515 ;
     RECT  125.16 3.155 126.432 12.083 ;
     RECT  125.112 12.083 126.432 12.563 ;
     RECT  127.032 12.325 128.208 12.421 ;
     RECT  118.812 12.469 119.856 12.901 ;
     RECT  119.88 12.469 120.912 12.517 ;
     RECT  125.112 12.563 126.48 13.045 ;
     RECT  128.232 12.611 129.3 21.155 ;
     RECT  125.352 13.045 126.48 13.139 ;
     RECT  125.352 13.139 126.6 22.259 ;
     RECT  127.848 21.155 129.3 22.835 ;
     RECT  51.312 21.541 52.56 22.309 ;
     RECT  52.584 21.541 53.7 21.637 ;
     RECT  81.012 21.541 82.128 22.117 ;
     RECT  82.152 21.541 83.4 22.165 ;
     RECT  95.448 21.541 96.9 22.453 ;
     RECT  70.344 21.637 71.712 23.365 ;
     RECT  105.96 21.637 107.232 22.165 ;
     RECT  73.848 21.781 75.3 22.741 ;
     RECT  82.152 22.165 83.232 22.787 ;
     RECT  114.312 22.165 115.488 22.645 ;
     RECT  57.048 22.213 58.32 22.741 ;
     RECT  119.832 22.259 121.2 25.093 ;
     RECT  125.16 22.259 126.6 22.741 ;
     RECT  59.412 22.453 60.768 22.597 ;
     RECT  60.792 22.453 61.8 24.373 ;
     RECT  114.312 22.645 115.44 23.941 ;
     RECT  117.096 22.693 118.08 23.749 ;
     RECT  57.096 22.741 58.32 24.901 ;
     RECT  125.16 22.741 126.144 22.835 ;
     RECT  82.008 22.787 83.232 24.229 ;
     RECT  103.56 22.789 105 23.701 ;
     RECT  126.912 22.835 127.224 23.893 ;
     RECT  122.088 22.883 123.504 23.795 ;
     RECT  99.912 23.173 101.184 23.893 ;
     RECT  55.224 23.317 56.4 23.941 ;
     RECT  84.6 23.317 86.1 23.365 ;
     RECT  91.812 23.317 93.264 23.939 ;
     RECT  98.184 23.317 99.216 25.045 ;
     RECT  111.144 23.317 112.416 23.941 ;
     RECT  62.376 23.365 63.792 24.517 ;
     RECT  66.072 23.365 67.2 25.189 ;
     RECT  70.584 23.365 71.712 23.749 ;
     RECT  84.888 23.365 86.1 25.429 ;
     RECT  103.56 23.701 104.88 24.421 ;
     RECT  70.728 23.749 71.712 23.939 ;
     RECT  100.008 23.893 101.184 23.989 ;
     RECT  70.728 23.939 71.952 25.045 ;
     RECT  91.812 23.939 93.408 24.517 ;
     RECT  108.012 23.941 109.248 24.901 ;
     RECT  111.144 23.941 112.32 24.037 ;
     RECT  100.104 23.989 101.184 24.421 ;
     RECT  82.056 24.229 83.232 24.997 ;
     RECT  100.152 24.421 101.184 24.517 ;
     RECT  103.608 24.421 104.88 24.469 ;
     RECT  92.28 24.517 93.408 25.093 ;
     RECT  100.2 24.517 101.184 25.669 ;
     RECT  79.176 24.757 80.4 25.093 ;
     RECT  126.912 24.803 127.08 26.245 ;
     RECT  108.168 24.901 109.248 25.093 ;
     RECT  82.056 24.997 83.184 25.525 ;
     RECT  66.072 25.189 67.056 25.381 ;
     RECT  85.08 25.429 86.1 25.717 ;
     RECT  87.528 25.669 88.8 26.293 ;
     RECT  89.784 26.197 91.2 26.389 ;
     RECT  124.872 26.293 125.904 27.397 ;
     RECT  90.216 26.389 91.2 26.771 ;
     RECT  89.928 26.771 91.2 27.925 ;
     RECT  46.536 27.925 47.616 30.108 ;
     RECT  89.928 27.925 91.056 28.405 ;
     RECT  45.288 28.103 46.368 30.108 ;
     RECT  88.248 28.103 89.328 30.108 ;
     RECT  45.336 30.108 46.32 30.224 ;
     RECT  46.584 30.108 47.568 30.224 ;
     RECT  88.296 30.108 89.28 30.224 ;
  END
END dsfd_sstn_e0c0
END LIBRARY
